VERSION 5.8 ;
BUSBITCHARS "[]" ;
DIVIDERCHAR "/" ;
UNITS
    DATABASE MICRONS 1000 ;
END UNITS

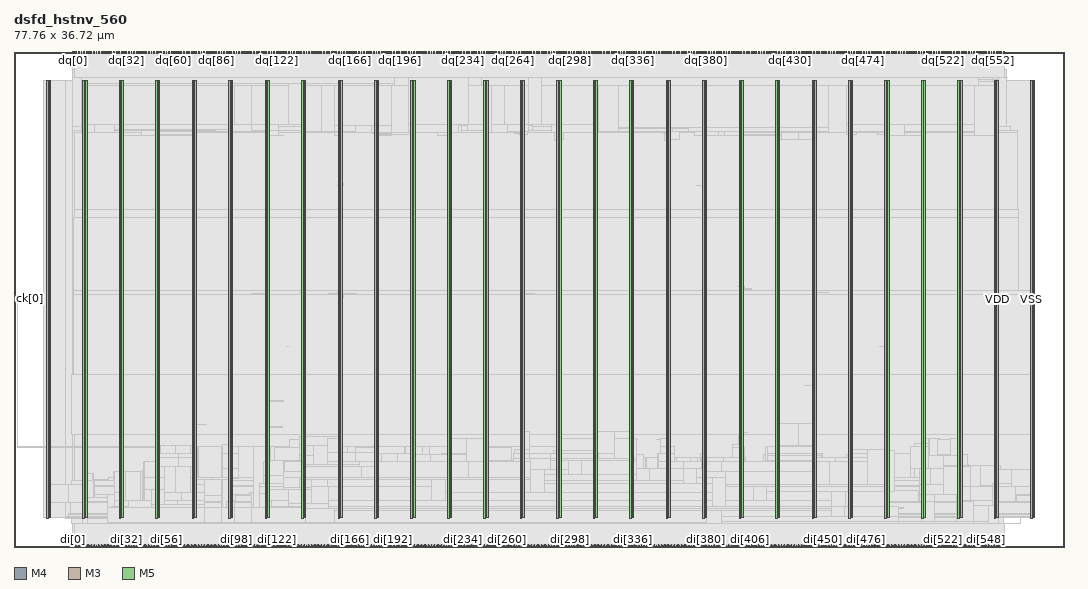
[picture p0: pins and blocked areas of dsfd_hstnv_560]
MACRO dsfd_hstnv_560
  FOREIGN dsfd_hstnv_560 0 0 ;
  CLASS BLOCK ;
  SIZE 77.76 BY 36.72 ;
  PIN ck[0]
    DIRECTION INPUT ;
    USE SIGNAL ;
    PORT
      LAYER M4 ;
        RECT  0 18.384 0.192 18.408 ;
    END
    PORT
      LAYER M4 ;
        RECT  0.156 18.384 0.275 18.408 ;
    END
  END ck[0]
  PIN di[0]
    DIRECTION INPUT ;
    USE SIGNAL ;
    PORT
      LAYER M3 ;
        RECT  4.356 0 4.374 0.144 ;
    END
  END di[0]
  PIN di[100]
    DIRECTION INPUT ;
    USE SIGNAL ;
    PORT
      LAYER M3 ;
        RECT  16.704 0 16.722 0.144 ;
    END
  END di[100]
  PIN di[101]
    DIRECTION INPUT ;
    USE SIGNAL ;
    PORT
      LAYER M5 ;
        RECT  16.848 0 16.872 0.192 ;
    END
  END di[101]
  PIN di[102]
    DIRECTION INPUT ;
    USE SIGNAL ;
    PORT
      LAYER M3 ;
        RECT  16.956 0 16.974 0.144 ;
    END
  END di[102]
  PIN di[103]
    DIRECTION INPUT ;
    USE SIGNAL ;
    PORT
      LAYER M5 ;
        RECT  17.088 0 17.112 0.192 ;
    END
  END di[103]
  PIN di[104]
    DIRECTION INPUT ;
    USE SIGNAL ;
    PORT
      LAYER M3 ;
        RECT  17.208 0 17.226 0.144 ;
    END
  END di[104]
  PIN di[105]
    DIRECTION INPUT ;
    USE SIGNAL ;
    PORT
      LAYER M5 ;
        RECT  17.328 0 17.352 0.192 ;
    END
  END di[105]
  PIN di[106]
    DIRECTION INPUT ;
    USE SIGNAL ;
    PORT
      LAYER M3 ;
        RECT  17.46 0 17.478 0.144 ;
    END
  END di[106]
  PIN di[107]
    DIRECTION INPUT ;
    USE SIGNAL ;
    PORT
      LAYER M5 ;
        RECT  17.568 0 17.592 0.192 ;
    END
  END di[107]
  PIN di[108]
    DIRECTION INPUT ;
    USE SIGNAL ;
    PORT
      LAYER M3 ;
        RECT  17.712 0 17.73 0.144 ;
    END
  END di[108]
  PIN di[109]
    DIRECTION INPUT ;
    USE SIGNAL ;
    PORT
      LAYER M5 ;
        RECT  17.808 0 17.832 0.192 ;
    END
  END di[109]
  PIN di[10]
    DIRECTION INPUT ;
    USE SIGNAL ;
    PORT
      LAYER M3 ;
        RECT  5.616 0 5.634 0.144 ;
    END
  END di[10]
  PIN di[110]
    DIRECTION INPUT ;
    USE SIGNAL ;
    PORT
      LAYER M3 ;
        RECT  17.964 0 17.982 0.144 ;
    END
  END di[110]
  PIN di[111]
    DIRECTION INPUT ;
    USE SIGNAL ;
    PORT
      LAYER M5 ;
        RECT  18.048 0 18.072 0.192 ;
    END
  END di[111]
  PIN di[112]
    DIRECTION INPUT ;
    USE SIGNAL ;
    PORT
      LAYER M3 ;
        RECT  18.18 0 18.198 0.144 ;
    END
  END di[112]
  PIN di[113]
    DIRECTION INPUT ;
    USE SIGNAL ;
    PORT
      LAYER M5 ;
        RECT  18.336 0 18.36 0.192 ;
    END
  END di[113]
  PIN di[114]
    DIRECTION INPUT ;
    USE SIGNAL ;
    PORT
      LAYER M3 ;
        RECT  18.432 0 18.45 0.144 ;
    END
  END di[114]
  PIN di[115]
    DIRECTION INPUT ;
    USE SIGNAL ;
    PORT
      LAYER M5 ;
        RECT  18.576 0 18.6 0.192 ;
    END
  END di[115]
  PIN di[116]
    DIRECTION INPUT ;
    USE SIGNAL ;
    PORT
      LAYER M3 ;
        RECT  18.684 0 18.702 0.144 ;
    END
  END di[116]
  PIN di[117]
    DIRECTION INPUT ;
    USE SIGNAL ;
    PORT
      LAYER M5 ;
        RECT  18.816 0 18.84 0.192 ;
    END
  END di[117]
  PIN di[118]
    DIRECTION INPUT ;
    USE SIGNAL ;
    PORT
      LAYER M3 ;
        RECT  18.936 0 18.954 0.144 ;
    END
  END di[118]
  PIN di[119]
    DIRECTION INPUT ;
    USE SIGNAL ;
    PORT
      LAYER M5 ;
        RECT  19.056 0 19.08 0.192 ;
    END
  END di[119]
  PIN di[11]
    DIRECTION INPUT ;
    USE SIGNAL ;
    PORT
      LAYER M5 ;
        RECT  5.712 0 5.736 0.192 ;
    END
  END di[11]
  PIN di[120]
    DIRECTION INPUT ;
    USE SIGNAL ;
    PORT
      LAYER M3 ;
        RECT  19.188 0 19.206 0.144 ;
    END
  END di[120]
  PIN di[121]
    DIRECTION INPUT ;
    USE SIGNAL ;
    PORT
      LAYER M5 ;
        RECT  19.296 0 19.32 0.192 ;
    END
  END di[121]
  PIN di[122]
    DIRECTION INPUT ;
    USE SIGNAL ;
    PORT
      LAYER M3 ;
        RECT  19.44 0 19.458 0.144 ;
    END
  END di[122]
  PIN di[123]
    DIRECTION INPUT ;
    USE SIGNAL ;
    PORT
      LAYER M5 ;
        RECT  19.536 0 19.56 0.192 ;
    END
  END di[123]
  PIN di[124]
    DIRECTION INPUT ;
    USE SIGNAL ;
    PORT
      LAYER M3 ;
        RECT  19.692 0 19.71 0.144 ;
    END
  END di[124]
  PIN di[125]
    DIRECTION INPUT ;
    USE SIGNAL ;
    PORT
      LAYER M5 ;
        RECT  19.776 0 19.8 0.192 ;
    END
  END di[125]
  PIN di[126]
    DIRECTION INPUT ;
    USE SIGNAL ;
    PORT
      LAYER M3 ;
        RECT  19.908 0 19.926 0.144 ;
    END
  END di[126]
  PIN di[127]
    DIRECTION INPUT ;
    USE SIGNAL ;
    PORT
      LAYER M5 ;
        RECT  20.064 0 20.088 0.192 ;
    END
  END di[127]
  PIN di[128]
    DIRECTION INPUT ;
    USE SIGNAL ;
    PORT
      LAYER M3 ;
        RECT  20.16 0 20.178 0.144 ;
    END
  END di[128]
  PIN di[129]
    DIRECTION INPUT ;
    USE SIGNAL ;
    PORT
      LAYER M5 ;
        RECT  20.304 0 20.328 0.192 ;
    END
  END di[129]
  PIN di[12]
    DIRECTION INPUT ;
    USE SIGNAL ;
    PORT
      LAYER M3 ;
        RECT  5.868 0 5.886 0.144 ;
    END
  END di[12]
  PIN di[130]
    DIRECTION INPUT ;
    USE SIGNAL ;
    PORT
      LAYER M3 ;
        RECT  20.412 0 20.43 0.144 ;
    END
  END di[130]
  PIN di[131]
    DIRECTION INPUT ;
    USE SIGNAL ;
    PORT
      LAYER M5 ;
        RECT  20.544 0 20.568 0.192 ;
    END
  END di[131]
  PIN di[132]
    DIRECTION INPUT ;
    USE SIGNAL ;
    PORT
      LAYER M3 ;
        RECT  20.664 0 20.682 0.144 ;
    END
  END di[132]
  PIN di[133]
    DIRECTION INPUT ;
    USE SIGNAL ;
    PORT
      LAYER M5 ;
        RECT  20.784 0 20.808 0.192 ;
    END
  END di[133]
  PIN di[134]
    DIRECTION INPUT ;
    USE SIGNAL ;
    PORT
      LAYER M3 ;
        RECT  20.916 0 20.934 0.144 ;
    END
  END di[134]
  PIN di[135]
    DIRECTION INPUT ;
    USE SIGNAL ;
    PORT
      LAYER M5 ;
        RECT  21.024 0 21.048 0.192 ;
    END
  END di[135]
  PIN di[136]
    DIRECTION INPUT ;
    USE SIGNAL ;
    PORT
      LAYER M3 ;
        RECT  21.168 0 21.186 0.144 ;
    END
  END di[136]
  PIN di[137]
    DIRECTION INPUT ;
    USE SIGNAL ;
    PORT
      LAYER M5 ;
        RECT  21.264 0 21.288 0.192 ;
    END
  END di[137]
  PIN di[138]
    DIRECTION INPUT ;
    USE SIGNAL ;
    PORT
      LAYER M3 ;
        RECT  21.42 0 21.438 0.144 ;
    END
  END di[138]
  PIN di[139]
    DIRECTION INPUT ;
    USE SIGNAL ;
    PORT
      LAYER M5 ;
        RECT  21.504 0 21.528 0.192 ;
    END
  END di[139]
  PIN di[13]
    DIRECTION INPUT ;
    USE SIGNAL ;
    PORT
      LAYER M5 ;
        RECT  5.952 0 5.976 0.192 ;
    END
  END di[13]
  PIN di[140]
    DIRECTION INPUT ;
    USE SIGNAL ;
    PORT
      LAYER M3 ;
        RECT  21.636 0 21.654 0.144 ;
    END
  END di[140]
  PIN di[141]
    DIRECTION INPUT ;
    USE SIGNAL ;
    PORT
      LAYER M5 ;
        RECT  21.792 0 21.816 0.192 ;
    END
  END di[141]
  PIN di[142]
    DIRECTION INPUT ;
    USE SIGNAL ;
    PORT
      LAYER M3 ;
        RECT  21.888 0 21.906 0.144 ;
    END
  END di[142]
  PIN di[143]
    DIRECTION INPUT ;
    USE SIGNAL ;
    PORT
      LAYER M5 ;
        RECT  22.032 0 22.056 0.192 ;
    END
  END di[143]
  PIN di[144]
    DIRECTION INPUT ;
    USE SIGNAL ;
    PORT
      LAYER M3 ;
        RECT  22.14 0 22.158 0.144 ;
    END
  END di[144]
  PIN di[145]
    DIRECTION INPUT ;
    USE SIGNAL ;
    PORT
      LAYER M5 ;
        RECT  22.272 0 22.296 0.192 ;
    END
  END di[145]
  PIN di[146]
    DIRECTION INPUT ;
    USE SIGNAL ;
    PORT
      LAYER M3 ;
        RECT  22.392 0 22.41 0.144 ;
    END
  END di[146]
  PIN di[147]
    DIRECTION INPUT ;
    USE SIGNAL ;
    PORT
      LAYER M5 ;
        RECT  22.512 0 22.536 0.192 ;
    END
  END di[147]
  PIN di[148]
    DIRECTION INPUT ;
    USE SIGNAL ;
    PORT
      LAYER M3 ;
        RECT  22.644 0 22.662 0.144 ;
    END
  END di[148]
  PIN di[149]
    DIRECTION INPUT ;
    USE SIGNAL ;
    PORT
      LAYER M5 ;
        RECT  22.752 0 22.776 0.192 ;
    END
  END di[149]
  PIN di[14]
    DIRECTION INPUT ;
    USE SIGNAL ;
    PORT
      LAYER M3 ;
        RECT  6.084 0 6.102 0.144 ;
    END
  END di[14]
  PIN di[150]
    DIRECTION INPUT ;
    USE SIGNAL ;
    PORT
      LAYER M3 ;
        RECT  22.896 0 22.914 0.144 ;
    END
  END di[150]
  PIN di[151]
    DIRECTION INPUT ;
    USE SIGNAL ;
    PORT
      LAYER M5 ;
        RECT  22.992 0 23.016 0.192 ;
    END
  END di[151]
  PIN di[152]
    DIRECTION INPUT ;
    USE SIGNAL ;
    PORT
      LAYER M3 ;
        RECT  23.148 0 23.166 0.144 ;
    END
  END di[152]
  PIN di[153]
    DIRECTION INPUT ;
    USE SIGNAL ;
    PORT
      LAYER M5 ;
        RECT  23.232 0 23.256 0.192 ;
    END
  END di[153]
  PIN di[154]
    DIRECTION INPUT ;
    USE SIGNAL ;
    PORT
      LAYER M3 ;
        RECT  23.364 0 23.382 0.144 ;
    END
  END di[154]
  PIN di[155]
    DIRECTION INPUT ;
    USE SIGNAL ;
    PORT
      LAYER M5 ;
        RECT  23.52 0 23.544 0.192 ;
    END
  END di[155]
  PIN di[156]
    DIRECTION INPUT ;
    USE SIGNAL ;
    PORT
      LAYER M3 ;
        RECT  23.616 0 23.634 0.144 ;
    END
  END di[156]
  PIN di[157]
    DIRECTION INPUT ;
    USE SIGNAL ;
    PORT
      LAYER M5 ;
        RECT  23.76 0 23.784 0.192 ;
    END
  END di[157]
  PIN di[158]
    DIRECTION INPUT ;
    USE SIGNAL ;
    PORT
      LAYER M3 ;
        RECT  23.868 0 23.886 0.144 ;
    END
  END di[158]
  PIN di[159]
    DIRECTION INPUT ;
    USE SIGNAL ;
    PORT
      LAYER M5 ;
        RECT  24 0 24.024 0.192 ;
    END
  END di[159]
  PIN di[15]
    DIRECTION INPUT ;
    USE SIGNAL ;
    PORT
      LAYER M5 ;
        RECT  6.24 0 6.264 0.192 ;
    END
  END di[15]
  PIN di[160]
    DIRECTION INPUT ;
    USE SIGNAL ;
    PORT
      LAYER M3 ;
        RECT  24.12 0 24.138 0.144 ;
    END
  END di[160]
  PIN di[161]
    DIRECTION INPUT ;
    USE SIGNAL ;
    PORT
      LAYER M5 ;
        RECT  24.24 0 24.264 0.192 ;
    END
  END di[161]
  PIN di[162]
    DIRECTION INPUT ;
    USE SIGNAL ;
    PORT
      LAYER M3 ;
        RECT  24.372 0 24.39 0.144 ;
    END
  END di[162]
  PIN di[163]
    DIRECTION INPUT ;
    USE SIGNAL ;
    PORT
      LAYER M5 ;
        RECT  24.48 0 24.504 0.192 ;
    END
  END di[163]
  PIN di[164]
    DIRECTION INPUT ;
    USE SIGNAL ;
    PORT
      LAYER M3 ;
        RECT  24.624 0 24.642 0.144 ;
    END
  END di[164]
  PIN di[165]
    DIRECTION INPUT ;
    USE SIGNAL ;
    PORT
      LAYER M5 ;
        RECT  24.72 0 24.744 0.192 ;
    END
  END di[165]
  PIN di[166]
    DIRECTION INPUT ;
    USE SIGNAL ;
    PORT
      LAYER M3 ;
        RECT  24.876 0 24.894 0.144 ;
    END
  END di[166]
  PIN di[167]
    DIRECTION INPUT ;
    USE SIGNAL ;
    PORT
      LAYER M5 ;
        RECT  24.96 0 24.984 0.192 ;
    END
  END di[167]
  PIN di[168]
    DIRECTION INPUT ;
    USE SIGNAL ;
    PORT
      LAYER M3 ;
        RECT  25.092 0 25.11 0.144 ;
    END
  END di[168]
  PIN di[169]
    DIRECTION INPUT ;
    USE SIGNAL ;
    PORT
      LAYER M5 ;
        RECT  25.248 0 25.272 0.192 ;
    END
  END di[169]
  PIN di[16]
    DIRECTION INPUT ;
    USE SIGNAL ;
    PORT
      LAYER M3 ;
        RECT  6.336 0 6.354 0.144 ;
    END
  END di[16]
  PIN di[170]
    DIRECTION INPUT ;
    USE SIGNAL ;
    PORT
      LAYER M3 ;
        RECT  25.344 0 25.362 0.144 ;
    END
  END di[170]
  PIN di[171]
    DIRECTION INPUT ;
    USE SIGNAL ;
    PORT
      LAYER M5 ;
        RECT  25.488 0 25.512 0.192 ;
    END
  END di[171]
  PIN di[172]
    DIRECTION INPUT ;
    USE SIGNAL ;
    PORT
      LAYER M3 ;
        RECT  25.596 0 25.614 0.144 ;
    END
  END di[172]
  PIN di[173]
    DIRECTION INPUT ;
    USE SIGNAL ;
    PORT
      LAYER M5 ;
        RECT  25.728 0 25.752 0.192 ;
    END
  END di[173]
  PIN di[174]
    DIRECTION INPUT ;
    USE SIGNAL ;
    PORT
      LAYER M3 ;
        RECT  25.848 0 25.866 0.144 ;
    END
  END di[174]
  PIN di[175]
    DIRECTION INPUT ;
    USE SIGNAL ;
    PORT
      LAYER M5 ;
        RECT  25.968 0 25.992 0.192 ;
    END
  END di[175]
  PIN di[176]
    DIRECTION INPUT ;
    USE SIGNAL ;
    PORT
      LAYER M3 ;
        RECT  26.1 0 26.118 0.144 ;
    END
  END di[176]
  PIN di[177]
    DIRECTION INPUT ;
    USE SIGNAL ;
    PORT
      LAYER M5 ;
        RECT  26.208 0 26.232 0.192 ;
    END
  END di[177]
  PIN di[178]
    DIRECTION INPUT ;
    USE SIGNAL ;
    PORT
      LAYER M3 ;
        RECT  26.352 0 26.37 0.144 ;
    END
  END di[178]
  PIN di[179]
    DIRECTION INPUT ;
    USE SIGNAL ;
    PORT
      LAYER M5 ;
        RECT  26.448 0 26.472 0.192 ;
    END
  END di[179]
  PIN di[17]
    DIRECTION INPUT ;
    USE SIGNAL ;
    PORT
      LAYER M5 ;
        RECT  6.48 0 6.504 0.192 ;
    END
  END di[17]
  PIN di[180]
    DIRECTION INPUT ;
    USE SIGNAL ;
    PORT
      LAYER M3 ;
        RECT  26.604 0 26.622 0.144 ;
    END
  END di[180]
  PIN di[181]
    DIRECTION INPUT ;
    USE SIGNAL ;
    PORT
      LAYER M5 ;
        RECT  26.688 0 26.712 0.192 ;
    END
  END di[181]
  PIN di[182]
    DIRECTION INPUT ;
    USE SIGNAL ;
    PORT
      LAYER M3 ;
        RECT  26.82 0 26.838 0.144 ;
    END
  END di[182]
  PIN di[183]
    DIRECTION INPUT ;
    USE SIGNAL ;
    PORT
      LAYER M5 ;
        RECT  26.976 0 27 0.192 ;
    END
  END di[183]
  PIN di[184]
    DIRECTION INPUT ;
    USE SIGNAL ;
    PORT
      LAYER M3 ;
        RECT  27.072 0 27.09 0.144 ;
    END
  END di[184]
  PIN di[185]
    DIRECTION INPUT ;
    USE SIGNAL ;
    PORT
      LAYER M5 ;
        RECT  27.216 0 27.24 0.192 ;
    END
  END di[185]
  PIN di[186]
    DIRECTION INPUT ;
    USE SIGNAL ;
    PORT
      LAYER M3 ;
        RECT  27.324 0 27.342 0.144 ;
    END
  END di[186]
  PIN di[187]
    DIRECTION INPUT ;
    USE SIGNAL ;
    PORT
      LAYER M5 ;
        RECT  27.456 0 27.48 0.192 ;
    END
  END di[187]
  PIN di[188]
    DIRECTION INPUT ;
    USE SIGNAL ;
    PORT
      LAYER M3 ;
        RECT  27.576 0 27.594 0.144 ;
    END
  END di[188]
  PIN di[189]
    DIRECTION INPUT ;
    USE SIGNAL ;
    PORT
      LAYER M5 ;
        RECT  27.696 0 27.72 0.192 ;
    END
  END di[189]
  PIN di[18]
    DIRECTION INPUT ;
    USE SIGNAL ;
    PORT
      LAYER M3 ;
        RECT  6.588 0 6.606 0.144 ;
    END
  END di[18]
  PIN di[190]
    DIRECTION INPUT ;
    USE SIGNAL ;
    PORT
      LAYER M3 ;
        RECT  27.828 0 27.846 0.144 ;
    END
  END di[190]
  PIN di[191]
    DIRECTION INPUT ;
    USE SIGNAL ;
    PORT
      LAYER M5 ;
        RECT  27.936 0 27.96 0.192 ;
    END
  END di[191]
  PIN di[192]
    DIRECTION INPUT ;
    USE SIGNAL ;
    PORT
      LAYER M3 ;
        RECT  28.08 0 28.098 0.144 ;
    END
  END di[192]
  PIN di[193]
    DIRECTION INPUT ;
    USE SIGNAL ;
    PORT
      LAYER M5 ;
        RECT  28.176 0 28.2 0.192 ;
    END
  END di[193]
  PIN di[194]
    DIRECTION INPUT ;
    USE SIGNAL ;
    PORT
      LAYER M3 ;
        RECT  28.332 0 28.35 0.144 ;
    END
  END di[194]
  PIN di[195]
    DIRECTION INPUT ;
    USE SIGNAL ;
    PORT
      LAYER M5 ;
        RECT  28.416 0 28.44 0.192 ;
    END
  END di[195]
  PIN di[196]
    DIRECTION INPUT ;
    USE SIGNAL ;
    PORT
      LAYER M3 ;
        RECT  28.548 0 28.566 0.144 ;
    END
  END di[196]
  PIN di[197]
    DIRECTION INPUT ;
    USE SIGNAL ;
    PORT
      LAYER M5 ;
        RECT  28.704 0 28.728 0.192 ;
    END
  END di[197]
  PIN di[198]
    DIRECTION INPUT ;
    USE SIGNAL ;
    PORT
      LAYER M3 ;
        RECT  28.8 0 28.818 0.144 ;
    END
  END di[198]
  PIN di[199]
    DIRECTION INPUT ;
    USE SIGNAL ;
    PORT
      LAYER M5 ;
        RECT  28.944 0 28.968 0.192 ;
    END
  END di[199]
  PIN di[19]
    DIRECTION INPUT ;
    USE SIGNAL ;
    PORT
      LAYER M5 ;
        RECT  6.72 0 6.744 0.192 ;
    END
  END di[19]
  PIN di[1]
    DIRECTION INPUT ;
    USE SIGNAL ;
    PORT
      LAYER M5 ;
        RECT  4.512 0 4.536 0.192 ;
    END
  END di[1]
  PIN di[200]
    DIRECTION INPUT ;
    USE SIGNAL ;
    PORT
      LAYER M3 ;
        RECT  29.052 0 29.07 0.144 ;
    END
  END di[200]
  PIN di[201]
    DIRECTION INPUT ;
    USE SIGNAL ;
    PORT
      LAYER M5 ;
        RECT  29.184 0 29.208 0.192 ;
    END
  END di[201]
  PIN di[202]
    DIRECTION INPUT ;
    USE SIGNAL ;
    PORT
      LAYER M3 ;
        RECT  29.304 0 29.322 0.144 ;
    END
  END di[202]
  PIN di[203]
    DIRECTION INPUT ;
    USE SIGNAL ;
    PORT
      LAYER M5 ;
        RECT  29.424 0 29.448 0.192 ;
    END
  END di[203]
  PIN di[204]
    DIRECTION INPUT ;
    USE SIGNAL ;
    PORT
      LAYER M3 ;
        RECT  29.556 0 29.574 0.144 ;
    END
  END di[204]
  PIN di[205]
    DIRECTION INPUT ;
    USE SIGNAL ;
    PORT
      LAYER M5 ;
        RECT  29.664 0 29.688 0.192 ;
    END
  END di[205]
  PIN di[206]
    DIRECTION INPUT ;
    USE SIGNAL ;
    PORT
      LAYER M3 ;
        RECT  29.808 0 29.826 0.144 ;
    END
  END di[206]
  PIN di[207]
    DIRECTION INPUT ;
    USE SIGNAL ;
    PORT
      LAYER M5 ;
        RECT  29.904 0 29.928 0.192 ;
    END
  END di[207]
  PIN di[208]
    DIRECTION INPUT ;
    USE SIGNAL ;
    PORT
      LAYER M3 ;
        RECT  30.06 0 30.078 0.144 ;
    END
  END di[208]
  PIN di[209]
    DIRECTION INPUT ;
    USE SIGNAL ;
    PORT
      LAYER M5 ;
        RECT  30.144 0 30.168 0.192 ;
    END
  END di[209]
  PIN di[20]
    DIRECTION INPUT ;
    USE SIGNAL ;
    PORT
      LAYER M3 ;
        RECT  6.84 0 6.858 0.144 ;
    END
  END di[20]
  PIN di[210]
    DIRECTION INPUT ;
    USE SIGNAL ;
    PORT
      LAYER M3 ;
        RECT  30.276 0 30.294 0.144 ;
    END
  END di[210]
  PIN di[211]
    DIRECTION INPUT ;
    USE SIGNAL ;
    PORT
      LAYER M5 ;
        RECT  30.432 0 30.456 0.192 ;
    END
  END di[211]
  PIN di[212]
    DIRECTION INPUT ;
    USE SIGNAL ;
    PORT
      LAYER M3 ;
        RECT  30.528 0 30.546 0.144 ;
    END
  END di[212]
  PIN di[213]
    DIRECTION INPUT ;
    USE SIGNAL ;
    PORT
      LAYER M5 ;
        RECT  30.672 0 30.696 0.192 ;
    END
  END di[213]
  PIN di[214]
    DIRECTION INPUT ;
    USE SIGNAL ;
    PORT
      LAYER M3 ;
        RECT  30.78 0 30.798 0.144 ;
    END
  END di[214]
  PIN di[215]
    DIRECTION INPUT ;
    USE SIGNAL ;
    PORT
      LAYER M5 ;
        RECT  30.912 0 30.936 0.192 ;
    END
  END di[215]
  PIN di[216]
    DIRECTION INPUT ;
    USE SIGNAL ;
    PORT
      LAYER M3 ;
        RECT  31.032 0 31.05 0.144 ;
    END
  END di[216]
  PIN di[217]
    DIRECTION INPUT ;
    USE SIGNAL ;
    PORT
      LAYER M5 ;
        RECT  31.152 0 31.176 0.192 ;
    END
  END di[217]
  PIN di[218]
    DIRECTION INPUT ;
    USE SIGNAL ;
    PORT
      LAYER M3 ;
        RECT  31.284 0 31.302 0.144 ;
    END
  END di[218]
  PIN di[219]
    DIRECTION INPUT ;
    USE SIGNAL ;
    PORT
      LAYER M5 ;
        RECT  31.392 0 31.416 0.192 ;
    END
  END di[219]
  PIN di[21]
    DIRECTION INPUT ;
    USE SIGNAL ;
    PORT
      LAYER M5 ;
        RECT  6.96 0 6.984 0.192 ;
    END
  END di[21]
  PIN di[220]
    DIRECTION INPUT ;
    USE SIGNAL ;
    PORT
      LAYER M3 ;
        RECT  31.536 0 31.554 0.144 ;
    END
  END di[220]
  PIN di[221]
    DIRECTION INPUT ;
    USE SIGNAL ;
    PORT
      LAYER M5 ;
        RECT  31.632 0 31.656 0.192 ;
    END
  END di[221]
  PIN di[222]
    DIRECTION INPUT ;
    USE SIGNAL ;
    PORT
      LAYER M3 ;
        RECT  31.788 0 31.806 0.144 ;
    END
  END di[222]
  PIN di[223]
    DIRECTION INPUT ;
    USE SIGNAL ;
    PORT
      LAYER M5 ;
        RECT  31.872 0 31.896 0.192 ;
    END
  END di[223]
  PIN di[224]
    DIRECTION INPUT ;
    USE SIGNAL ;
    PORT
      LAYER M3 ;
        RECT  32.004 0 32.022 0.144 ;
    END
  END di[224]
  PIN di[225]
    DIRECTION INPUT ;
    USE SIGNAL ;
    PORT
      LAYER M5 ;
        RECT  32.16 0 32.184 0.192 ;
    END
  END di[225]
  PIN di[226]
    DIRECTION INPUT ;
    USE SIGNAL ;
    PORT
      LAYER M3 ;
        RECT  32.256 0 32.274 0.144 ;
    END
  END di[226]
  PIN di[227]
    DIRECTION INPUT ;
    USE SIGNAL ;
    PORT
      LAYER M5 ;
        RECT  32.4 0 32.424 0.192 ;
    END
  END di[227]
  PIN di[228]
    DIRECTION INPUT ;
    USE SIGNAL ;
    PORT
      LAYER M3 ;
        RECT  32.508 0 32.526 0.144 ;
    END
  END di[228]
  PIN di[229]
    DIRECTION INPUT ;
    USE SIGNAL ;
    PORT
      LAYER M5 ;
        RECT  32.64 0 32.664 0.192 ;
    END
  END di[229]
  PIN di[22]
    DIRECTION INPUT ;
    USE SIGNAL ;
    PORT
      LAYER M3 ;
        RECT  7.092 0 7.11 0.144 ;
    END
  END di[22]
  PIN di[230]
    DIRECTION INPUT ;
    USE SIGNAL ;
    PORT
      LAYER M3 ;
        RECT  32.76 0 32.778 0.144 ;
    END
  END di[230]
  PIN di[231]
    DIRECTION INPUT ;
    USE SIGNAL ;
    PORT
      LAYER M5 ;
        RECT  32.88 0 32.904 0.192 ;
    END
  END di[231]
  PIN di[232]
    DIRECTION INPUT ;
    USE SIGNAL ;
    PORT
      LAYER M3 ;
        RECT  33.012 0 33.03 0.144 ;
    END
  END di[232]
  PIN di[233]
    DIRECTION INPUT ;
    USE SIGNAL ;
    PORT
      LAYER M5 ;
        RECT  33.12 0 33.144 0.192 ;
    END
  END di[233]
  PIN di[234]
    DIRECTION INPUT ;
    USE SIGNAL ;
    PORT
      LAYER M3 ;
        RECT  33.264 0 33.282 0.144 ;
    END
  END di[234]
  PIN di[235]
    DIRECTION INPUT ;
    USE SIGNAL ;
    PORT
      LAYER M5 ;
        RECT  33.36 0 33.384 0.192 ;
    END
  END di[235]
  PIN di[236]
    DIRECTION INPUT ;
    USE SIGNAL ;
    PORT
      LAYER M3 ;
        RECT  33.516 0 33.534 0.144 ;
    END
  END di[236]
  PIN di[237]
    DIRECTION INPUT ;
    USE SIGNAL ;
    PORT
      LAYER M5 ;
        RECT  33.6 0 33.624 0.192 ;
    END
  END di[237]
  PIN di[238]
    DIRECTION INPUT ;
    USE SIGNAL ;
    PORT
      LAYER M3 ;
        RECT  33.732 0 33.75 0.144 ;
    END
  END di[238]
  PIN di[239]
    DIRECTION INPUT ;
    USE SIGNAL ;
    PORT
      LAYER M5 ;
        RECT  33.888 0 33.912 0.192 ;
    END
    PORT
      LAYER M5 ;
        RECT  33.744 0.133 34.008 0.144 ;
    END
  END di[239]
  PIN di[23]
    DIRECTION INPUT ;
    USE SIGNAL ;
    PORT
      LAYER M5 ;
        RECT  7.2 0 7.224 0.192 ;
    END
  END di[23]
  PIN di[240]
    DIRECTION INPUT ;
    USE SIGNAL ;
    PORT
      LAYER M3 ;
        RECT  33.984 0 34.002 0.144 ;
    END
  END di[240]
  PIN di[241]
    DIRECTION INPUT ;
    USE SIGNAL ;
    PORT
      LAYER M5 ;
        RECT  34.128 0 34.152 0.192 ;
    END
  END di[241]
  PIN di[242]
    DIRECTION INPUT ;
    USE SIGNAL ;
    PORT
      LAYER M3 ;
        RECT  34.236 0 34.254 0.144 ;
    END
  END di[242]
  PIN di[243]
    DIRECTION INPUT ;
    USE SIGNAL ;
    PORT
      LAYER M5 ;
        RECT  34.368 0 34.392 0.192 ;
    END
  END di[243]
  PIN di[244]
    DIRECTION INPUT ;
    USE SIGNAL ;
    PORT
      LAYER M3 ;
        RECT  34.488 0 34.506 0.144 ;
    END
  END di[244]
  PIN di[245]
    DIRECTION INPUT ;
    USE SIGNAL ;
    PORT
      LAYER M5 ;
        RECT  34.608 0 34.632 0.192 ;
    END
  END di[245]
  PIN di[246]
    DIRECTION INPUT ;
    USE SIGNAL ;
    PORT
      LAYER M3 ;
        RECT  34.74 0 34.758 0.144 ;
    END
  END di[246]
  PIN di[247]
    DIRECTION INPUT ;
    USE SIGNAL ;
    PORT
      LAYER M5 ;
        RECT  34.848 0 34.872 0.192 ;
    END
  END di[247]
  PIN di[248]
    DIRECTION INPUT ;
    USE SIGNAL ;
    PORT
      LAYER M3 ;
        RECT  34.992 0 35.01 0.144 ;
    END
  END di[248]
  PIN di[249]
    DIRECTION INPUT ;
    USE SIGNAL ;
    PORT
      LAYER M5 ;
        RECT  35.088 0 35.112 0.192 ;
    END
  END di[249]
  PIN di[24]
    DIRECTION INPUT ;
    USE SIGNAL ;
    PORT
      LAYER M3 ;
        RECT  7.344 0 7.362 0.144 ;
    END
  END di[24]
  PIN di[250]
    DIRECTION INPUT ;
    USE SIGNAL ;
    PORT
      LAYER M3 ;
        RECT  35.244 0 35.262 0.144 ;
    END
  END di[250]
  PIN di[251]
    DIRECTION INPUT ;
    USE SIGNAL ;
    PORT
      LAYER M5 ;
        RECT  35.328 0 35.352 0.192 ;
    END
  END di[251]
  PIN di[252]
    DIRECTION INPUT ;
    USE SIGNAL ;
    PORT
      LAYER M3 ;
        RECT  35.46 0 35.478 0.144 ;
    END
  END di[252]
  PIN di[253]
    DIRECTION INPUT ;
    USE SIGNAL ;
    PORT
      LAYER M5 ;
        RECT  35.616 0 35.64 0.192 ;
    END
  END di[253]
  PIN di[254]
    DIRECTION INPUT ;
    USE SIGNAL ;
    PORT
      LAYER M3 ;
        RECT  35.712 0 35.73 0.144 ;
    END
  END di[254]
  PIN di[255]
    DIRECTION INPUT ;
    USE SIGNAL ;
    PORT
      LAYER M5 ;
        RECT  35.856 0 35.88 0.192 ;
    END
  END di[255]
  PIN di[256]
    DIRECTION INPUT ;
    USE SIGNAL ;
    PORT
      LAYER M3 ;
        RECT  35.964 0 35.982 0.144 ;
    END
  END di[256]
  PIN di[257]
    DIRECTION INPUT ;
    USE SIGNAL ;
    PORT
      LAYER M5 ;
        RECT  36.096 0 36.12 0.192 ;
    END
  END di[257]
  PIN di[258]
    DIRECTION INPUT ;
    USE SIGNAL ;
    PORT
      LAYER M3 ;
        RECT  36.216 0 36.234 0.144 ;
    END
  END di[258]
  PIN di[259]
    DIRECTION INPUT ;
    USE SIGNAL ;
    PORT
      LAYER M5 ;
        RECT  36.336 0 36.36 0.192 ;
    END
  END di[259]
  PIN di[25]
    DIRECTION INPUT ;
    USE SIGNAL ;
    PORT
      LAYER M5 ;
        RECT  7.44 0 7.464 0.192 ;
    END
  END di[25]
  PIN di[260]
    DIRECTION INPUT ;
    USE SIGNAL ;
    PORT
      LAYER M3 ;
        RECT  36.468 0 36.486 0.144 ;
    END
  END di[260]
  PIN di[261]
    DIRECTION INPUT ;
    USE SIGNAL ;
    PORT
      LAYER M5 ;
        RECT  36.576 0 36.6 0.192 ;
    END
  END di[261]
  PIN di[262]
    DIRECTION INPUT ;
    USE SIGNAL ;
    PORT
      LAYER M3 ;
        RECT  36.72 0 36.738 0.144 ;
    END
  END di[262]
  PIN di[263]
    DIRECTION INPUT ;
    USE SIGNAL ;
    PORT
      LAYER M5 ;
        RECT  36.816 0 36.84 0.192 ;
    END
  END di[263]
  PIN di[264]
    DIRECTION INPUT ;
    USE SIGNAL ;
    PORT
      LAYER M3 ;
        RECT  36.972 0 36.99 0.144 ;
    END
  END di[264]
  PIN di[265]
    DIRECTION INPUT ;
    USE SIGNAL ;
    PORT
      LAYER M5 ;
        RECT  37.056 0 37.08 0.192 ;
    END
  END di[265]
  PIN di[266]
    DIRECTION INPUT ;
    USE SIGNAL ;
    PORT
      LAYER M3 ;
        RECT  37.188 0 37.206 0.144 ;
    END
  END di[266]
  PIN di[267]
    DIRECTION INPUT ;
    USE SIGNAL ;
    PORT
      LAYER M5 ;
        RECT  37.344 0 37.368 0.192 ;
    END
  END di[267]
  PIN di[268]
    DIRECTION INPUT ;
    USE SIGNAL ;
    PORT
      LAYER M3 ;
        RECT  37.44 0 37.458 0.144 ;
    END
  END di[268]
  PIN di[269]
    DIRECTION INPUT ;
    USE SIGNAL ;
    PORT
      LAYER M5 ;
        RECT  37.584 0 37.608 0.192 ;
    END
  END di[269]
  PIN di[26]
    DIRECTION INPUT ;
    USE SIGNAL ;
    PORT
      LAYER M3 ;
        RECT  7.596 0 7.614 0.144 ;
    END
  END di[26]
  PIN di[270]
    DIRECTION INPUT ;
    USE SIGNAL ;
    PORT
      LAYER M3 ;
        RECT  37.692 0 37.71 0.144 ;
    END
  END di[270]
  PIN di[271]
    DIRECTION INPUT ;
    USE SIGNAL ;
    PORT
      LAYER M5 ;
        RECT  37.824 0 37.848 0.192 ;
    END
  END di[271]
  PIN di[272]
    DIRECTION INPUT ;
    USE SIGNAL ;
    PORT
      LAYER M3 ;
        RECT  37.944 0 37.962 0.144 ;
    END
  END di[272]
  PIN di[273]
    DIRECTION INPUT ;
    USE SIGNAL ;
    PORT
      LAYER M5 ;
        RECT  38.064 0 38.088 0.192 ;
    END
  END di[273]
  PIN di[274]
    DIRECTION INPUT ;
    USE SIGNAL ;
    PORT
      LAYER M3 ;
        RECT  38.196 0 38.214 0.144 ;
    END
  END di[274]
  PIN di[275]
    DIRECTION INPUT ;
    USE SIGNAL ;
    PORT
      LAYER M5 ;
        RECT  38.304 0 38.328 0.192 ;
    END
  END di[275]
  PIN di[276]
    DIRECTION INPUT ;
    USE SIGNAL ;
    PORT
      LAYER M3 ;
        RECT  38.448 0 38.466 0.144 ;
    END
  END di[276]
  PIN di[277]
    DIRECTION INPUT ;
    USE SIGNAL ;
    PORT
      LAYER M5 ;
        RECT  38.544 0 38.568 0.192 ;
    END
  END di[277]
  PIN di[278]
    DIRECTION INPUT ;
    USE SIGNAL ;
    PORT
      LAYER M3 ;
        RECT  38.7 0 38.718 0.144 ;
    END
  END di[278]
  PIN di[279]
    DIRECTION INPUT ;
    USE SIGNAL ;
    PORT
      LAYER M5 ;
        RECT  38.784 0 38.808 0.192 ;
    END
  END di[279]
  PIN di[27]
    DIRECTION INPUT ;
    USE SIGNAL ;
    PORT
      LAYER M5 ;
        RECT  7.68 0 7.704 0.192 ;
    END
  END di[27]
  PIN di[280]
    DIRECTION INPUT ;
    USE SIGNAL ;
    PORT
      LAYER M3 ;
        RECT  38.916 0 38.934 0.144 ;
    END
  END di[280]
  PIN di[281]
    DIRECTION INPUT ;
    USE SIGNAL ;
    PORT
      LAYER M5 ;
        RECT  39.072 0 39.096 0.192 ;
    END
  END di[281]
  PIN di[282]
    DIRECTION INPUT ;
    USE SIGNAL ;
    PORT
      LAYER M3 ;
        RECT  39.168 0 39.186 0.144 ;
    END
  END di[282]
  PIN di[283]
    DIRECTION INPUT ;
    USE SIGNAL ;
    PORT
      LAYER M5 ;
        RECT  39.312 0 39.336 0.192 ;
    END
  END di[283]
  PIN di[284]
    DIRECTION INPUT ;
    USE SIGNAL ;
    PORT
      LAYER M3 ;
        RECT  39.42 0 39.438 0.144 ;
    END
  END di[284]
  PIN di[285]
    DIRECTION INPUT ;
    USE SIGNAL ;
    PORT
      LAYER M5 ;
        RECT  39.552 0 39.576 0.192 ;
    END
  END di[285]
  PIN di[286]
    DIRECTION INPUT ;
    USE SIGNAL ;
    PORT
      LAYER M3 ;
        RECT  39.672 0 39.69 0.144 ;
    END
  END di[286]
  PIN di[287]
    DIRECTION INPUT ;
    USE SIGNAL ;
    PORT
      LAYER M5 ;
        RECT  39.792 0 39.816 0.192 ;
    END
  END di[287]
  PIN di[288]
    DIRECTION INPUT ;
    USE SIGNAL ;
    PORT
      LAYER M3 ;
        RECT  39.924 0 39.942 0.144 ;
    END
  END di[288]
  PIN di[289]
    DIRECTION INPUT ;
    USE SIGNAL ;
    PORT
      LAYER M5 ;
        RECT  40.032 0 40.056 0.192 ;
    END
  END di[289]
  PIN di[28]
    DIRECTION INPUT ;
    USE SIGNAL ;
    PORT
      LAYER M3 ;
        RECT  7.812 0 7.83 0.144 ;
    END
  END di[28]
  PIN di[290]
    DIRECTION INPUT ;
    USE SIGNAL ;
    PORT
      LAYER M3 ;
        RECT  40.176 0 40.194 0.144 ;
    END
  END di[290]
  PIN di[291]
    DIRECTION INPUT ;
    USE SIGNAL ;
    PORT
      LAYER M5 ;
        RECT  40.272 0 40.296 0.192 ;
    END
  END di[291]
  PIN di[292]
    DIRECTION INPUT ;
    USE SIGNAL ;
    PORT
      LAYER M3 ;
        RECT  40.428 0 40.446 0.144 ;
    END
  END di[292]
  PIN di[293]
    DIRECTION INPUT ;
    USE SIGNAL ;
    PORT
      LAYER M5 ;
        RECT  40.512 0 40.536 0.192 ;
    END
  END di[293]
  PIN di[294]
    DIRECTION INPUT ;
    USE SIGNAL ;
    PORT
      LAYER M3 ;
        RECT  40.644 0 40.662 0.144 ;
    END
  END di[294]
  PIN di[295]
    DIRECTION INPUT ;
    USE SIGNAL ;
    PORT
      LAYER M5 ;
        RECT  40.8 0 40.824 0.192 ;
    END
  END di[295]
  PIN di[296]
    DIRECTION INPUT ;
    USE SIGNAL ;
    PORT
      LAYER M3 ;
        RECT  40.896 0 40.914 0.144 ;
    END
  END di[296]
  PIN di[297]
    DIRECTION INPUT ;
    USE SIGNAL ;
    PORT
      LAYER M5 ;
        RECT  41.04 0 41.064 0.192 ;
    END
  END di[297]
  PIN di[298]
    DIRECTION INPUT ;
    USE SIGNAL ;
    PORT
      LAYER M3 ;
        RECT  41.148 0 41.166 0.144 ;
    END
  END di[298]
  PIN di[299]
    DIRECTION INPUT ;
    USE SIGNAL ;
    PORT
      LAYER M5 ;
        RECT  41.28 0 41.304 0.192 ;
    END
  END di[299]
  PIN di[29]
    DIRECTION INPUT ;
    USE SIGNAL ;
    PORT
      LAYER M5 ;
        RECT  7.968 0 7.992 0.192 ;
    END
  END di[29]
  PIN di[2]
    DIRECTION INPUT ;
    USE SIGNAL ;
    PORT
      LAYER M3 ;
        RECT  4.608 0 4.626 0.144 ;
    END
  END di[2]
  PIN di[300]
    DIRECTION INPUT ;
    USE SIGNAL ;
    PORT
      LAYER M3 ;
        RECT  41.4 0 41.418 0.144 ;
    END
  END di[300]
  PIN di[301]
    DIRECTION INPUT ;
    USE SIGNAL ;
    PORT
      LAYER M5 ;
        RECT  41.52 0 41.544 0.192 ;
    END
  END di[301]
  PIN di[302]
    DIRECTION INPUT ;
    USE SIGNAL ;
    PORT
      LAYER M3 ;
        RECT  41.652 0 41.67 0.144 ;
    END
  END di[302]
  PIN di[303]
    DIRECTION INPUT ;
    USE SIGNAL ;
    PORT
      LAYER M5 ;
        RECT  41.76 0 41.784 0.192 ;
    END
  END di[303]
  PIN di[304]
    DIRECTION INPUT ;
    USE SIGNAL ;
    PORT
      LAYER M3 ;
        RECT  41.904 0 41.922 0.144 ;
    END
  END di[304]
  PIN di[305]
    DIRECTION INPUT ;
    USE SIGNAL ;
    PORT
      LAYER M5 ;
        RECT  42 0 42.024 0.192 ;
    END
  END di[305]
  PIN di[306]
    DIRECTION INPUT ;
    USE SIGNAL ;
    PORT
      LAYER M3 ;
        RECT  42.156 0 42.174 0.144 ;
    END
  END di[306]
  PIN di[307]
    DIRECTION INPUT ;
    USE SIGNAL ;
    PORT
      LAYER M5 ;
        RECT  42.24 0 42.264 0.192 ;
    END
  END di[307]
  PIN di[308]
    DIRECTION INPUT ;
    USE SIGNAL ;
    PORT
      LAYER M3 ;
        RECT  42.372 0 42.39 0.144 ;
    END
  END di[308]
  PIN di[309]
    DIRECTION INPUT ;
    USE SIGNAL ;
    PORT
      LAYER M5 ;
        RECT  42.528 0 42.552 0.192 ;
    END
  END di[309]
  PIN di[30]
    DIRECTION INPUT ;
    USE SIGNAL ;
    PORT
      LAYER M3 ;
        RECT  8.064 0 8.082 0.144 ;
    END
  END di[30]
  PIN di[310]
    DIRECTION INPUT ;
    USE SIGNAL ;
    PORT
      LAYER M3 ;
        RECT  42.624 0 42.642 0.144 ;
    END
  END di[310]
  PIN di[311]
    DIRECTION INPUT ;
    USE SIGNAL ;
    PORT
      LAYER M5 ;
        RECT  42.768 0 42.792 0.192 ;
    END
  END di[311]
  PIN di[312]
    DIRECTION INPUT ;
    USE SIGNAL ;
    PORT
      LAYER M3 ;
        RECT  42.876 0 42.894 0.144 ;
    END
  END di[312]
  PIN di[313]
    DIRECTION INPUT ;
    USE SIGNAL ;
    PORT
      LAYER M5 ;
        RECT  43.008 0 43.032 0.192 ;
    END
  END di[313]
  PIN di[314]
    DIRECTION INPUT ;
    USE SIGNAL ;
    PORT
      LAYER M3 ;
        RECT  43.128 0 43.146 0.144 ;
    END
  END di[314]
  PIN di[315]
    DIRECTION INPUT ;
    USE SIGNAL ;
    PORT
      LAYER M5 ;
        RECT  43.248 0 43.272 0.192 ;
    END
  END di[315]
  PIN di[316]
    DIRECTION INPUT ;
    USE SIGNAL ;
    PORT
      LAYER M3 ;
        RECT  43.38 0 43.398 0.144 ;
    END
  END di[316]
  PIN di[317]
    DIRECTION INPUT ;
    USE SIGNAL ;
    PORT
      LAYER M5 ;
        RECT  43.488 0 43.512 0.192 ;
    END
  END di[317]
  PIN di[318]
    DIRECTION INPUT ;
    USE SIGNAL ;
    PORT
      LAYER M3 ;
        RECT  43.632 0 43.65 0.144 ;
    END
  END di[318]
  PIN di[319]
    DIRECTION INPUT ;
    USE SIGNAL ;
    PORT
      LAYER M5 ;
        RECT  43.728 0 43.752 0.192 ;
    END
  END di[319]
  PIN di[31]
    DIRECTION INPUT ;
    USE SIGNAL ;
    PORT
      LAYER M5 ;
        RECT  8.208 0 8.232 0.192 ;
    END
  END di[31]
  PIN di[320]
    DIRECTION INPUT ;
    USE SIGNAL ;
    PORT
      LAYER M3 ;
        RECT  43.884 0 43.902 0.144 ;
    END
  END di[320]
  PIN di[321]
    DIRECTION INPUT ;
    USE SIGNAL ;
    PORT
      LAYER M5 ;
        RECT  43.968 0 43.992 0.192 ;
    END
  END di[321]
  PIN di[322]
    DIRECTION INPUT ;
    USE SIGNAL ;
    PORT
      LAYER M3 ;
        RECT  44.1 0 44.118 0.144 ;
    END
  END di[322]
  PIN di[323]
    DIRECTION INPUT ;
    USE SIGNAL ;
    PORT
      LAYER M5 ;
        RECT  44.256 0 44.28 0.192 ;
    END
  END di[323]
  PIN di[324]
    DIRECTION INPUT ;
    USE SIGNAL ;
    PORT
      LAYER M3 ;
        RECT  44.352 0 44.37 0.144 ;
    END
  END di[324]
  PIN di[325]
    DIRECTION INPUT ;
    USE SIGNAL ;
    PORT
      LAYER M5 ;
        RECT  44.496 0 44.52 0.192 ;
    END
  END di[325]
  PIN di[326]
    DIRECTION INPUT ;
    USE SIGNAL ;
    PORT
      LAYER M3 ;
        RECT  44.604 0 44.622 0.144 ;
    END
  END di[326]
  PIN di[327]
    DIRECTION INPUT ;
    USE SIGNAL ;
    PORT
      LAYER M5 ;
        RECT  44.736 0 44.76 0.192 ;
    END
  END di[327]
  PIN di[328]
    DIRECTION INPUT ;
    USE SIGNAL ;
    PORT
      LAYER M3 ;
        RECT  44.856 0 44.874 0.144 ;
    END
  END di[328]
  PIN di[329]
    DIRECTION INPUT ;
    USE SIGNAL ;
    PORT
      LAYER M5 ;
        RECT  44.976 0 45 0.192 ;
    END
  END di[329]
  PIN di[32]
    DIRECTION INPUT ;
    USE SIGNAL ;
    PORT
      LAYER M3 ;
        RECT  8.316 0 8.334 0.144 ;
    END
  END di[32]
  PIN di[330]
    DIRECTION INPUT ;
    USE SIGNAL ;
    PORT
      LAYER M3 ;
        RECT  45.108 0 45.126 0.144 ;
    END
  END di[330]
  PIN di[331]
    DIRECTION INPUT ;
    USE SIGNAL ;
    PORT
      LAYER M5 ;
        RECT  45.216 0 45.24 0.192 ;
    END
  END di[331]
  PIN di[332]
    DIRECTION INPUT ;
    USE SIGNAL ;
    PORT
      LAYER M3 ;
        RECT  45.36 0 45.378 0.144 ;
    END
  END di[332]
  PIN di[333]
    DIRECTION INPUT ;
    USE SIGNAL ;
    PORT
      LAYER M5 ;
        RECT  45.456 0 45.48 0.192 ;
    END
  END di[333]
  PIN di[334]
    DIRECTION INPUT ;
    USE SIGNAL ;
    PORT
      LAYER M3 ;
        RECT  45.612 0 45.63 0.144 ;
    END
  END di[334]
  PIN di[335]
    DIRECTION INPUT ;
    USE SIGNAL ;
    PORT
      LAYER M5 ;
        RECT  45.696 0 45.72 0.192 ;
    END
  END di[335]
  PIN di[336]
    DIRECTION INPUT ;
    USE SIGNAL ;
    PORT
      LAYER M3 ;
        RECT  45.828 0 45.846 0.144 ;
    END
  END di[336]
  PIN di[337]
    DIRECTION INPUT ;
    USE SIGNAL ;
    PORT
      LAYER M5 ;
        RECT  45.984 0 46.008 0.192 ;
    END
  END di[337]
  PIN di[338]
    DIRECTION INPUT ;
    USE SIGNAL ;
    PORT
      LAYER M3 ;
        RECT  46.08 0 46.098 0.144 ;
    END
  END di[338]
  PIN di[339]
    DIRECTION INPUT ;
    USE SIGNAL ;
    PORT
      LAYER M5 ;
        RECT  46.224 0 46.248 0.192 ;
    END
  END di[339]
  PIN di[33]
    DIRECTION INPUT ;
    USE SIGNAL ;
    PORT
      LAYER M5 ;
        RECT  8.448 0 8.472 0.192 ;
    END
  END di[33]
  PIN di[340]
    DIRECTION INPUT ;
    USE SIGNAL ;
    PORT
      LAYER M3 ;
        RECT  46.332 0 46.35 0.144 ;
    END
  END di[340]
  PIN di[341]
    DIRECTION INPUT ;
    USE SIGNAL ;
    PORT
      LAYER M5 ;
        RECT  46.464 0 46.488 0.192 ;
    END
  END di[341]
  PIN di[342]
    DIRECTION INPUT ;
    USE SIGNAL ;
    PORT
      LAYER M3 ;
        RECT  46.584 0 46.602 0.144 ;
    END
  END di[342]
  PIN di[343]
    DIRECTION INPUT ;
    USE SIGNAL ;
    PORT
      LAYER M5 ;
        RECT  46.704 0 46.728 0.192 ;
    END
  END di[343]
  PIN di[344]
    DIRECTION INPUT ;
    USE SIGNAL ;
    PORT
      LAYER M3 ;
        RECT  46.836 0 46.854 0.144 ;
    END
  END di[344]
  PIN di[345]
    DIRECTION INPUT ;
    USE SIGNAL ;
    PORT
      LAYER M5 ;
        RECT  46.944 0 46.968 0.192 ;
    END
  END di[345]
  PIN di[346]
    DIRECTION INPUT ;
    USE SIGNAL ;
    PORT
      LAYER M3 ;
        RECT  47.088 0 47.106 0.144 ;
    END
  END di[346]
  PIN di[347]
    DIRECTION INPUT ;
    USE SIGNAL ;
    PORT
      LAYER M5 ;
        RECT  47.184 0 47.208 0.192 ;
    END
  END di[347]
  PIN di[348]
    DIRECTION INPUT ;
    USE SIGNAL ;
    PORT
      LAYER M3 ;
        RECT  47.34 0 47.358 0.144 ;
    END
  END di[348]
  PIN di[349]
    DIRECTION INPUT ;
    USE SIGNAL ;
    PORT
      LAYER M5 ;
        RECT  47.424 0 47.448 0.192 ;
    END
  END di[349]
  PIN di[34]
    DIRECTION INPUT ;
    USE SIGNAL ;
    PORT
      LAYER M3 ;
        RECT  8.568 0 8.586 0.144 ;
    END
  END di[34]
  PIN di[350]
    DIRECTION INPUT ;
    USE SIGNAL ;
    PORT
      LAYER M3 ;
        RECT  47.556 0 47.574 0.144 ;
    END
  END di[350]
  PIN di[351]
    DIRECTION INPUT ;
    USE SIGNAL ;
    PORT
      LAYER M5 ;
        RECT  47.712 0 47.736 0.192 ;
    END
  END di[351]
  PIN di[352]
    DIRECTION INPUT ;
    USE SIGNAL ;
    PORT
      LAYER M3 ;
        RECT  47.808 0 47.826 0.144 ;
    END
  END di[352]
  PIN di[353]
    DIRECTION INPUT ;
    USE SIGNAL ;
    PORT
      LAYER M5 ;
        RECT  47.952 0 47.976 0.192 ;
    END
  END di[353]
  PIN di[354]
    DIRECTION INPUT ;
    USE SIGNAL ;
    PORT
      LAYER M3 ;
        RECT  48.06 0 48.078 0.144 ;
    END
  END di[354]
  PIN di[355]
    DIRECTION INPUT ;
    USE SIGNAL ;
    PORT
      LAYER M5 ;
        RECT  48.192 0 48.216 0.192 ;
    END
  END di[355]
  PIN di[356]
    DIRECTION INPUT ;
    USE SIGNAL ;
    PORT
      LAYER M3 ;
        RECT  48.312 0 48.33 0.144 ;
    END
  END di[356]
  PIN di[357]
    DIRECTION INPUT ;
    USE SIGNAL ;
    PORT
      LAYER M5 ;
        RECT  48.432 0 48.456 0.192 ;
    END
  END di[357]
  PIN di[358]
    DIRECTION INPUT ;
    USE SIGNAL ;
    PORT
      LAYER M3 ;
        RECT  48.564 0 48.582 0.144 ;
    END
  END di[358]
  PIN di[359]
    DIRECTION INPUT ;
    USE SIGNAL ;
    PORT
      LAYER M5 ;
        RECT  48.672 0 48.696 0.192 ;
    END
  END di[359]
  PIN di[35]
    DIRECTION INPUT ;
    USE SIGNAL ;
    PORT
      LAYER M5 ;
        RECT  8.688 0 8.712 0.192 ;
    END
  END di[35]
  PIN di[360]
    DIRECTION INPUT ;
    USE SIGNAL ;
    PORT
      LAYER M3 ;
        RECT  48.816 0 48.834 0.144 ;
    END
  END di[360]
  PIN di[361]
    DIRECTION INPUT ;
    USE SIGNAL ;
    PORT
      LAYER M5 ;
        RECT  48.912 0 48.936 0.192 ;
    END
  END di[361]
  PIN di[362]
    DIRECTION INPUT ;
    USE SIGNAL ;
    PORT
      LAYER M3 ;
        RECT  49.068 0 49.086 0.144 ;
    END
  END di[362]
  PIN di[363]
    DIRECTION INPUT ;
    USE SIGNAL ;
    PORT
      LAYER M5 ;
        RECT  49.152 0 49.176 0.192 ;
    END
  END di[363]
  PIN di[364]
    DIRECTION INPUT ;
    USE SIGNAL ;
    PORT
      LAYER M3 ;
        RECT  49.284 0 49.302 0.144 ;
    END
  END di[364]
  PIN di[365]
    DIRECTION INPUT ;
    USE SIGNAL ;
    PORT
      LAYER M5 ;
        RECT  49.44 0 49.464 0.192 ;
    END
  END di[365]
  PIN di[366]
    DIRECTION INPUT ;
    USE SIGNAL ;
    PORT
      LAYER M3 ;
        RECT  49.536 0 49.554 0.144 ;
    END
  END di[366]
  PIN di[367]
    DIRECTION INPUT ;
    USE SIGNAL ;
    PORT
      LAYER M5 ;
        RECT  49.68 0 49.704 0.192 ;
    END
  END di[367]
  PIN di[368]
    DIRECTION INPUT ;
    USE SIGNAL ;
    PORT
      LAYER M3 ;
        RECT  49.788 0 49.806 0.144 ;
    END
  END di[368]
  PIN di[369]
    DIRECTION INPUT ;
    USE SIGNAL ;
    PORT
      LAYER M5 ;
        RECT  49.92 0 49.944 0.192 ;
    END
  END di[369]
  PIN di[36]
    DIRECTION INPUT ;
    USE SIGNAL ;
    PORT
      LAYER M3 ;
        RECT  8.82 0 8.838 0.144 ;
    END
  END di[36]
  PIN di[370]
    DIRECTION INPUT ;
    USE SIGNAL ;
    PORT
      LAYER M3 ;
        RECT  50.04 0 50.058 0.144 ;
    END
  END di[370]
  PIN di[371]
    DIRECTION INPUT ;
    USE SIGNAL ;
    PORT
      LAYER M5 ;
        RECT  50.16 0 50.184 0.192 ;
    END
  END di[371]
  PIN di[372]
    DIRECTION INPUT ;
    USE SIGNAL ;
    PORT
      LAYER M3 ;
        RECT  50.292 0 50.31 0.144 ;
    END
  END di[372]
  PIN di[373]
    DIRECTION INPUT ;
    USE SIGNAL ;
    PORT
      LAYER M5 ;
        RECT  50.4 0 50.424 0.192 ;
    END
  END di[373]
  PIN di[374]
    DIRECTION INPUT ;
    USE SIGNAL ;
    PORT
      LAYER M3 ;
        RECT  50.544 0 50.562 0.144 ;
    END
  END di[374]
  PIN di[375]
    DIRECTION INPUT ;
    USE SIGNAL ;
    PORT
      LAYER M5 ;
        RECT  50.64 0 50.664 0.192 ;
    END
  END di[375]
  PIN di[376]
    DIRECTION INPUT ;
    USE SIGNAL ;
    PORT
      LAYER M3 ;
        RECT  50.796 0 50.814 0.144 ;
    END
  END di[376]
  PIN di[377]
    DIRECTION INPUT ;
    USE SIGNAL ;
    PORT
      LAYER M5 ;
        RECT  50.88 0 50.904 0.192 ;
    END
  END di[377]
  PIN di[378]
    DIRECTION INPUT ;
    USE SIGNAL ;
    PORT
      LAYER M3 ;
        RECT  51.012 0 51.03 0.144 ;
    END
  END di[378]
  PIN di[379]
    DIRECTION INPUT ;
    USE SIGNAL ;
    PORT
      LAYER M5 ;
        RECT  51.168 0 51.192 0.192 ;
    END
  END di[379]
  PIN di[37]
    DIRECTION INPUT ;
    USE SIGNAL ;
    PORT
      LAYER M5 ;
        RECT  8.928 0 8.952 0.192 ;
    END
  END di[37]
  PIN di[380]
    DIRECTION INPUT ;
    USE SIGNAL ;
    PORT
      LAYER M3 ;
        RECT  51.264 0 51.282 0.144 ;
    END
  END di[380]
  PIN di[381]
    DIRECTION INPUT ;
    USE SIGNAL ;
    PORT
      LAYER M5 ;
        RECT  51.408 0 51.432 0.192 ;
    END
  END di[381]
  PIN di[382]
    DIRECTION INPUT ;
    USE SIGNAL ;
    PORT
      LAYER M3 ;
        RECT  51.516 0 51.534 0.144 ;
    END
  END di[382]
  PIN di[383]
    DIRECTION INPUT ;
    USE SIGNAL ;
    PORT
      LAYER M5 ;
        RECT  51.648 0 51.672 0.192 ;
    END
  END di[383]
  PIN di[384]
    DIRECTION INPUT ;
    USE SIGNAL ;
    PORT
      LAYER M3 ;
        RECT  51.768 0 51.786 0.144 ;
    END
  END di[384]
  PIN di[385]
    DIRECTION INPUT ;
    USE SIGNAL ;
    PORT
      LAYER M5 ;
        RECT  51.888 0 51.912 0.192 ;
    END
  END di[385]
  PIN di[386]
    DIRECTION INPUT ;
    USE SIGNAL ;
    PORT
      LAYER M3 ;
        RECT  52.02 0 52.038 0.144 ;
    END
  END di[386]
  PIN di[387]
    DIRECTION INPUT ;
    USE SIGNAL ;
    PORT
      LAYER M5 ;
        RECT  52.128 0 52.152 0.192 ;
    END
  END di[387]
  PIN di[388]
    DIRECTION INPUT ;
    USE SIGNAL ;
    PORT
      LAYER M3 ;
        RECT  52.272 0 52.29 0.144 ;
    END
  END di[388]
  PIN di[389]
    DIRECTION INPUT ;
    USE SIGNAL ;
    PORT
      LAYER M5 ;
        RECT  52.368 0 52.392 0.192 ;
    END
  END di[389]
  PIN di[38]
    DIRECTION INPUT ;
    USE SIGNAL ;
    PORT
      LAYER M3 ;
        RECT  9.072 0 9.09 0.144 ;
    END
  END di[38]
  PIN di[390]
    DIRECTION INPUT ;
    USE SIGNAL ;
    PORT
      LAYER M3 ;
        RECT  52.524 0 52.542 0.144 ;
    END
  END di[390]
  PIN di[391]
    DIRECTION INPUT ;
    USE SIGNAL ;
    PORT
      LAYER M5 ;
        RECT  52.608 0 52.632 0.192 ;
    END
  END di[391]
  PIN di[392]
    DIRECTION INPUT ;
    USE SIGNAL ;
    PORT
      LAYER M3 ;
        RECT  52.74 0 52.758 0.144 ;
    END
  END di[392]
  PIN di[393]
    DIRECTION INPUT ;
    USE SIGNAL ;
    PORT
      LAYER M5 ;
        RECT  52.896 0 52.92 0.192 ;
    END
  END di[393]
  PIN di[394]
    DIRECTION INPUT ;
    USE SIGNAL ;
    PORT
      LAYER M3 ;
        RECT  52.992 0 53.01 0.144 ;
    END
  END di[394]
  PIN di[395]
    DIRECTION INPUT ;
    USE SIGNAL ;
    PORT
      LAYER M5 ;
        RECT  53.136 0 53.16 0.192 ;
    END
  END di[395]
  PIN di[396]
    DIRECTION INPUT ;
    USE SIGNAL ;
    PORT
      LAYER M3 ;
        RECT  53.244 0 53.262 0.144 ;
    END
  END di[396]
  PIN di[397]
    DIRECTION INPUT ;
    USE SIGNAL ;
    PORT
      LAYER M5 ;
        RECT  53.376 0 53.4 0.192 ;
    END
  END di[397]
  PIN di[398]
    DIRECTION INPUT ;
    USE SIGNAL ;
    PORT
      LAYER M3 ;
        RECT  53.496 0 53.514 0.144 ;
    END
  END di[398]
  PIN di[399]
    DIRECTION INPUT ;
    USE SIGNAL ;
    PORT
      LAYER M5 ;
        RECT  53.616 0 53.64 0.192 ;
    END
  END di[399]
  PIN di[39]
    DIRECTION INPUT ;
    USE SIGNAL ;
    PORT
      LAYER M5 ;
        RECT  9.168 0 9.192 0.192 ;
    END
  END di[39]
  PIN di[3]
    DIRECTION INPUT ;
    USE SIGNAL ;
    PORT
      LAYER M5 ;
        RECT  4.752 0 4.776 0.192 ;
    END
  END di[3]
  PIN di[400]
    DIRECTION INPUT ;
    USE SIGNAL ;
    PORT
      LAYER M3 ;
        RECT  53.748 0 53.766 0.144 ;
    END
  END di[400]
  PIN di[401]
    DIRECTION INPUT ;
    USE SIGNAL ;
    PORT
      LAYER M5 ;
        RECT  53.856 0 53.88 0.192 ;
    END
  END di[401]
  PIN di[402]
    DIRECTION INPUT ;
    USE SIGNAL ;
    PORT
      LAYER M3 ;
        RECT  54 0 54.018 0.144 ;
    END
  END di[402]
  PIN di[403]
    DIRECTION INPUT ;
    USE SIGNAL ;
    PORT
      LAYER M5 ;
        RECT  54.096 0 54.12 0.192 ;
    END
  END di[403]
  PIN di[404]
    DIRECTION INPUT ;
    USE SIGNAL ;
    PORT
      LAYER M3 ;
        RECT  54.252 0 54.27 0.144 ;
    END
  END di[404]
  PIN di[405]
    DIRECTION INPUT ;
    USE SIGNAL ;
    PORT
      LAYER M5 ;
        RECT  54.336 0 54.36 0.192 ;
    END
  END di[405]
  PIN di[406]
    DIRECTION INPUT ;
    USE SIGNAL ;
    PORT
      LAYER M3 ;
        RECT  54.468 0 54.486 0.144 ;
    END
  END di[406]
  PIN di[407]
    DIRECTION INPUT ;
    USE SIGNAL ;
    PORT
      LAYER M5 ;
        RECT  54.624 0 54.648 0.192 ;
    END
  END di[407]
  PIN di[408]
    DIRECTION INPUT ;
    USE SIGNAL ;
    PORT
      LAYER M3 ;
        RECT  54.72 0 54.738 0.144 ;
    END
  END di[408]
  PIN di[409]
    DIRECTION INPUT ;
    USE SIGNAL ;
    PORT
      LAYER M5 ;
        RECT  54.864 0 54.888 0.192 ;
    END
  END di[409]
  PIN di[40]
    DIRECTION INPUT ;
    USE SIGNAL ;
    PORT
      LAYER M3 ;
        RECT  9.324 0 9.342 0.144 ;
    END
  END di[40]
  PIN di[410]
    DIRECTION INPUT ;
    USE SIGNAL ;
    PORT
      LAYER M3 ;
        RECT  54.972 0 54.99 0.144 ;
    END
  END di[410]
  PIN di[411]
    DIRECTION INPUT ;
    USE SIGNAL ;
    PORT
      LAYER M5 ;
        RECT  55.104 0 55.128 0.192 ;
    END
  END di[411]
  PIN di[412]
    DIRECTION INPUT ;
    USE SIGNAL ;
    PORT
      LAYER M3 ;
        RECT  55.224 0 55.242 0.144 ;
    END
  END di[412]
  PIN di[413]
    DIRECTION INPUT ;
    USE SIGNAL ;
    PORT
      LAYER M5 ;
        RECT  55.344 0 55.368 0.192 ;
    END
  END di[413]
  PIN di[414]
    DIRECTION INPUT ;
    USE SIGNAL ;
    PORT
      LAYER M3 ;
        RECT  55.476 0 55.494 0.144 ;
    END
  END di[414]
  PIN di[415]
    DIRECTION INPUT ;
    USE SIGNAL ;
    PORT
      LAYER M5 ;
        RECT  55.584 0 55.608 0.192 ;
    END
  END di[415]
  PIN di[416]
    DIRECTION INPUT ;
    USE SIGNAL ;
    PORT
      LAYER M3 ;
        RECT  55.728 0 55.746 0.144 ;
    END
  END di[416]
  PIN di[417]
    DIRECTION INPUT ;
    USE SIGNAL ;
    PORT
      LAYER M5 ;
        RECT  55.824 0 55.848 0.192 ;
    END
  END di[417]
  PIN di[418]
    DIRECTION INPUT ;
    USE SIGNAL ;
    PORT
      LAYER M3 ;
        RECT  55.98 0 55.998 0.144 ;
    END
  END di[418]
  PIN di[419]
    DIRECTION INPUT ;
    USE SIGNAL ;
    PORT
      LAYER M5 ;
        RECT  56.064 0 56.088 0.192 ;
    END
  END di[419]
  PIN di[41]
    DIRECTION INPUT ;
    USE SIGNAL ;
    PORT
      LAYER M5 ;
        RECT  9.408 0 9.432 0.192 ;
    END
  END di[41]
  PIN di[420]
    DIRECTION INPUT ;
    USE SIGNAL ;
    PORT
      LAYER M3 ;
        RECT  56.196 0 56.214 0.144 ;
    END
  END di[420]
  PIN di[421]
    DIRECTION INPUT ;
    USE SIGNAL ;
    PORT
      LAYER M5 ;
        RECT  56.352 0 56.376 0.192 ;
    END
  END di[421]
  PIN di[422]
    DIRECTION INPUT ;
    USE SIGNAL ;
    PORT
      LAYER M3 ;
        RECT  56.448 0 56.466 0.144 ;
    END
  END di[422]
  PIN di[423]
    DIRECTION INPUT ;
    USE SIGNAL ;
    PORT
      LAYER M5 ;
        RECT  56.592 0 56.616 0.192 ;
    END
  END di[423]
  PIN di[424]
    DIRECTION INPUT ;
    USE SIGNAL ;
    PORT
      LAYER M3 ;
        RECT  56.7 0 56.718 0.144 ;
    END
  END di[424]
  PIN di[425]
    DIRECTION INPUT ;
    USE SIGNAL ;
    PORT
      LAYER M5 ;
        RECT  56.832 0 56.856 0.192 ;
    END
  END di[425]
  PIN di[426]
    DIRECTION INPUT ;
    USE SIGNAL ;
    PORT
      LAYER M3 ;
        RECT  56.952 0 56.97 0.144 ;
    END
  END di[426]
  PIN di[427]
    DIRECTION INPUT ;
    USE SIGNAL ;
    PORT
      LAYER M5 ;
        RECT  57.072 0 57.096 0.192 ;
    END
  END di[427]
  PIN di[428]
    DIRECTION INPUT ;
    USE SIGNAL ;
    PORT
      LAYER M3 ;
        RECT  57.204 0 57.222 0.144 ;
    END
  END di[428]
  PIN di[429]
    DIRECTION INPUT ;
    USE SIGNAL ;
    PORT
      LAYER M5 ;
        RECT  57.312 0 57.336 0.192 ;
    END
  END di[429]
  PIN di[42]
    DIRECTION INPUT ;
    USE SIGNAL ;
    PORT
      LAYER M3 ;
        RECT  9.54 0 9.558 0.144 ;
    END
  END di[42]
  PIN di[430]
    DIRECTION INPUT ;
    USE SIGNAL ;
    PORT
      LAYER M3 ;
        RECT  57.456 0 57.474 0.144 ;
    END
  END di[430]
  PIN di[431]
    DIRECTION INPUT ;
    USE SIGNAL ;
    PORT
      LAYER M5 ;
        RECT  57.552 0 57.576 0.192 ;
    END
  END di[431]
  PIN di[432]
    DIRECTION INPUT ;
    USE SIGNAL ;
    PORT
      LAYER M3 ;
        RECT  57.708 0 57.726 0.144 ;
    END
  END di[432]
  PIN di[433]
    DIRECTION INPUT ;
    USE SIGNAL ;
    PORT
      LAYER M5 ;
        RECT  57.792 0 57.816 0.192 ;
    END
  END di[433]
  PIN di[434]
    DIRECTION INPUT ;
    USE SIGNAL ;
    PORT
      LAYER M3 ;
        RECT  57.924 0 57.942 0.144 ;
    END
  END di[434]
  PIN di[435]
    DIRECTION INPUT ;
    USE SIGNAL ;
    PORT
      LAYER M5 ;
        RECT  58.08 0 58.104 0.192 ;
    END
  END di[435]
  PIN di[436]
    DIRECTION INPUT ;
    USE SIGNAL ;
    PORT
      LAYER M3 ;
        RECT  58.176 0 58.194 0.144 ;
    END
  END di[436]
  PIN di[437]
    DIRECTION INPUT ;
    USE SIGNAL ;
    PORT
      LAYER M5 ;
        RECT  58.32 0 58.344 0.192 ;
    END
  END di[437]
  PIN di[438]
    DIRECTION INPUT ;
    USE SIGNAL ;
    PORT
      LAYER M3 ;
        RECT  58.428 0 58.446 0.144 ;
    END
  END di[438]
  PIN di[439]
    DIRECTION INPUT ;
    USE SIGNAL ;
    PORT
      LAYER M5 ;
        RECT  58.56 0 58.584 0.192 ;
    END
  END di[439]
  PIN di[43]
    DIRECTION INPUT ;
    USE SIGNAL ;
    PORT
      LAYER M5 ;
        RECT  9.696 0 9.72 0.192 ;
    END
  END di[43]
  PIN di[440]
    DIRECTION INPUT ;
    USE SIGNAL ;
    PORT
      LAYER M3 ;
        RECT  58.68 0 58.698 0.144 ;
    END
  END di[440]
  PIN di[441]
    DIRECTION INPUT ;
    USE SIGNAL ;
    PORT
      LAYER M5 ;
        RECT  58.8 0 58.824 0.192 ;
    END
  END di[441]
  PIN di[442]
    DIRECTION INPUT ;
    USE SIGNAL ;
    PORT
      LAYER M3 ;
        RECT  58.932 0 58.95 0.144 ;
    END
  END di[442]
  PIN di[443]
    DIRECTION INPUT ;
    USE SIGNAL ;
    PORT
      LAYER M5 ;
        RECT  59.04 0 59.064 0.192 ;
    END
  END di[443]
  PIN di[444]
    DIRECTION INPUT ;
    USE SIGNAL ;
    PORT
      LAYER M3 ;
        RECT  59.184 0 59.202 0.144 ;
    END
  END di[444]
  PIN di[445]
    DIRECTION INPUT ;
    USE SIGNAL ;
    PORT
      LAYER M5 ;
        RECT  59.28 0 59.304 0.192 ;
    END
  END di[445]
  PIN di[446]
    DIRECTION INPUT ;
    USE SIGNAL ;
    PORT
      LAYER M3 ;
        RECT  59.436 0 59.454 0.144 ;
    END
  END di[446]
  PIN di[447]
    DIRECTION INPUT ;
    USE SIGNAL ;
    PORT
      LAYER M5 ;
        RECT  59.52 0 59.544 0.192 ;
    END
  END di[447]
  PIN di[448]
    DIRECTION INPUT ;
    USE SIGNAL ;
    PORT
      LAYER M3 ;
        RECT  59.652 0 59.67 0.144 ;
    END
  END di[448]
  PIN di[449]
    DIRECTION INPUT ;
    USE SIGNAL ;
    PORT
      LAYER M5 ;
        RECT  59.808 0 59.832 0.192 ;
    END
  END di[449]
  PIN di[44]
    DIRECTION INPUT ;
    USE SIGNAL ;
    PORT
      LAYER M3 ;
        RECT  9.792 0 9.81 0.144 ;
    END
  END di[44]
  PIN di[450]
    DIRECTION INPUT ;
    USE SIGNAL ;
    PORT
      LAYER M3 ;
        RECT  59.904 0 59.922 0.144 ;
    END
  END di[450]
  PIN di[451]
    DIRECTION INPUT ;
    USE SIGNAL ;
    PORT
      LAYER M5 ;
        RECT  60.048 0 60.072 0.192 ;
    END
  END di[451]
  PIN di[452]
    DIRECTION INPUT ;
    USE SIGNAL ;
    PORT
      LAYER M3 ;
        RECT  60.156 0 60.174 0.144 ;
    END
  END di[452]
  PIN di[453]
    DIRECTION INPUT ;
    USE SIGNAL ;
    PORT
      LAYER M5 ;
        RECT  60.288 0 60.312 0.192 ;
    END
  END di[453]
  PIN di[454]
    DIRECTION INPUT ;
    USE SIGNAL ;
    PORT
      LAYER M3 ;
        RECT  60.408 0 60.426 0.144 ;
    END
  END di[454]
  PIN di[455]
    DIRECTION INPUT ;
    USE SIGNAL ;
    PORT
      LAYER M5 ;
        RECT  60.528 0 60.552 0.192 ;
    END
  END di[455]
  PIN di[456]
    DIRECTION INPUT ;
    USE SIGNAL ;
    PORT
      LAYER M3 ;
        RECT  60.66 0 60.678 0.144 ;
    END
  END di[456]
  PIN di[457]
    DIRECTION INPUT ;
    USE SIGNAL ;
    PORT
      LAYER M5 ;
        RECT  60.768 0 60.792 0.192 ;
    END
  END di[457]
  PIN di[458]
    DIRECTION INPUT ;
    USE SIGNAL ;
    PORT
      LAYER M3 ;
        RECT  60.912 0 60.93 0.144 ;
    END
  END di[458]
  PIN di[459]
    DIRECTION INPUT ;
    USE SIGNAL ;
    PORT
      LAYER M5 ;
        RECT  61.008 0 61.032 0.192 ;
    END
  END di[459]
  PIN di[45]
    DIRECTION INPUT ;
    USE SIGNAL ;
    PORT
      LAYER M5 ;
        RECT  9.936 0 9.96 0.192 ;
    END
  END di[45]
  PIN di[460]
    DIRECTION INPUT ;
    USE SIGNAL ;
    PORT
      LAYER M3 ;
        RECT  61.164 0 61.182 0.144 ;
    END
  END di[460]
  PIN di[461]
    DIRECTION INPUT ;
    USE SIGNAL ;
    PORT
      LAYER M5 ;
        RECT  61.248 0 61.272 0.192 ;
    END
  END di[461]
  PIN di[462]
    DIRECTION INPUT ;
    USE SIGNAL ;
    PORT
      LAYER M3 ;
        RECT  61.38 0 61.398 0.144 ;
    END
  END di[462]
  PIN di[463]
    DIRECTION INPUT ;
    USE SIGNAL ;
    PORT
      LAYER M5 ;
        RECT  61.536 0 61.56 0.192 ;
    END
  END di[463]
  PIN di[464]
    DIRECTION INPUT ;
    USE SIGNAL ;
    PORT
      LAYER M3 ;
        RECT  61.632 0 61.65 0.144 ;
    END
  END di[464]
  PIN di[465]
    DIRECTION INPUT ;
    USE SIGNAL ;
    PORT
      LAYER M5 ;
        RECT  61.776 0 61.8 0.192 ;
    END
  END di[465]
  PIN di[466]
    DIRECTION INPUT ;
    USE SIGNAL ;
    PORT
      LAYER M3 ;
        RECT  61.884 0 61.902 0.144 ;
    END
  END di[466]
  PIN di[467]
    DIRECTION INPUT ;
    USE SIGNAL ;
    PORT
      LAYER M5 ;
        RECT  62.016 0 62.04 0.192 ;
    END
  END di[467]
  PIN di[468]
    DIRECTION INPUT ;
    USE SIGNAL ;
    PORT
      LAYER M3 ;
        RECT  62.136 0 62.154 0.144 ;
    END
  END di[468]
  PIN di[469]
    DIRECTION INPUT ;
    USE SIGNAL ;
    PORT
      LAYER M5 ;
        RECT  62.256 0 62.28 0.192 ;
    END
  END di[469]
  PIN di[46]
    DIRECTION INPUT ;
    USE SIGNAL ;
    PORT
      LAYER M3 ;
        RECT  10.044 0 10.062 0.144 ;
    END
  END di[46]
  PIN di[470]
    DIRECTION INPUT ;
    USE SIGNAL ;
    PORT
      LAYER M3 ;
        RECT  62.388 0 62.406 0.144 ;
    END
  END di[470]
  PIN di[471]
    DIRECTION INPUT ;
    USE SIGNAL ;
    PORT
      LAYER M5 ;
        RECT  62.496 0 62.52 0.192 ;
    END
  END di[471]
  PIN di[472]
    DIRECTION INPUT ;
    USE SIGNAL ;
    PORT
      LAYER M3 ;
        RECT  62.64 0 62.658 0.144 ;
    END
  END di[472]
  PIN di[473]
    DIRECTION INPUT ;
    USE SIGNAL ;
    PORT
      LAYER M5 ;
        RECT  62.736 0 62.76 0.192 ;
    END
  END di[473]
  PIN di[474]
    DIRECTION INPUT ;
    USE SIGNAL ;
    PORT
      LAYER M3 ;
        RECT  62.892 0 62.91 0.144 ;
    END
  END di[474]
  PIN di[475]
    DIRECTION INPUT ;
    USE SIGNAL ;
    PORT
      LAYER M5 ;
        RECT  62.976 0 63 0.192 ;
    END
  END di[475]
  PIN di[476]
    DIRECTION INPUT ;
    USE SIGNAL ;
    PORT
      LAYER M3 ;
        RECT  63.108 0 63.126 0.144 ;
    END
  END di[476]
  PIN di[477]
    DIRECTION INPUT ;
    USE SIGNAL ;
    PORT
      LAYER M5 ;
        RECT  63.264 0 63.288 0.192 ;
    END
  END di[477]
  PIN di[478]
    DIRECTION INPUT ;
    USE SIGNAL ;
    PORT
      LAYER M3 ;
        RECT  63.36 0 63.378 0.144 ;
    END
  END di[478]
  PIN di[479]
    DIRECTION INPUT ;
    USE SIGNAL ;
    PORT
      LAYER M5 ;
        RECT  63.504 0 63.528 0.192 ;
    END
  END di[479]
  PIN di[47]
    DIRECTION INPUT ;
    USE SIGNAL ;
    PORT
      LAYER M5 ;
        RECT  10.176 0 10.2 0.192 ;
    END
  END di[47]
  PIN di[480]
    DIRECTION INPUT ;
    USE SIGNAL ;
    PORT
      LAYER M3 ;
        RECT  63.612 0 63.63 0.144 ;
    END
  END di[480]
  PIN di[481]
    DIRECTION INPUT ;
    USE SIGNAL ;
    PORT
      LAYER M5 ;
        RECT  63.744 0 63.768 0.192 ;
    END
  END di[481]
  PIN di[482]
    DIRECTION INPUT ;
    USE SIGNAL ;
    PORT
      LAYER M3 ;
        RECT  63.864 0 63.882 0.144 ;
    END
  END di[482]
  PIN di[483]
    DIRECTION INPUT ;
    USE SIGNAL ;
    PORT
      LAYER M5 ;
        RECT  63.984 0 64.008 0.192 ;
    END
  END di[483]
  PIN di[484]
    DIRECTION INPUT ;
    USE SIGNAL ;
    PORT
      LAYER M3 ;
        RECT  64.116 0 64.134 0.144 ;
    END
  END di[484]
  PIN di[485]
    DIRECTION INPUT ;
    USE SIGNAL ;
    PORT
      LAYER M5 ;
        RECT  64.224 0 64.248 0.192 ;
    END
  END di[485]
  PIN di[486]
    DIRECTION INPUT ;
    USE SIGNAL ;
    PORT
      LAYER M3 ;
        RECT  64.368 0 64.386 0.144 ;
    END
  END di[486]
  PIN di[487]
    DIRECTION INPUT ;
    USE SIGNAL ;
    PORT
      LAYER M5 ;
        RECT  64.464 0 64.488 0.192 ;
    END
  END di[487]
  PIN di[488]
    DIRECTION INPUT ;
    USE SIGNAL ;
    PORT
      LAYER M3 ;
        RECT  64.62 0 64.638 0.144 ;
    END
  END di[488]
  PIN di[489]
    DIRECTION INPUT ;
    USE SIGNAL ;
    PORT
      LAYER M5 ;
        RECT  64.704 0 64.728 0.192 ;
    END
  END di[489]
  PIN di[48]
    DIRECTION INPUT ;
    USE SIGNAL ;
    PORT
      LAYER M3 ;
        RECT  10.296 0 10.314 0.144 ;
    END
  END di[48]
  PIN di[490]
    DIRECTION INPUT ;
    USE SIGNAL ;
    PORT
      LAYER M3 ;
        RECT  64.836 0 64.854 0.144 ;
    END
  END di[490]
  PIN di[491]
    DIRECTION INPUT ;
    USE SIGNAL ;
    PORT
      LAYER M5 ;
        RECT  64.992 0 65.016 0.192 ;
    END
  END di[491]
  PIN di[492]
    DIRECTION INPUT ;
    USE SIGNAL ;
    PORT
      LAYER M3 ;
        RECT  65.088 0 65.106 0.144 ;
    END
  END di[492]
  PIN di[493]
    DIRECTION INPUT ;
    USE SIGNAL ;
    PORT
      LAYER M5 ;
        RECT  65.232 0 65.256 0.192 ;
    END
  END di[493]
  PIN di[494]
    DIRECTION INPUT ;
    USE SIGNAL ;
    PORT
      LAYER M3 ;
        RECT  65.34 0 65.358 0.144 ;
    END
  END di[494]
  PIN di[495]
    DIRECTION INPUT ;
    USE SIGNAL ;
    PORT
      LAYER M5 ;
        RECT  65.472 0 65.496 0.192 ;
    END
  END di[495]
  PIN di[496]
    DIRECTION INPUT ;
    USE SIGNAL ;
    PORT
      LAYER M3 ;
        RECT  65.592 0 65.61 0.144 ;
    END
  END di[496]
  PIN di[497]
    DIRECTION INPUT ;
    USE SIGNAL ;
    PORT
      LAYER M5 ;
        RECT  65.712 0 65.736 0.192 ;
    END
  END di[497]
  PIN di[498]
    DIRECTION INPUT ;
    USE SIGNAL ;
    PORT
      LAYER M3 ;
        RECT  65.844 0 65.862 0.144 ;
    END
  END di[498]
  PIN di[499]
    DIRECTION INPUT ;
    USE SIGNAL ;
    PORT
      LAYER M5 ;
        RECT  65.952 0 65.976 0.192 ;
    END
  END di[499]
  PIN di[49]
    DIRECTION INPUT ;
    USE SIGNAL ;
    PORT
      LAYER M5 ;
        RECT  10.416 0 10.44 0.192 ;
    END
  END di[49]
  PIN di[4]
    DIRECTION INPUT ;
    USE SIGNAL ;
    PORT
      LAYER M3 ;
        RECT  4.86 0 4.878 0.144 ;
    END
  END di[4]
  PIN di[500]
    DIRECTION INPUT ;
    USE SIGNAL ;
    PORT
      LAYER M3 ;
        RECT  66.096 0 66.114 0.144 ;
    END
  END di[500]
  PIN di[501]
    DIRECTION INPUT ;
    USE SIGNAL ;
    PORT
      LAYER M5 ;
        RECT  66.192 0 66.216 0.192 ;
    END
  END di[501]
  PIN di[502]
    DIRECTION INPUT ;
    USE SIGNAL ;
    PORT
      LAYER M3 ;
        RECT  66.348 0 66.366 0.144 ;
    END
  END di[502]
  PIN di[503]
    DIRECTION INPUT ;
    USE SIGNAL ;
    PORT
      LAYER M5 ;
        RECT  66.432 0 66.456 0.192 ;
    END
  END di[503]
  PIN di[504]
    DIRECTION INPUT ;
    USE SIGNAL ;
    PORT
      LAYER M3 ;
        RECT  66.564 0 66.582 0.144 ;
    END
  END di[504]
  PIN di[505]
    DIRECTION INPUT ;
    USE SIGNAL ;
    PORT
      LAYER M5 ;
        RECT  66.72 0 66.744 0.192 ;
    END
  END di[505]
  PIN di[506]
    DIRECTION INPUT ;
    USE SIGNAL ;
    PORT
      LAYER M3 ;
        RECT  66.816 0 66.834 0.144 ;
    END
  END di[506]
  PIN di[507]
    DIRECTION INPUT ;
    USE SIGNAL ;
    PORT
      LAYER M5 ;
        RECT  66.96 0 66.984 0.192 ;
    END
  END di[507]
  PIN di[508]
    DIRECTION INPUT ;
    USE SIGNAL ;
    PORT
      LAYER M3 ;
        RECT  67.068 0 67.086 0.144 ;
    END
  END di[508]
  PIN di[509]
    DIRECTION INPUT ;
    USE SIGNAL ;
    PORT
      LAYER M5 ;
        RECT  67.2 0 67.224 0.192 ;
    END
  END di[509]
  PIN di[50]
    DIRECTION INPUT ;
    USE SIGNAL ;
    PORT
      LAYER M3 ;
        RECT  10.548 0 10.566 0.144 ;
    END
  END di[50]
  PIN di[510]
    DIRECTION INPUT ;
    USE SIGNAL ;
    PORT
      LAYER M3 ;
        RECT  67.32 0 67.338 0.144 ;
    END
  END di[510]
  PIN di[511]
    DIRECTION INPUT ;
    USE SIGNAL ;
    PORT
      LAYER M5 ;
        RECT  67.44 0 67.464 0.192 ;
    END
  END di[511]
  PIN di[512]
    DIRECTION INPUT ;
    USE SIGNAL ;
    PORT
      LAYER M3 ;
        RECT  67.572 0 67.59 0.144 ;
    END
  END di[512]
  PIN di[513]
    DIRECTION INPUT ;
    USE SIGNAL ;
    PORT
      LAYER M5 ;
        RECT  67.68 0 67.704 0.192 ;
    END
  END di[513]
  PIN di[514]
    DIRECTION INPUT ;
    USE SIGNAL ;
    PORT
      LAYER M3 ;
        RECT  67.824 0 67.842 0.144 ;
    END
  END di[514]
  PIN di[515]
    DIRECTION INPUT ;
    USE SIGNAL ;
    PORT
      LAYER M5 ;
        RECT  67.92 0 67.944 0.192 ;
    END
  END di[515]
  PIN di[516]
    DIRECTION INPUT ;
    USE SIGNAL ;
    PORT
      LAYER M3 ;
        RECT  68.076 0 68.094 0.144 ;
    END
  END di[516]
  PIN di[517]
    DIRECTION INPUT ;
    USE SIGNAL ;
    PORT
      LAYER M5 ;
        RECT  68.16 0 68.184 0.192 ;
    END
  END di[517]
  PIN di[518]
    DIRECTION INPUT ;
    USE SIGNAL ;
    PORT
      LAYER M3 ;
        RECT  68.292 0 68.31 0.144 ;
    END
  END di[518]
  PIN di[519]
    DIRECTION INPUT ;
    USE SIGNAL ;
    PORT
      LAYER M5 ;
        RECT  68.448 0 68.472 0.192 ;
    END
  END di[519]
  PIN di[51]
    DIRECTION INPUT ;
    USE SIGNAL ;
    PORT
      LAYER M5 ;
        RECT  10.656 0 10.68 0.192 ;
    END
  END di[51]
  PIN di[520]
    DIRECTION INPUT ;
    USE SIGNAL ;
    PORT
      LAYER M3 ;
        RECT  68.544 0 68.562 0.144 ;
    END
  END di[520]
  PIN di[521]
    DIRECTION INPUT ;
    USE SIGNAL ;
    PORT
      LAYER M5 ;
        RECT  68.688 0 68.712 0.192 ;
    END
  END di[521]
  PIN di[522]
    DIRECTION INPUT ;
    USE SIGNAL ;
    PORT
      LAYER M3 ;
        RECT  68.796 0 68.814 0.144 ;
    END
  END di[522]
  PIN di[523]
    DIRECTION INPUT ;
    USE SIGNAL ;
    PORT
      LAYER M5 ;
        RECT  68.928 0 68.952 0.192 ;
    END
  END di[523]
  PIN di[524]
    DIRECTION INPUT ;
    USE SIGNAL ;
    PORT
      LAYER M3 ;
        RECT  69.048 0 69.066 0.144 ;
    END
  END di[524]
  PIN di[525]
    DIRECTION INPUT ;
    USE SIGNAL ;
    PORT
      LAYER M5 ;
        RECT  69.168 0 69.192 0.192 ;
    END
  END di[525]
  PIN di[526]
    DIRECTION INPUT ;
    USE SIGNAL ;
    PORT
      LAYER M3 ;
        RECT  69.3 0 69.318 0.144 ;
    END
  END di[526]
  PIN di[527]
    DIRECTION INPUT ;
    USE SIGNAL ;
    PORT
      LAYER M5 ;
        RECT  69.408 0 69.432 0.192 ;
    END
  END di[527]
  PIN di[528]
    DIRECTION INPUT ;
    USE SIGNAL ;
    PORT
      LAYER M3 ;
        RECT  69.552 0 69.57 0.144 ;
    END
  END di[528]
  PIN di[529]
    DIRECTION INPUT ;
    USE SIGNAL ;
    PORT
      LAYER M5 ;
        RECT  69.648 0 69.672 0.192 ;
    END
  END di[529]
  PIN di[52]
    DIRECTION INPUT ;
    USE SIGNAL ;
    PORT
      LAYER M3 ;
        RECT  10.8 0 10.818 0.144 ;
    END
  END di[52]
  PIN di[530]
    DIRECTION INPUT ;
    USE SIGNAL ;
    PORT
      LAYER M3 ;
        RECT  69.804 0 69.822 0.144 ;
    END
  END di[530]
  PIN di[531]
    DIRECTION INPUT ;
    USE SIGNAL ;
    PORT
      LAYER M5 ;
        RECT  69.888 0 69.912 0.192 ;
    END
  END di[531]
  PIN di[532]
    DIRECTION INPUT ;
    USE SIGNAL ;
    PORT
      LAYER M3 ;
        RECT  70.02 0 70.038 0.144 ;
    END
  END di[532]
  PIN di[533]
    DIRECTION INPUT ;
    USE SIGNAL ;
    PORT
      LAYER M5 ;
        RECT  70.176 0 70.2 0.192 ;
    END
  END di[533]
  PIN di[534]
    DIRECTION INPUT ;
    USE SIGNAL ;
    PORT
      LAYER M3 ;
        RECT  70.272 0 70.29 0.144 ;
    END
  END di[534]
  PIN di[535]
    DIRECTION INPUT ;
    USE SIGNAL ;
    PORT
      LAYER M5 ;
        RECT  70.416 0 70.44 0.192 ;
    END
  END di[535]
  PIN di[536]
    DIRECTION INPUT ;
    USE SIGNAL ;
    PORT
      LAYER M3 ;
        RECT  70.524 0 70.542 0.144 ;
    END
  END di[536]
  PIN di[537]
    DIRECTION INPUT ;
    USE SIGNAL ;
    PORT
      LAYER M5 ;
        RECT  70.656 0 70.68 0.192 ;
    END
  END di[537]
  PIN di[538]
    DIRECTION INPUT ;
    USE SIGNAL ;
    PORT
      LAYER M3 ;
        RECT  70.776 0 70.794 0.144 ;
    END
  END di[538]
  PIN di[539]
    DIRECTION INPUT ;
    USE SIGNAL ;
    PORT
      LAYER M5 ;
        RECT  70.896 0 70.92 0.192 ;
    END
  END di[539]
  PIN di[53]
    DIRECTION INPUT ;
    USE SIGNAL ;
    PORT
      LAYER M5 ;
        RECT  10.896 0 10.92 0.192 ;
    END
  END di[53]
  PIN di[540]
    DIRECTION INPUT ;
    USE SIGNAL ;
    PORT
      LAYER M3 ;
        RECT  71.028 0 71.046 0.144 ;
    END
  END di[540]
  PIN di[541]
    DIRECTION INPUT ;
    USE SIGNAL ;
    PORT
      LAYER M5 ;
        RECT  71.136 0 71.16 0.192 ;
    END
  END di[541]
  PIN di[542]
    DIRECTION INPUT ;
    USE SIGNAL ;
    PORT
      LAYER M3 ;
        RECT  71.28 0 71.298 0.144 ;
    END
  END di[542]
  PIN di[543]
    DIRECTION INPUT ;
    USE SIGNAL ;
    PORT
      LAYER M5 ;
        RECT  71.376 0 71.4 0.192 ;
    END
  END di[543]
  PIN di[544]
    DIRECTION INPUT ;
    USE SIGNAL ;
    PORT
      LAYER M3 ;
        RECT  71.532 0 71.55 0.144 ;
    END
  END di[544]
  PIN di[545]
    DIRECTION INPUT ;
    USE SIGNAL ;
    PORT
      LAYER M5 ;
        RECT  71.616 0 71.64 0.192 ;
    END
  END di[545]
  PIN di[546]
    DIRECTION INPUT ;
    USE SIGNAL ;
    PORT
      LAYER M3 ;
        RECT  71.748 0 71.766 0.144 ;
    END
  END di[546]
  PIN di[547]
    DIRECTION INPUT ;
    USE SIGNAL ;
    PORT
      LAYER M5 ;
        RECT  71.904 0 71.928 0.192 ;
    END
  END di[547]
  PIN di[548]
    DIRECTION INPUT ;
    USE SIGNAL ;
    PORT
      LAYER M3 ;
        RECT  72 0 72.018 0.144 ;
    END
  END di[548]
  PIN di[549]
    DIRECTION INPUT ;
    USE SIGNAL ;
    PORT
      LAYER M5 ;
        RECT  72.144 0 72.168 0.192 ;
    END
  END di[549]
  PIN di[54]
    DIRECTION INPUT ;
    USE SIGNAL ;
    PORT
      LAYER M3 ;
        RECT  11.052 0 11.07 0.144 ;
    END
  END di[54]
  PIN di[550]
    DIRECTION INPUT ;
    USE SIGNAL ;
    PORT
      LAYER M3 ;
        RECT  72.252 0 72.27 0.144 ;
    END
  END di[550]
  PIN di[551]
    DIRECTION INPUT ;
    USE SIGNAL ;
    PORT
      LAYER M5 ;
        RECT  72.384 0 72.408 0.192 ;
    END
  END di[551]
  PIN di[552]
    DIRECTION INPUT ;
    USE SIGNAL ;
    PORT
      LAYER M3 ;
        RECT  72.504 0 72.522 0.144 ;
    END
  END di[552]
  PIN di[553]
    DIRECTION INPUT ;
    USE SIGNAL ;
    PORT
      LAYER M5 ;
        RECT  72.624 0 72.648 0.192 ;
    END
  END di[553]
  PIN di[554]
    DIRECTION INPUT ;
    USE SIGNAL ;
    PORT
      LAYER M3 ;
        RECT  72.756 0 72.774 0.144 ;
    END
  END di[554]
  PIN di[555]
    DIRECTION INPUT ;
    USE SIGNAL ;
    PORT
      LAYER M5 ;
        RECT  72.864 0 72.888 0.192 ;
    END
  END di[555]
  PIN di[556]
    DIRECTION INPUT ;
    USE SIGNAL ;
    PORT
      LAYER M3 ;
        RECT  73.008 0 73.026 0.144 ;
    END
  END di[556]
  PIN di[557]
    DIRECTION INPUT ;
    USE SIGNAL ;
    PORT
      LAYER M5 ;
        RECT  73.104 0 73.128 0.192 ;
    END
  END di[557]
  PIN di[558]
    DIRECTION INPUT ;
    USE SIGNAL ;
    PORT
      LAYER M3 ;
        RECT  73.26 0 73.278 0.144 ;
    END
  END di[558]
  PIN di[559]
    DIRECTION INPUT ;
    USE SIGNAL ;
    PORT
      LAYER M5 ;
        RECT  73.344 0 73.368 0.192 ;
    END
  END di[559]
  PIN di[55]
    DIRECTION INPUT ;
    USE SIGNAL ;
    PORT
      LAYER M5 ;
        RECT  11.136 0 11.16 0.192 ;
    END
  END di[55]
  PIN di[56]
    DIRECTION INPUT ;
    USE SIGNAL ;
    PORT
      LAYER M3 ;
        RECT  11.268 0 11.286 0.144 ;
    END
  END di[56]
  PIN di[57]
    DIRECTION INPUT ;
    USE SIGNAL ;
    PORT
      LAYER M5 ;
        RECT  11.424 0 11.448 0.192 ;
    END
  END di[57]
  PIN di[58]
    DIRECTION INPUT ;
    USE SIGNAL ;
    PORT
      LAYER M3 ;
        RECT  11.52 0 11.538 0.144 ;
    END
  END di[58]
  PIN di[59]
    DIRECTION INPUT ;
    USE SIGNAL ;
    PORT
      LAYER M5 ;
        RECT  11.664 0 11.688 0.192 ;
    END
  END di[59]
  PIN di[5]
    DIRECTION INPUT ;
    USE SIGNAL ;
    PORT
      LAYER M5 ;
        RECT  4.992 0 5.016 0.192 ;
    END
  END di[5]
  PIN di[60]
    DIRECTION INPUT ;
    USE SIGNAL ;
    PORT
      LAYER M3 ;
        RECT  11.772 0 11.79 0.144 ;
    END
  END di[60]
  PIN di[61]
    DIRECTION INPUT ;
    USE SIGNAL ;
    PORT
      LAYER M5 ;
        RECT  11.904 0 11.928 0.192 ;
    END
  END di[61]
  PIN di[62]
    DIRECTION INPUT ;
    USE SIGNAL ;
    PORT
      LAYER M3 ;
        RECT  12.024 0 12.042 0.144 ;
    END
  END di[62]
  PIN di[63]
    DIRECTION INPUT ;
    USE SIGNAL ;
    PORT
      LAYER M5 ;
        RECT  12.144 0 12.168 0.192 ;
    END
  END di[63]
  PIN di[64]
    DIRECTION INPUT ;
    USE SIGNAL ;
    PORT
      LAYER M3 ;
        RECT  12.276 0 12.294 0.144 ;
    END
  END di[64]
  PIN di[65]
    DIRECTION INPUT ;
    USE SIGNAL ;
    PORT
      LAYER M5 ;
        RECT  12.384 0 12.408 0.192 ;
    END
  END di[65]
  PIN di[66]
    DIRECTION INPUT ;
    USE SIGNAL ;
    PORT
      LAYER M3 ;
        RECT  12.528 0 12.546 0.144 ;
    END
  END di[66]
  PIN di[67]
    DIRECTION INPUT ;
    USE SIGNAL ;
    PORT
      LAYER M5 ;
        RECT  12.624 0 12.648 0.192 ;
    END
  END di[67]
  PIN di[68]
    DIRECTION INPUT ;
    USE SIGNAL ;
    PORT
      LAYER M3 ;
        RECT  12.78 0 12.798 0.144 ;
    END
  END di[68]
  PIN di[69]
    DIRECTION INPUT ;
    USE SIGNAL ;
    PORT
      LAYER M5 ;
        RECT  12.864 0 12.888 0.192 ;
    END
  END di[69]
  PIN di[6]
    DIRECTION INPUT ;
    USE SIGNAL ;
    PORT
      LAYER M3 ;
        RECT  5.112 0 5.13 0.144 ;
    END
  END di[6]
  PIN di[70]
    DIRECTION INPUT ;
    USE SIGNAL ;
    PORT
      LAYER M3 ;
        RECT  12.996 0 13.014 0.144 ;
    END
  END di[70]
  PIN di[71]
    DIRECTION INPUT ;
    USE SIGNAL ;
    PORT
      LAYER M5 ;
        RECT  13.152 0 13.176 0.192 ;
    END
  END di[71]
  PIN di[72]
    DIRECTION INPUT ;
    USE SIGNAL ;
    PORT
      LAYER M3 ;
        RECT  13.248 0 13.266 0.144 ;
    END
  END di[72]
  PIN di[73]
    DIRECTION INPUT ;
    USE SIGNAL ;
    PORT
      LAYER M5 ;
        RECT  13.392 0 13.416 0.192 ;
    END
  END di[73]
  PIN di[74]
    DIRECTION INPUT ;
    USE SIGNAL ;
    PORT
      LAYER M3 ;
        RECT  13.5 0 13.518 0.144 ;
    END
  END di[74]
  PIN di[75]
    DIRECTION INPUT ;
    USE SIGNAL ;
    PORT
      LAYER M5 ;
        RECT  13.632 0 13.656 0.192 ;
    END
  END di[75]
  PIN di[76]
    DIRECTION INPUT ;
    USE SIGNAL ;
    PORT
      LAYER M3 ;
        RECT  13.752 0 13.77 0.144 ;
    END
  END di[76]
  PIN di[77]
    DIRECTION INPUT ;
    USE SIGNAL ;
    PORT
      LAYER M5 ;
        RECT  13.872 0 13.896 0.192 ;
    END
  END di[77]
  PIN di[78]
    DIRECTION INPUT ;
    USE SIGNAL ;
    PORT
      LAYER M3 ;
        RECT  14.004 0 14.022 0.144 ;
    END
  END di[78]
  PIN di[79]
    DIRECTION INPUT ;
    USE SIGNAL ;
    PORT
      LAYER M5 ;
        RECT  14.112 0 14.136 0.192 ;
    END
  END di[79]
  PIN di[7]
    DIRECTION INPUT ;
    USE SIGNAL ;
    PORT
      LAYER M5 ;
        RECT  5.232 0 5.256 0.192 ;
    END
  END di[7]
  PIN di[80]
    DIRECTION INPUT ;
    USE SIGNAL ;
    PORT
      LAYER M3 ;
        RECT  14.256 0 14.274 0.144 ;
    END
  END di[80]
  PIN di[81]
    DIRECTION INPUT ;
    USE SIGNAL ;
    PORT
      LAYER M5 ;
        RECT  14.352 0 14.376 0.192 ;
    END
  END di[81]
  PIN di[82]
    DIRECTION INPUT ;
    USE SIGNAL ;
    PORT
      LAYER M3 ;
        RECT  14.508 0 14.526 0.144 ;
    END
  END di[82]
  PIN di[83]
    DIRECTION INPUT ;
    USE SIGNAL ;
    PORT
      LAYER M5 ;
        RECT  14.592 0 14.616 0.192 ;
    END
  END di[83]
  PIN di[84]
    DIRECTION INPUT ;
    USE SIGNAL ;
    PORT
      LAYER M3 ;
        RECT  14.724 0 14.742 0.144 ;
    END
  END di[84]
  PIN di[85]
    DIRECTION INPUT ;
    USE SIGNAL ;
    PORT
      LAYER M5 ;
        RECT  14.88 0 14.904 0.192 ;
    END
  END di[85]
  PIN di[86]
    DIRECTION INPUT ;
    USE SIGNAL ;
    PORT
      LAYER M3 ;
        RECT  14.976 0 14.994 0.144 ;
    END
  END di[86]
  PIN di[87]
    DIRECTION INPUT ;
    USE SIGNAL ;
    PORT
      LAYER M5 ;
        RECT  15.12 0 15.144 0.192 ;
    END
  END di[87]
  PIN di[88]
    DIRECTION INPUT ;
    USE SIGNAL ;
    PORT
      LAYER M3 ;
        RECT  15.228 0 15.246 0.144 ;
    END
  END di[88]
  PIN di[89]
    DIRECTION INPUT ;
    USE SIGNAL ;
    PORT
      LAYER M5 ;
        RECT  15.36 0 15.384 0.192 ;
    END
  END di[89]
  PIN di[8]
    DIRECTION INPUT ;
    USE SIGNAL ;
    PORT
      LAYER M3 ;
        RECT  5.364 0 5.382 0.144 ;
    END
  END di[8]
  PIN di[90]
    DIRECTION INPUT ;
    USE SIGNAL ;
    PORT
      LAYER M3 ;
        RECT  15.48 0 15.498 0.144 ;
    END
  END di[90]
  PIN di[91]
    DIRECTION INPUT ;
    USE SIGNAL ;
    PORT
      LAYER M5 ;
        RECT  15.6 0 15.624 0.192 ;
    END
  END di[91]
  PIN di[92]
    DIRECTION INPUT ;
    USE SIGNAL ;
    PORT
      LAYER M3 ;
        RECT  15.732 0 15.75 0.144 ;
    END
  END di[92]
  PIN di[93]
    DIRECTION INPUT ;
    USE SIGNAL ;
    PORT
      LAYER M5 ;
        RECT  15.84 0 15.864 0.192 ;
    END
  END di[93]
  PIN di[94]
    DIRECTION INPUT ;
    USE SIGNAL ;
    PORT
      LAYER M3 ;
        RECT  15.984 0 16.002 0.144 ;
    END
  END di[94]
  PIN di[95]
    DIRECTION INPUT ;
    USE SIGNAL ;
    PORT
      LAYER M5 ;
        RECT  16.08 0 16.104 0.192 ;
    END
  END di[95]
  PIN di[96]
    DIRECTION INPUT ;
    USE SIGNAL ;
    PORT
      LAYER M3 ;
        RECT  16.236 0 16.254 0.144 ;
    END
  END di[96]
  PIN di[97]
    DIRECTION INPUT ;
    USE SIGNAL ;
    PORT
      LAYER M5 ;
        RECT  16.32 0 16.344 0.192 ;
    END
  END di[97]
  PIN di[98]
    DIRECTION INPUT ;
    USE SIGNAL ;
    PORT
      LAYER M3 ;
        RECT  16.452 0 16.47 0.144 ;
    END
  END di[98]
  PIN di[99]
    DIRECTION INPUT ;
    USE SIGNAL ;
    PORT
      LAYER M5 ;
        RECT  16.608 0 16.632 0.192 ;
    END
  END di[99]
  PIN di[9]
    DIRECTION INPUT ;
    USE SIGNAL ;
    PORT
      LAYER M5 ;
        RECT  5.472 0 5.496 0.192 ;
    END
  END di[9]
  PIN dq[0]
    DIRECTION OUTPUT ;
    USE SIGNAL ;
    PORT
      LAYER M3 ;
        RECT  4.356 36.576 4.374 36.72 ;
    END
  END dq[0]
  PIN dq[100]
    DIRECTION OUTPUT ;
    USE SIGNAL ;
    PORT
      LAYER M3 ;
        RECT  16.704 36.576 16.722 36.72 ;
    END
  END dq[100]
  PIN dq[101]
    DIRECTION OUTPUT ;
    USE SIGNAL ;
    PORT
      LAYER M5 ;
        RECT  16.848 36.528 16.872 36.72 ;
    END
  END dq[101]
  PIN dq[102]
    DIRECTION OUTPUT ;
    USE SIGNAL ;
    PORT
      LAYER M3 ;
        RECT  16.956 36.576 16.974 36.72 ;
    END
  END dq[102]
  PIN dq[103]
    DIRECTION OUTPUT ;
    USE SIGNAL ;
    PORT
      LAYER M5 ;
        RECT  17.088 36.528 17.112 36.72 ;
    END
  END dq[103]
  PIN dq[104]
    DIRECTION OUTPUT ;
    USE SIGNAL ;
    PORT
      LAYER M3 ;
        RECT  17.208 36.576 17.226 36.72 ;
    END
  END dq[104]
  PIN dq[105]
    DIRECTION OUTPUT ;
    USE SIGNAL ;
    PORT
      LAYER M5 ;
        RECT  17.328 36.528 17.352 36.72 ;
    END
  END dq[105]
  PIN dq[106]
    DIRECTION OUTPUT ;
    USE SIGNAL ;
    PORT
      LAYER M3 ;
        RECT  17.46 36.576 17.478 36.72 ;
    END
  END dq[106]
  PIN dq[107]
    DIRECTION OUTPUT ;
    USE SIGNAL ;
    PORT
      LAYER M5 ;
        RECT  17.568 36.528 17.592 36.72 ;
    END
  END dq[107]
  PIN dq[108]
    DIRECTION OUTPUT ;
    USE SIGNAL ;
    PORT
      LAYER M3 ;
        RECT  17.712 36.576 17.73 36.72 ;
    END
  END dq[108]
  PIN dq[109]
    DIRECTION OUTPUT ;
    USE SIGNAL ;
    PORT
      LAYER M5 ;
        RECT  17.808 36.528 17.832 36.72 ;
    END
  END dq[109]
  PIN dq[10]
    DIRECTION OUTPUT ;
    USE SIGNAL ;
    PORT
      LAYER M3 ;
        RECT  5.616 36.576 5.634 36.72 ;
    END
  END dq[10]
  PIN dq[110]
    DIRECTION OUTPUT ;
    USE SIGNAL ;
    PORT
      LAYER M3 ;
        RECT  17.964 36.576 17.982 36.72 ;
    END
  END dq[110]
  PIN dq[111]
    DIRECTION OUTPUT ;
    USE SIGNAL ;
    PORT
      LAYER M5 ;
        RECT  18.048 36.528 18.072 36.72 ;
    END
  END dq[111]
  PIN dq[112]
    DIRECTION OUTPUT ;
    USE SIGNAL ;
    PORT
      LAYER M3 ;
        RECT  18.18 36.576 18.198 36.72 ;
    END
  END dq[112]
  PIN dq[113]
    DIRECTION OUTPUT ;
    USE SIGNAL ;
    PORT
      LAYER M5 ;
        RECT  18.336 36.528 18.36 36.72 ;
    END
  END dq[113]
  PIN dq[114]
    DIRECTION OUTPUT ;
    USE SIGNAL ;
    PORT
      LAYER M3 ;
        RECT  18.432 36.576 18.45 36.72 ;
    END
  END dq[114]
  PIN dq[115]
    DIRECTION OUTPUT ;
    USE SIGNAL ;
    PORT
      LAYER M5 ;
        RECT  18.576 36.528 18.6 36.72 ;
    END
  END dq[115]
  PIN dq[116]
    DIRECTION OUTPUT ;
    USE SIGNAL ;
    PORT
      LAYER M3 ;
        RECT  18.684 36.576 18.702 36.72 ;
    END
  END dq[116]
  PIN dq[117]
    DIRECTION OUTPUT ;
    USE SIGNAL ;
    PORT
      LAYER M5 ;
        RECT  18.816 36.528 18.84 36.72 ;
    END
  END dq[117]
  PIN dq[118]
    DIRECTION OUTPUT ;
    USE SIGNAL ;
    PORT
      LAYER M3 ;
        RECT  18.936 36.576 18.954 36.72 ;
    END
  END dq[118]
  PIN dq[119]
    DIRECTION OUTPUT ;
    USE SIGNAL ;
    PORT
      LAYER M5 ;
        RECT  19.056 36.528 19.08 36.72 ;
    END
  END dq[119]
  PIN dq[11]
    DIRECTION OUTPUT ;
    USE SIGNAL ;
    PORT
      LAYER M5 ;
        RECT  5.712 36.528 5.736 36.72 ;
    END
  END dq[11]
  PIN dq[120]
    DIRECTION OUTPUT ;
    USE SIGNAL ;
    PORT
      LAYER M3 ;
        RECT  19.188 36.576 19.206 36.72 ;
    END
  END dq[120]
  PIN dq[121]
    DIRECTION OUTPUT ;
    USE SIGNAL ;
    PORT
      LAYER M5 ;
        RECT  19.296 36.528 19.32 36.72 ;
    END
  END dq[121]
  PIN dq[122]
    DIRECTION OUTPUT ;
    USE SIGNAL ;
    PORT
      LAYER M3 ;
        RECT  19.44 36.576 19.458 36.72 ;
    END
  END dq[122]
  PIN dq[123]
    DIRECTION OUTPUT ;
    USE SIGNAL ;
    PORT
      LAYER M5 ;
        RECT  19.536 36.528 19.56 36.72 ;
    END
  END dq[123]
  PIN dq[124]
    DIRECTION OUTPUT ;
    USE SIGNAL ;
    PORT
      LAYER M3 ;
        RECT  19.692 36.576 19.71 36.72 ;
    END
  END dq[124]
  PIN dq[125]
    DIRECTION OUTPUT ;
    USE SIGNAL ;
    PORT
      LAYER M5 ;
        RECT  19.776 36.528 19.8 36.72 ;
    END
  END dq[125]
  PIN dq[126]
    DIRECTION OUTPUT ;
    USE SIGNAL ;
    PORT
      LAYER M3 ;
        RECT  19.908 36.576 19.926 36.72 ;
    END
  END dq[126]
  PIN dq[127]
    DIRECTION OUTPUT ;
    USE SIGNAL ;
    PORT
      LAYER M5 ;
        RECT  20.064 36.528 20.088 36.72 ;
    END
  END dq[127]
  PIN dq[128]
    DIRECTION OUTPUT ;
    USE SIGNAL ;
    PORT
      LAYER M3 ;
        RECT  20.16 36.576 20.178 36.72 ;
    END
  END dq[128]
  PIN dq[129]
    DIRECTION OUTPUT ;
    USE SIGNAL ;
    PORT
      LAYER M5 ;
        RECT  20.304 36.528 20.328 36.72 ;
    END
  END dq[129]
  PIN dq[12]
    DIRECTION OUTPUT ;
    USE SIGNAL ;
    PORT
      LAYER M3 ;
        RECT  5.868 36.576 5.886 36.72 ;
    END
  END dq[12]
  PIN dq[130]
    DIRECTION OUTPUT ;
    USE SIGNAL ;
    PORT
      LAYER M3 ;
        RECT  20.412 36.576 20.43 36.72 ;
    END
  END dq[130]
  PIN dq[131]
    DIRECTION OUTPUT ;
    USE SIGNAL ;
    PORT
      LAYER M5 ;
        RECT  20.544 36.528 20.568 36.72 ;
    END
  END dq[131]
  PIN dq[132]
    DIRECTION OUTPUT ;
    USE SIGNAL ;
    PORT
      LAYER M3 ;
        RECT  20.664 36.576 20.682 36.72 ;
    END
  END dq[132]
  PIN dq[133]
    DIRECTION OUTPUT ;
    USE SIGNAL ;
    PORT
      LAYER M5 ;
        RECT  20.784 36.528 20.808 36.72 ;
    END
  END dq[133]
  PIN dq[134]
    DIRECTION OUTPUT ;
    USE SIGNAL ;
    PORT
      LAYER M3 ;
        RECT  20.916 36.576 20.934 36.72 ;
    END
  END dq[134]
  PIN dq[135]
    DIRECTION OUTPUT ;
    USE SIGNAL ;
    PORT
      LAYER M5 ;
        RECT  21.024 36.528 21.048 36.72 ;
    END
  END dq[135]
  PIN dq[136]
    DIRECTION OUTPUT ;
    USE SIGNAL ;
    PORT
      LAYER M3 ;
        RECT  21.168 36.576 21.186 36.72 ;
    END
  END dq[136]
  PIN dq[137]
    DIRECTION OUTPUT ;
    USE SIGNAL ;
    PORT
      LAYER M5 ;
        RECT  21.264 36.528 21.288 36.72 ;
    END
  END dq[137]
  PIN dq[138]
    DIRECTION OUTPUT ;
    USE SIGNAL ;
    PORT
      LAYER M3 ;
        RECT  21.42 36.576 21.438 36.72 ;
    END
  END dq[138]
  PIN dq[139]
    DIRECTION OUTPUT ;
    USE SIGNAL ;
    PORT
      LAYER M5 ;
        RECT  21.504 36.528 21.528 36.72 ;
    END
  END dq[139]
  PIN dq[13]
    DIRECTION OUTPUT ;
    USE SIGNAL ;
    PORT
      LAYER M5 ;
        RECT  5.952 36.528 5.976 36.72 ;
    END
  END dq[13]
  PIN dq[140]
    DIRECTION OUTPUT ;
    USE SIGNAL ;
    PORT
      LAYER M3 ;
        RECT  21.636 36.576 21.654 36.72 ;
    END
  END dq[140]
  PIN dq[141]
    DIRECTION OUTPUT ;
    USE SIGNAL ;
    PORT
      LAYER M5 ;
        RECT  21.792 36.528 21.816 36.72 ;
    END
  END dq[141]
  PIN dq[142]
    DIRECTION OUTPUT ;
    USE SIGNAL ;
    PORT
      LAYER M3 ;
        RECT  21.888 36.576 21.906 36.72 ;
    END
  END dq[142]
  PIN dq[143]
    DIRECTION OUTPUT ;
    USE SIGNAL ;
    PORT
      LAYER M5 ;
        RECT  22.032 36.528 22.056 36.72 ;
    END
  END dq[143]
  PIN dq[144]
    DIRECTION OUTPUT ;
    USE SIGNAL ;
    PORT
      LAYER M3 ;
        RECT  22.14 36.576 22.158 36.72 ;
    END
  END dq[144]
  PIN dq[145]
    DIRECTION OUTPUT ;
    USE SIGNAL ;
    PORT
      LAYER M5 ;
        RECT  22.272 36.528 22.296 36.72 ;
    END
  END dq[145]
  PIN dq[146]
    DIRECTION OUTPUT ;
    USE SIGNAL ;
    PORT
      LAYER M3 ;
        RECT  22.392 36.576 22.41 36.72 ;
    END
  END dq[146]
  PIN dq[147]
    DIRECTION OUTPUT ;
    USE SIGNAL ;
    PORT
      LAYER M5 ;
        RECT  22.512 36.528 22.536 36.72 ;
    END
  END dq[147]
  PIN dq[148]
    DIRECTION OUTPUT ;
    USE SIGNAL ;
    PORT
      LAYER M3 ;
        RECT  22.644 36.576 22.662 36.72 ;
    END
  END dq[148]
  PIN dq[149]
    DIRECTION OUTPUT ;
    USE SIGNAL ;
    PORT
      LAYER M5 ;
        RECT  22.752 36.528 22.776 36.72 ;
    END
  END dq[149]
  PIN dq[14]
    DIRECTION OUTPUT ;
    USE SIGNAL ;
    PORT
      LAYER M3 ;
        RECT  6.084 36.576 6.102 36.72 ;
    END
  END dq[14]
  PIN dq[150]
    DIRECTION OUTPUT ;
    USE SIGNAL ;
    PORT
      LAYER M3 ;
        RECT  22.896 36.576 22.914 36.72 ;
    END
  END dq[150]
  PIN dq[151]
    DIRECTION OUTPUT ;
    USE SIGNAL ;
    PORT
      LAYER M5 ;
        RECT  22.992 36.528 23.016 36.72 ;
    END
  END dq[151]
  PIN dq[152]
    DIRECTION OUTPUT ;
    USE SIGNAL ;
    PORT
      LAYER M3 ;
        RECT  23.148 36.576 23.166 36.72 ;
    END
  END dq[152]
  PIN dq[153]
    DIRECTION OUTPUT ;
    USE SIGNAL ;
    PORT
      LAYER M5 ;
        RECT  23.232 36.528 23.256 36.72 ;
    END
  END dq[153]
  PIN dq[154]
    DIRECTION OUTPUT ;
    USE SIGNAL ;
    PORT
      LAYER M3 ;
        RECT  23.364 36.576 23.382 36.72 ;
    END
  END dq[154]
  PIN dq[155]
    DIRECTION OUTPUT ;
    USE SIGNAL ;
    PORT
      LAYER M5 ;
        RECT  23.52 36.528 23.544 36.72 ;
    END
  END dq[155]
  PIN dq[156]
    DIRECTION OUTPUT ;
    USE SIGNAL ;
    PORT
      LAYER M3 ;
        RECT  23.616 36.576 23.634 36.72 ;
    END
  END dq[156]
  PIN dq[157]
    DIRECTION OUTPUT ;
    USE SIGNAL ;
    PORT
      LAYER M5 ;
        RECT  23.76 36.528 23.784 36.72 ;
    END
  END dq[157]
  PIN dq[158]
    DIRECTION OUTPUT ;
    USE SIGNAL ;
    PORT
      LAYER M3 ;
        RECT  23.868 36.576 23.886 36.72 ;
    END
  END dq[158]
  PIN dq[159]
    DIRECTION OUTPUT ;
    USE SIGNAL ;
    PORT
      LAYER M5 ;
        RECT  24 36.528 24.024 36.72 ;
    END
  END dq[159]
  PIN dq[15]
    DIRECTION OUTPUT ;
    USE SIGNAL ;
    PORT
      LAYER M5 ;
        RECT  6.24 36.528 6.264 36.72 ;
    END
  END dq[15]
  PIN dq[160]
    DIRECTION OUTPUT ;
    USE SIGNAL ;
    PORT
      LAYER M3 ;
        RECT  24.12 36.576 24.138 36.72 ;
    END
  END dq[160]
  PIN dq[161]
    DIRECTION OUTPUT ;
    USE SIGNAL ;
    PORT
      LAYER M5 ;
        RECT  24.24 36.528 24.264 36.72 ;
    END
  END dq[161]
  PIN dq[162]
    DIRECTION OUTPUT ;
    USE SIGNAL ;
    PORT
      LAYER M3 ;
        RECT  24.372 36.576 24.39 36.72 ;
    END
  END dq[162]
  PIN dq[163]
    DIRECTION OUTPUT ;
    USE SIGNAL ;
    PORT
      LAYER M5 ;
        RECT  24.48 36.528 24.504 36.72 ;
    END
  END dq[163]
  PIN dq[164]
    DIRECTION OUTPUT ;
    USE SIGNAL ;
    PORT
      LAYER M3 ;
        RECT  24.624 36.576 24.642 36.72 ;
    END
  END dq[164]
  PIN dq[165]
    DIRECTION OUTPUT ;
    USE SIGNAL ;
    PORT
      LAYER M5 ;
        RECT  24.72 36.528 24.744 36.72 ;
    END
  END dq[165]
  PIN dq[166]
    DIRECTION OUTPUT ;
    USE SIGNAL ;
    PORT
      LAYER M3 ;
        RECT  24.876 36.576 24.894 36.72 ;
    END
  END dq[166]
  PIN dq[167]
    DIRECTION OUTPUT ;
    USE SIGNAL ;
    PORT
      LAYER M5 ;
        RECT  24.96 36.528 24.984 36.72 ;
    END
  END dq[167]
  PIN dq[168]
    DIRECTION OUTPUT ;
    USE SIGNAL ;
    PORT
      LAYER M3 ;
        RECT  25.092 36.576 25.11 36.72 ;
    END
  END dq[168]
  PIN dq[169]
    DIRECTION OUTPUT ;
    USE SIGNAL ;
    PORT
      LAYER M5 ;
        RECT  25.248 36.528 25.272 36.72 ;
    END
  END dq[169]
  PIN dq[16]
    DIRECTION OUTPUT ;
    USE SIGNAL ;
    PORT
      LAYER M3 ;
        RECT  6.336 36.576 6.354 36.72 ;
    END
  END dq[16]
  PIN dq[170]
    DIRECTION OUTPUT ;
    USE SIGNAL ;
    PORT
      LAYER M3 ;
        RECT  25.344 36.576 25.362 36.72 ;
    END
  END dq[170]
  PIN dq[171]
    DIRECTION OUTPUT ;
    USE SIGNAL ;
    PORT
      LAYER M5 ;
        RECT  25.488 36.528 25.512 36.72 ;
    END
  END dq[171]
  PIN dq[172]
    DIRECTION OUTPUT ;
    USE SIGNAL ;
    PORT
      LAYER M3 ;
        RECT  25.596 36.576 25.614 36.72 ;
    END
  END dq[172]
  PIN dq[173]
    DIRECTION OUTPUT ;
    USE SIGNAL ;
    PORT
      LAYER M5 ;
        RECT  25.728 36.528 25.752 36.72 ;
    END
  END dq[173]
  PIN dq[174]
    DIRECTION OUTPUT ;
    USE SIGNAL ;
    PORT
      LAYER M3 ;
        RECT  25.848 36.576 25.866 36.72 ;
    END
  END dq[174]
  PIN dq[175]
    DIRECTION OUTPUT ;
    USE SIGNAL ;
    PORT
      LAYER M5 ;
        RECT  25.968 36.528 25.992 36.72 ;
    END
  END dq[175]
  PIN dq[176]
    DIRECTION OUTPUT ;
    USE SIGNAL ;
    PORT
      LAYER M3 ;
        RECT  26.1 36.576 26.118 36.72 ;
    END
  END dq[176]
  PIN dq[177]
    DIRECTION OUTPUT ;
    USE SIGNAL ;
    PORT
      LAYER M5 ;
        RECT  26.208 36.528 26.232 36.72 ;
    END
  END dq[177]
  PIN dq[178]
    DIRECTION OUTPUT ;
    USE SIGNAL ;
    PORT
      LAYER M3 ;
        RECT  26.352 36.576 26.37 36.72 ;
    END
  END dq[178]
  PIN dq[179]
    DIRECTION OUTPUT ;
    USE SIGNAL ;
    PORT
      LAYER M5 ;
        RECT  26.448 36.528 26.472 36.72 ;
    END
  END dq[179]
  PIN dq[17]
    DIRECTION OUTPUT ;
    USE SIGNAL ;
    PORT
      LAYER M5 ;
        RECT  6.48 36.528 6.504 36.72 ;
    END
  END dq[17]
  PIN dq[180]
    DIRECTION OUTPUT ;
    USE SIGNAL ;
    PORT
      LAYER M3 ;
        RECT  26.604 36.576 26.622 36.72 ;
    END
  END dq[180]
  PIN dq[181]
    DIRECTION OUTPUT ;
    USE SIGNAL ;
    PORT
      LAYER M5 ;
        RECT  26.688 36.528 26.712 36.72 ;
    END
  END dq[181]
  PIN dq[182]
    DIRECTION OUTPUT ;
    USE SIGNAL ;
    PORT
      LAYER M3 ;
        RECT  26.82 36.576 26.838 36.72 ;
    END
  END dq[182]
  PIN dq[183]
    DIRECTION OUTPUT ;
    USE SIGNAL ;
    PORT
      LAYER M5 ;
        RECT  26.976 36.528 27 36.72 ;
    END
  END dq[183]
  PIN dq[184]
    DIRECTION OUTPUT ;
    USE SIGNAL ;
    PORT
      LAYER M3 ;
        RECT  27.072 36.576 27.09 36.72 ;
    END
  END dq[184]
  PIN dq[185]
    DIRECTION OUTPUT ;
    USE SIGNAL ;
    PORT
      LAYER M5 ;
        RECT  27.216 36.528 27.24 36.72 ;
    END
  END dq[185]
  PIN dq[186]
    DIRECTION OUTPUT ;
    USE SIGNAL ;
    PORT
      LAYER M3 ;
        RECT  27.324 36.576 27.342 36.72 ;
    END
  END dq[186]
  PIN dq[187]
    DIRECTION OUTPUT ;
    USE SIGNAL ;
    PORT
      LAYER M5 ;
        RECT  27.456 36.528 27.48 36.72 ;
    END
  END dq[187]
  PIN dq[188]
    DIRECTION OUTPUT ;
    USE SIGNAL ;
    PORT
      LAYER M3 ;
        RECT  27.576 36.576 27.594 36.72 ;
    END
  END dq[188]
  PIN dq[189]
    DIRECTION OUTPUT ;
    USE SIGNAL ;
    PORT
      LAYER M5 ;
        RECT  27.696 36.528 27.72 36.72 ;
    END
  END dq[189]
  PIN dq[18]
    DIRECTION OUTPUT ;
    USE SIGNAL ;
    PORT
      LAYER M3 ;
        RECT  6.588 36.576 6.606 36.72 ;
    END
  END dq[18]
  PIN dq[190]
    DIRECTION OUTPUT ;
    USE SIGNAL ;
    PORT
      LAYER M3 ;
        RECT  27.828 36.576 27.846 36.72 ;
    END
  END dq[190]
  PIN dq[191]
    DIRECTION OUTPUT ;
    USE SIGNAL ;
    PORT
      LAYER M5 ;
        RECT  27.936 36.528 27.96 36.72 ;
    END
  END dq[191]
  PIN dq[192]
    DIRECTION OUTPUT ;
    USE SIGNAL ;
    PORT
      LAYER M3 ;
        RECT  28.08 36.576 28.098 36.72 ;
    END
  END dq[192]
  PIN dq[193]
    DIRECTION OUTPUT ;
    USE SIGNAL ;
    PORT
      LAYER M5 ;
        RECT  28.176 36.528 28.2 36.72 ;
    END
  END dq[193]
  PIN dq[194]
    DIRECTION OUTPUT ;
    USE SIGNAL ;
    PORT
      LAYER M3 ;
        RECT  28.332 36.576 28.35 36.72 ;
    END
  END dq[194]
  PIN dq[195]
    DIRECTION OUTPUT ;
    USE SIGNAL ;
    PORT
      LAYER M5 ;
        RECT  28.416 36.528 28.44 36.72 ;
    END
  END dq[195]
  PIN dq[196]
    DIRECTION OUTPUT ;
    USE SIGNAL ;
    PORT
      LAYER M3 ;
        RECT  28.548 36.576 28.566 36.72 ;
    END
  END dq[196]
  PIN dq[197]
    DIRECTION OUTPUT ;
    USE SIGNAL ;
    PORT
      LAYER M5 ;
        RECT  28.704 36.528 28.728 36.72 ;
    END
  END dq[197]
  PIN dq[198]
    DIRECTION OUTPUT ;
    USE SIGNAL ;
    PORT
      LAYER M3 ;
        RECT  28.8 36.576 28.818 36.72 ;
    END
  END dq[198]
  PIN dq[199]
    DIRECTION OUTPUT ;
    USE SIGNAL ;
    PORT
      LAYER M5 ;
        RECT  28.944 36.528 28.968 36.72 ;
    END
  END dq[199]
  PIN dq[19]
    DIRECTION OUTPUT ;
    USE SIGNAL ;
    PORT
      LAYER M5 ;
        RECT  6.72 36.528 6.744 36.72 ;
    END
  END dq[19]
  PIN dq[1]
    DIRECTION OUTPUT ;
    USE SIGNAL ;
    PORT
      LAYER M5 ;
        RECT  4.512 36.528 4.536 36.72 ;
    END
  END dq[1]
  PIN dq[200]
    DIRECTION OUTPUT ;
    USE SIGNAL ;
    PORT
      LAYER M3 ;
        RECT  29.052 36.576 29.07 36.72 ;
    END
  END dq[200]
  PIN dq[201]
    DIRECTION OUTPUT ;
    USE SIGNAL ;
    PORT
      LAYER M5 ;
        RECT  29.184 36.528 29.208 36.72 ;
    END
  END dq[201]
  PIN dq[202]
    DIRECTION OUTPUT ;
    USE SIGNAL ;
    PORT
      LAYER M3 ;
        RECT  29.304 36.576 29.322 36.72 ;
    END
  END dq[202]
  PIN dq[203]
    DIRECTION OUTPUT ;
    USE SIGNAL ;
    PORT
      LAYER M5 ;
        RECT  29.424 36.528 29.448 36.72 ;
    END
  END dq[203]
  PIN dq[204]
    DIRECTION OUTPUT ;
    USE SIGNAL ;
    PORT
      LAYER M3 ;
        RECT  29.556 36.576 29.574 36.72 ;
    END
  END dq[204]
  PIN dq[205]
    DIRECTION OUTPUT ;
    USE SIGNAL ;
    PORT
      LAYER M5 ;
        RECT  29.664 36.528 29.688 36.72 ;
    END
  END dq[205]
  PIN dq[206]
    DIRECTION OUTPUT ;
    USE SIGNAL ;
    PORT
      LAYER M3 ;
        RECT  29.808 36.576 29.826 36.72 ;
    END
  END dq[206]
  PIN dq[207]
    DIRECTION OUTPUT ;
    USE SIGNAL ;
    PORT
      LAYER M5 ;
        RECT  29.904 36.528 29.928 36.72 ;
    END
  END dq[207]
  PIN dq[208]
    DIRECTION OUTPUT ;
    USE SIGNAL ;
    PORT
      LAYER M3 ;
        RECT  30.06 36.576 30.078 36.72 ;
    END
  END dq[208]
  PIN dq[209]
    DIRECTION OUTPUT ;
    USE SIGNAL ;
    PORT
      LAYER M5 ;
        RECT  30.144 36.528 30.168 36.72 ;
    END
  END dq[209]
  PIN dq[20]
    DIRECTION OUTPUT ;
    USE SIGNAL ;
    PORT
      LAYER M3 ;
        RECT  6.84 36.576 6.858 36.72 ;
    END
  END dq[20]
  PIN dq[210]
    DIRECTION OUTPUT ;
    USE SIGNAL ;
    PORT
      LAYER M3 ;
        RECT  30.276 36.576 30.294 36.72 ;
    END
  END dq[210]
  PIN dq[211]
    DIRECTION OUTPUT ;
    USE SIGNAL ;
    PORT
      LAYER M5 ;
        RECT  30.432 36.528 30.456 36.72 ;
    END
  END dq[211]
  PIN dq[212]
    DIRECTION OUTPUT ;
    USE SIGNAL ;
    PORT
      LAYER M3 ;
        RECT  30.528 36.576 30.546 36.72 ;
    END
  END dq[212]
  PIN dq[213]
    DIRECTION OUTPUT ;
    USE SIGNAL ;
    PORT
      LAYER M5 ;
        RECT  30.672 36.528 30.696 36.72 ;
    END
  END dq[213]
  PIN dq[214]
    DIRECTION OUTPUT ;
    USE SIGNAL ;
    PORT
      LAYER M3 ;
        RECT  30.78 36.576 30.798 36.72 ;
    END
  END dq[214]
  PIN dq[215]
    DIRECTION OUTPUT ;
    USE SIGNAL ;
    PORT
      LAYER M5 ;
        RECT  30.912 36.528 30.936 36.72 ;
    END
  END dq[215]
  PIN dq[216]
    DIRECTION OUTPUT ;
    USE SIGNAL ;
    PORT
      LAYER M3 ;
        RECT  31.032 36.576 31.05 36.72 ;
    END
  END dq[216]
  PIN dq[217]
    DIRECTION OUTPUT ;
    USE SIGNAL ;
    PORT
      LAYER M5 ;
        RECT  31.152 36.528 31.176 36.72 ;
    END
  END dq[217]
  PIN dq[218]
    DIRECTION OUTPUT ;
    USE SIGNAL ;
    PORT
      LAYER M3 ;
        RECT  31.284 36.576 31.302 36.72 ;
    END
  END dq[218]
  PIN dq[219]
    DIRECTION OUTPUT ;
    USE SIGNAL ;
    PORT
      LAYER M5 ;
        RECT  31.392 36.528 31.416 36.72 ;
    END
  END dq[219]
  PIN dq[21]
    DIRECTION OUTPUT ;
    USE SIGNAL ;
    PORT
      LAYER M5 ;
        RECT  6.96 36.528 6.984 36.72 ;
    END
  END dq[21]
  PIN dq[220]
    DIRECTION OUTPUT ;
    USE SIGNAL ;
    PORT
      LAYER M3 ;
        RECT  31.536 36.576 31.554 36.72 ;
    END
  END dq[220]
  PIN dq[221]
    DIRECTION OUTPUT ;
    USE SIGNAL ;
    PORT
      LAYER M5 ;
        RECT  31.632 36.528 31.656 36.72 ;
    END
  END dq[221]
  PIN dq[222]
    DIRECTION OUTPUT ;
    USE SIGNAL ;
    PORT
      LAYER M3 ;
        RECT  31.788 36.576 31.806 36.72 ;
    END
  END dq[222]
  PIN dq[223]
    DIRECTION OUTPUT ;
    USE SIGNAL ;
    PORT
      LAYER M5 ;
        RECT  31.872 36.528 31.896 36.72 ;
    END
  END dq[223]
  PIN dq[224]
    DIRECTION OUTPUT ;
    USE SIGNAL ;
    PORT
      LAYER M3 ;
        RECT  32.004 36.576 32.022 36.72 ;
    END
  END dq[224]
  PIN dq[225]
    DIRECTION OUTPUT ;
    USE SIGNAL ;
    PORT
      LAYER M5 ;
        RECT  32.16 36.528 32.184 36.72 ;
    END
  END dq[225]
  PIN dq[226]
    DIRECTION OUTPUT ;
    USE SIGNAL ;
    PORT
      LAYER M3 ;
        RECT  32.256 36.576 32.274 36.72 ;
    END
  END dq[226]
  PIN dq[227]
    DIRECTION OUTPUT ;
    USE SIGNAL ;
    PORT
      LAYER M5 ;
        RECT  32.4 36.528 32.424 36.72 ;
    END
  END dq[227]
  PIN dq[228]
    DIRECTION OUTPUT ;
    USE SIGNAL ;
    PORT
      LAYER M3 ;
        RECT  32.508 36.576 32.526 36.72 ;
    END
  END dq[228]
  PIN dq[229]
    DIRECTION OUTPUT ;
    USE SIGNAL ;
    PORT
      LAYER M5 ;
        RECT  32.64 36.528 32.664 36.72 ;
    END
  END dq[229]
  PIN dq[22]
    DIRECTION OUTPUT ;
    USE SIGNAL ;
    PORT
      LAYER M3 ;
        RECT  7.092 36.576 7.11 36.72 ;
    END
  END dq[22]
  PIN dq[230]
    DIRECTION OUTPUT ;
    USE SIGNAL ;
    PORT
      LAYER M3 ;
        RECT  32.76 36.576 32.778 36.72 ;
    END
  END dq[230]
  PIN dq[231]
    DIRECTION OUTPUT ;
    USE SIGNAL ;
    PORT
      LAYER M5 ;
        RECT  32.88 36.528 32.904 36.72 ;
    END
  END dq[231]
  PIN dq[232]
    DIRECTION OUTPUT ;
    USE SIGNAL ;
    PORT
      LAYER M3 ;
        RECT  33.012 36.576 33.03 36.72 ;
    END
  END dq[232]
  PIN dq[233]
    DIRECTION OUTPUT ;
    USE SIGNAL ;
    PORT
      LAYER M5 ;
        RECT  33.12 36.528 33.144 36.72 ;
    END
  END dq[233]
  PIN dq[234]
    DIRECTION OUTPUT ;
    USE SIGNAL ;
    PORT
      LAYER M3 ;
        RECT  33.264 36.576 33.282 36.72 ;
    END
  END dq[234]
  PIN dq[235]
    DIRECTION OUTPUT ;
    USE SIGNAL ;
    PORT
      LAYER M5 ;
        RECT  33.36 36.528 33.384 36.72 ;
    END
  END dq[235]
  PIN dq[236]
    DIRECTION OUTPUT ;
    USE SIGNAL ;
    PORT
      LAYER M3 ;
        RECT  33.516 36.576 33.534 36.72 ;
    END
  END dq[236]
  PIN dq[237]
    DIRECTION OUTPUT ;
    USE SIGNAL ;
    PORT
      LAYER M5 ;
        RECT  33.6 36.528 33.624 36.72 ;
    END
  END dq[237]
  PIN dq[238]
    DIRECTION OUTPUT ;
    USE SIGNAL ;
    PORT
      LAYER M3 ;
        RECT  33.732 36.576 33.75 36.72 ;
    END
  END dq[238]
  PIN dq[239]
    DIRECTION OUTPUT ;
    USE SIGNAL ;
    PORT
      LAYER M5 ;
        RECT  33.888 36.528 33.912 36.72 ;
    END
  END dq[239]
  PIN dq[23]
    DIRECTION OUTPUT ;
    USE SIGNAL ;
    PORT
      LAYER M5 ;
        RECT  7.2 36.528 7.224 36.72 ;
    END
  END dq[23]
  PIN dq[240]
    DIRECTION OUTPUT ;
    USE SIGNAL ;
    PORT
      LAYER M3 ;
        RECT  33.984 36.576 34.002 36.72 ;
    END
  END dq[240]
  PIN dq[241]
    DIRECTION OUTPUT ;
    USE SIGNAL ;
    PORT
      LAYER M5 ;
        RECT  34.128 36.528 34.152 36.72 ;
    END
  END dq[241]
  PIN dq[242]
    DIRECTION OUTPUT ;
    USE SIGNAL ;
    PORT
      LAYER M3 ;
        RECT  34.236 36.576 34.254 36.72 ;
    END
  END dq[242]
  PIN dq[243]
    DIRECTION OUTPUT ;
    USE SIGNAL ;
    PORT
      LAYER M5 ;
        RECT  34.368 36.528 34.392 36.72 ;
    END
  END dq[243]
  PIN dq[244]
    DIRECTION OUTPUT ;
    USE SIGNAL ;
    PORT
      LAYER M3 ;
        RECT  34.488 36.576 34.506 36.72 ;
    END
  END dq[244]
  PIN dq[245]
    DIRECTION OUTPUT ;
    USE SIGNAL ;
    PORT
      LAYER M5 ;
        RECT  34.608 36.528 34.632 36.72 ;
    END
  END dq[245]
  PIN dq[246]
    DIRECTION OUTPUT ;
    USE SIGNAL ;
    PORT
      LAYER M3 ;
        RECT  34.74 36.576 34.758 36.72 ;
    END
  END dq[246]
  PIN dq[247]
    DIRECTION OUTPUT ;
    USE SIGNAL ;
    PORT
      LAYER M5 ;
        RECT  34.848 36.528 34.872 36.72 ;
    END
  END dq[247]
  PIN dq[248]
    DIRECTION OUTPUT ;
    USE SIGNAL ;
    PORT
      LAYER M3 ;
        RECT  34.992 36.576 35.01 36.72 ;
    END
  END dq[248]
  PIN dq[249]
    DIRECTION OUTPUT ;
    USE SIGNAL ;
    PORT
      LAYER M5 ;
        RECT  35.088 36.528 35.112 36.72 ;
    END
  END dq[249]
  PIN dq[24]
    DIRECTION OUTPUT ;
    USE SIGNAL ;
    PORT
      LAYER M3 ;
        RECT  7.344 36.576 7.362 36.72 ;
    END
  END dq[24]
  PIN dq[250]
    DIRECTION OUTPUT ;
    USE SIGNAL ;
    PORT
      LAYER M3 ;
        RECT  35.244 36.576 35.262 36.72 ;
    END
  END dq[250]
  PIN dq[251]
    DIRECTION OUTPUT ;
    USE SIGNAL ;
    PORT
      LAYER M5 ;
        RECT  35.328 36.528 35.352 36.72 ;
    END
  END dq[251]
  PIN dq[252]
    DIRECTION OUTPUT ;
    USE SIGNAL ;
    PORT
      LAYER M3 ;
        RECT  35.46 36.576 35.478 36.72 ;
    END
  END dq[252]
  PIN dq[253]
    DIRECTION OUTPUT ;
    USE SIGNAL ;
    PORT
      LAYER M5 ;
        RECT  35.616 36.528 35.64 36.72 ;
    END
  END dq[253]
  PIN dq[254]
    DIRECTION OUTPUT ;
    USE SIGNAL ;
    PORT
      LAYER M3 ;
        RECT  35.712 36.576 35.73 36.72 ;
    END
  END dq[254]
  PIN dq[255]
    DIRECTION OUTPUT ;
    USE SIGNAL ;
    PORT
      LAYER M5 ;
        RECT  35.856 36.528 35.88 36.72 ;
    END
  END dq[255]
  PIN dq[256]
    DIRECTION OUTPUT ;
    USE SIGNAL ;
    PORT
      LAYER M3 ;
        RECT  35.964 36.576 35.982 36.72 ;
    END
  END dq[256]
  PIN dq[257]
    DIRECTION OUTPUT ;
    USE SIGNAL ;
    PORT
      LAYER M5 ;
        RECT  36.096 36.528 36.12 36.72 ;
    END
  END dq[257]
  PIN dq[258]
    DIRECTION OUTPUT ;
    USE SIGNAL ;
    PORT
      LAYER M3 ;
        RECT  36.216 36.576 36.234 36.72 ;
    END
  END dq[258]
  PIN dq[259]
    DIRECTION OUTPUT ;
    USE SIGNAL ;
    PORT
      LAYER M5 ;
        RECT  36.336 36.528 36.36 36.72 ;
    END
  END dq[259]
  PIN dq[25]
    DIRECTION OUTPUT ;
    USE SIGNAL ;
    PORT
      LAYER M5 ;
        RECT  7.44 36.528 7.464 36.72 ;
    END
  END dq[25]
  PIN dq[260]
    DIRECTION OUTPUT ;
    USE SIGNAL ;
    PORT
      LAYER M3 ;
        RECT  36.468 36.576 36.486 36.72 ;
    END
  END dq[260]
  PIN dq[261]
    DIRECTION OUTPUT ;
    USE SIGNAL ;
    PORT
      LAYER M5 ;
        RECT  36.576 36.528 36.6 36.72 ;
    END
  END dq[261]
  PIN dq[262]
    DIRECTION OUTPUT ;
    USE SIGNAL ;
    PORT
      LAYER M3 ;
        RECT  36.72 36.576 36.738 36.72 ;
    END
  END dq[262]
  PIN dq[263]
    DIRECTION OUTPUT ;
    USE SIGNAL ;
    PORT
      LAYER M5 ;
        RECT  36.816 36.528 36.84 36.72 ;
    END
  END dq[263]
  PIN dq[264]
    DIRECTION OUTPUT ;
    USE SIGNAL ;
    PORT
      LAYER M3 ;
        RECT  36.972 36.576 36.99 36.72 ;
    END
  END dq[264]
  PIN dq[265]
    DIRECTION OUTPUT ;
    USE SIGNAL ;
    PORT
      LAYER M5 ;
        RECT  37.056 36.528 37.08 36.72 ;
    END
  END dq[265]
  PIN dq[266]
    DIRECTION OUTPUT ;
    USE SIGNAL ;
    PORT
      LAYER M3 ;
        RECT  37.188 36.576 37.206 36.72 ;
    END
  END dq[266]
  PIN dq[267]
    DIRECTION OUTPUT ;
    USE SIGNAL ;
    PORT
      LAYER M5 ;
        RECT  37.344 36.528 37.368 36.72 ;
    END
  END dq[267]
  PIN dq[268]
    DIRECTION OUTPUT ;
    USE SIGNAL ;
    PORT
      LAYER M3 ;
        RECT  37.44 36.576 37.458 36.72 ;
    END
  END dq[268]
  PIN dq[269]
    DIRECTION OUTPUT ;
    USE SIGNAL ;
    PORT
      LAYER M5 ;
        RECT  37.584 36.528 37.608 36.72 ;
    END
  END dq[269]
  PIN dq[26]
    DIRECTION OUTPUT ;
    USE SIGNAL ;
    PORT
      LAYER M3 ;
        RECT  7.596 36.576 7.614 36.72 ;
    END
  END dq[26]
  PIN dq[270]
    DIRECTION OUTPUT ;
    USE SIGNAL ;
    PORT
      LAYER M3 ;
        RECT  37.692 36.576 37.71 36.72 ;
    END
  END dq[270]
  PIN dq[271]
    DIRECTION OUTPUT ;
    USE SIGNAL ;
    PORT
      LAYER M5 ;
        RECT  37.824 36.528 37.848 36.72 ;
    END
  END dq[271]
  PIN dq[272]
    DIRECTION OUTPUT ;
    USE SIGNAL ;
    PORT
      LAYER M3 ;
        RECT  37.944 36.576 37.962 36.72 ;
    END
  END dq[272]
  PIN dq[273]
    DIRECTION OUTPUT ;
    USE SIGNAL ;
    PORT
      LAYER M5 ;
        RECT  38.064 36.528 38.088 36.72 ;
    END
  END dq[273]
  PIN dq[274]
    DIRECTION OUTPUT ;
    USE SIGNAL ;
    PORT
      LAYER M3 ;
        RECT  38.196 36.576 38.214 36.72 ;
    END
  END dq[274]
  PIN dq[275]
    DIRECTION OUTPUT ;
    USE SIGNAL ;
    PORT
      LAYER M5 ;
        RECT  38.304 36.528 38.328 36.72 ;
    END
  END dq[275]
  PIN dq[276]
    DIRECTION OUTPUT ;
    USE SIGNAL ;
    PORT
      LAYER M3 ;
        RECT  38.448 36.576 38.466 36.72 ;
    END
  END dq[276]
  PIN dq[277]
    DIRECTION OUTPUT ;
    USE SIGNAL ;
    PORT
      LAYER M5 ;
        RECT  38.544 36.528 38.568 36.72 ;
    END
  END dq[277]
  PIN dq[278]
    DIRECTION OUTPUT ;
    USE SIGNAL ;
    PORT
      LAYER M3 ;
        RECT  38.7 36.576 38.718 36.72 ;
    END
  END dq[278]
  PIN dq[279]
    DIRECTION OUTPUT ;
    USE SIGNAL ;
    PORT
      LAYER M5 ;
        RECT  38.784 36.528 38.808 36.72 ;
    END
  END dq[279]
  PIN dq[27]
    DIRECTION OUTPUT ;
    USE SIGNAL ;
    PORT
      LAYER M5 ;
        RECT  7.68 36.528 7.704 36.72 ;
    END
  END dq[27]
  PIN dq[280]
    DIRECTION OUTPUT ;
    USE SIGNAL ;
    PORT
      LAYER M3 ;
        RECT  38.916 36.576 38.934 36.72 ;
    END
  END dq[280]
  PIN dq[281]
    DIRECTION OUTPUT ;
    USE SIGNAL ;
    PORT
      LAYER M5 ;
        RECT  39.072 36.528 39.096 36.72 ;
    END
  END dq[281]
  PIN dq[282]
    DIRECTION OUTPUT ;
    USE SIGNAL ;
    PORT
      LAYER M3 ;
        RECT  39.168 36.576 39.186 36.72 ;
    END
  END dq[282]
  PIN dq[283]
    DIRECTION OUTPUT ;
    USE SIGNAL ;
    PORT
      LAYER M5 ;
        RECT  39.312 36.528 39.336 36.72 ;
    END
  END dq[283]
  PIN dq[284]
    DIRECTION OUTPUT ;
    USE SIGNAL ;
    PORT
      LAYER M3 ;
        RECT  39.42 36.576 39.438 36.72 ;
    END
  END dq[284]
  PIN dq[285]
    DIRECTION OUTPUT ;
    USE SIGNAL ;
    PORT
      LAYER M5 ;
        RECT  39.552 36.528 39.576 36.72 ;
    END
  END dq[285]
  PIN dq[286]
    DIRECTION OUTPUT ;
    USE SIGNAL ;
    PORT
      LAYER M3 ;
        RECT  39.672 36.576 39.69 36.72 ;
    END
  END dq[286]
  PIN dq[287]
    DIRECTION OUTPUT ;
    USE SIGNAL ;
    PORT
      LAYER M5 ;
        RECT  39.792 36.528 39.816 36.72 ;
    END
  END dq[287]
  PIN dq[288]
    DIRECTION OUTPUT ;
    USE SIGNAL ;
    PORT
      LAYER M3 ;
        RECT  39.924 36.576 39.942 36.72 ;
    END
  END dq[288]
  PIN dq[289]
    DIRECTION OUTPUT ;
    USE SIGNAL ;
    PORT
      LAYER M5 ;
        RECT  40.032 36.528 40.056 36.72 ;
    END
  END dq[289]
  PIN dq[28]
    DIRECTION OUTPUT ;
    USE SIGNAL ;
    PORT
      LAYER M3 ;
        RECT  7.812 36.576 7.83 36.72 ;
    END
  END dq[28]
  PIN dq[290]
    DIRECTION OUTPUT ;
    USE SIGNAL ;
    PORT
      LAYER M3 ;
        RECT  40.176 36.576 40.194 36.72 ;
    END
  END dq[290]
  PIN dq[291]
    DIRECTION OUTPUT ;
    USE SIGNAL ;
    PORT
      LAYER M5 ;
        RECT  40.272 36.528 40.296 36.72 ;
    END
  END dq[291]
  PIN dq[292]
    DIRECTION OUTPUT ;
    USE SIGNAL ;
    PORT
      LAYER M3 ;
        RECT  40.428 36.576 40.446 36.72 ;
    END
  END dq[292]
  PIN dq[293]
    DIRECTION OUTPUT ;
    USE SIGNAL ;
    PORT
      LAYER M5 ;
        RECT  40.512 36.528 40.536 36.72 ;
    END
  END dq[293]
  PIN dq[294]
    DIRECTION OUTPUT ;
    USE SIGNAL ;
    PORT
      LAYER M3 ;
        RECT  40.644 36.576 40.662 36.72 ;
    END
  END dq[294]
  PIN dq[295]
    DIRECTION OUTPUT ;
    USE SIGNAL ;
    PORT
      LAYER M5 ;
        RECT  40.8 36.528 40.824 36.72 ;
    END
  END dq[295]
  PIN dq[296]
    DIRECTION OUTPUT ;
    USE SIGNAL ;
    PORT
      LAYER M3 ;
        RECT  40.896 36.576 40.914 36.72 ;
    END
  END dq[296]
  PIN dq[297]
    DIRECTION OUTPUT ;
    USE SIGNAL ;
    PORT
      LAYER M5 ;
        RECT  41.04 36.528 41.064 36.72 ;
    END
  END dq[297]
  PIN dq[298]
    DIRECTION OUTPUT ;
    USE SIGNAL ;
    PORT
      LAYER M3 ;
        RECT  41.148 36.576 41.166 36.72 ;
    END
  END dq[298]
  PIN dq[299]
    DIRECTION OUTPUT ;
    USE SIGNAL ;
    PORT
      LAYER M5 ;
        RECT  41.28 36.528 41.304 36.72 ;
    END
  END dq[299]
  PIN dq[29]
    DIRECTION OUTPUT ;
    USE SIGNAL ;
    PORT
      LAYER M5 ;
        RECT  7.968 36.528 7.992 36.72 ;
    END
  END dq[29]
  PIN dq[2]
    DIRECTION OUTPUT ;
    USE SIGNAL ;
    PORT
      LAYER M3 ;
        RECT  4.608 36.576 4.626 36.72 ;
    END
  END dq[2]
  PIN dq[300]
    DIRECTION OUTPUT ;
    USE SIGNAL ;
    PORT
      LAYER M3 ;
        RECT  41.4 36.576 41.418 36.72 ;
    END
  END dq[300]
  PIN dq[301]
    DIRECTION OUTPUT ;
    USE SIGNAL ;
    PORT
      LAYER M5 ;
        RECT  41.52 36.528 41.544 36.72 ;
    END
  END dq[301]
  PIN dq[302]
    DIRECTION OUTPUT ;
    USE SIGNAL ;
    PORT
      LAYER M3 ;
        RECT  41.652 36.576 41.67 36.72 ;
    END
  END dq[302]
  PIN dq[303]
    DIRECTION OUTPUT ;
    USE SIGNAL ;
    PORT
      LAYER M5 ;
        RECT  41.76 36.528 41.784 36.72 ;
    END
  END dq[303]
  PIN dq[304]
    DIRECTION OUTPUT ;
    USE SIGNAL ;
    PORT
      LAYER M3 ;
        RECT  41.904 36.576 41.922 36.72 ;
    END
  END dq[304]
  PIN dq[305]
    DIRECTION OUTPUT ;
    USE SIGNAL ;
    PORT
      LAYER M5 ;
        RECT  42 36.528 42.024 36.72 ;
    END
  END dq[305]
  PIN dq[306]
    DIRECTION OUTPUT ;
    USE SIGNAL ;
    PORT
      LAYER M3 ;
        RECT  42.156 36.576 42.174 36.72 ;
    END
  END dq[306]
  PIN dq[307]
    DIRECTION OUTPUT ;
    USE SIGNAL ;
    PORT
      LAYER M5 ;
        RECT  42.24 36.528 42.264 36.72 ;
    END
  END dq[307]
  PIN dq[308]
    DIRECTION OUTPUT ;
    USE SIGNAL ;
    PORT
      LAYER M3 ;
        RECT  42.372 36.576 42.39 36.72 ;
    END
  END dq[308]
  PIN dq[309]
    DIRECTION OUTPUT ;
    USE SIGNAL ;
    PORT
      LAYER M5 ;
        RECT  42.528 36.528 42.552 36.72 ;
    END
  END dq[309]
  PIN dq[30]
    DIRECTION OUTPUT ;
    USE SIGNAL ;
    PORT
      LAYER M3 ;
        RECT  8.064 36.576 8.082 36.72 ;
    END
  END dq[30]
  PIN dq[310]
    DIRECTION OUTPUT ;
    USE SIGNAL ;
    PORT
      LAYER M3 ;
        RECT  42.624 36.576 42.642 36.72 ;
    END
  END dq[310]
  PIN dq[311]
    DIRECTION OUTPUT ;
    USE SIGNAL ;
    PORT
      LAYER M5 ;
        RECT  42.768 36.528 42.792 36.72 ;
    END
  END dq[311]
  PIN dq[312]
    DIRECTION OUTPUT ;
    USE SIGNAL ;
    PORT
      LAYER M3 ;
        RECT  42.876 36.576 42.894 36.72 ;
    END
  END dq[312]
  PIN dq[313]
    DIRECTION OUTPUT ;
    USE SIGNAL ;
    PORT
      LAYER M5 ;
        RECT  43.008 36.528 43.032 36.72 ;
    END
  END dq[313]
  PIN dq[314]
    DIRECTION OUTPUT ;
    USE SIGNAL ;
    PORT
      LAYER M3 ;
        RECT  43.128 36.576 43.146 36.72 ;
    END
  END dq[314]
  PIN dq[315]
    DIRECTION OUTPUT ;
    USE SIGNAL ;
    PORT
      LAYER M5 ;
        RECT  43.248 36.528 43.272 36.72 ;
    END
  END dq[315]
  PIN dq[316]
    DIRECTION OUTPUT ;
    USE SIGNAL ;
    PORT
      LAYER M3 ;
        RECT  43.38 36.576 43.398 36.72 ;
    END
  END dq[316]
  PIN dq[317]
    DIRECTION OUTPUT ;
    USE SIGNAL ;
    PORT
      LAYER M5 ;
        RECT  43.488 36.528 43.512 36.72 ;
    END
  END dq[317]
  PIN dq[318]
    DIRECTION OUTPUT ;
    USE SIGNAL ;
    PORT
      LAYER M3 ;
        RECT  43.632 36.576 43.65 36.72 ;
    END
  END dq[318]
  PIN dq[319]
    DIRECTION OUTPUT ;
    USE SIGNAL ;
    PORT
      LAYER M5 ;
        RECT  43.728 36.528 43.752 36.72 ;
    END
  END dq[319]
  PIN dq[31]
    DIRECTION OUTPUT ;
    USE SIGNAL ;
    PORT
      LAYER M5 ;
        RECT  8.208 36.528 8.232 36.72 ;
    END
  END dq[31]
  PIN dq[320]
    DIRECTION OUTPUT ;
    USE SIGNAL ;
    PORT
      LAYER M3 ;
        RECT  43.884 36.576 43.902 36.72 ;
    END
  END dq[320]
  PIN dq[321]
    DIRECTION OUTPUT ;
    USE SIGNAL ;
    PORT
      LAYER M5 ;
        RECT  43.968 36.528 43.992 36.72 ;
    END
  END dq[321]
  PIN dq[322]
    DIRECTION OUTPUT ;
    USE SIGNAL ;
    PORT
      LAYER M3 ;
        RECT  44.1 36.576 44.118 36.72 ;
    END
  END dq[322]
  PIN dq[323]
    DIRECTION OUTPUT ;
    USE SIGNAL ;
    PORT
      LAYER M5 ;
        RECT  44.256 36.528 44.28 36.72 ;
    END
  END dq[323]
  PIN dq[324]
    DIRECTION OUTPUT ;
    USE SIGNAL ;
    PORT
      LAYER M3 ;
        RECT  44.352 36.576 44.37 36.72 ;
    END
  END dq[324]
  PIN dq[325]
    DIRECTION OUTPUT ;
    USE SIGNAL ;
    PORT
      LAYER M5 ;
        RECT  44.496 36.528 44.52 36.72 ;
    END
  END dq[325]
  PIN dq[326]
    DIRECTION OUTPUT ;
    USE SIGNAL ;
    PORT
      LAYER M3 ;
        RECT  44.604 36.576 44.622 36.72 ;
    END
  END dq[326]
  PIN dq[327]
    DIRECTION OUTPUT ;
    USE SIGNAL ;
    PORT
      LAYER M5 ;
        RECT  44.736 36.528 44.76 36.72 ;
    END
  END dq[327]
  PIN dq[328]
    DIRECTION OUTPUT ;
    USE SIGNAL ;
    PORT
      LAYER M3 ;
        RECT  44.856 36.576 44.874 36.72 ;
    END
  END dq[328]
  PIN dq[329]
    DIRECTION OUTPUT ;
    USE SIGNAL ;
    PORT
      LAYER M5 ;
        RECT  44.976 36.528 45 36.72 ;
    END
  END dq[329]
  PIN dq[32]
    DIRECTION OUTPUT ;
    USE SIGNAL ;
    PORT
      LAYER M3 ;
        RECT  8.316 36.576 8.334 36.72 ;
    END
  END dq[32]
  PIN dq[330]
    DIRECTION OUTPUT ;
    USE SIGNAL ;
    PORT
      LAYER M3 ;
        RECT  45.108 36.576 45.126 36.72 ;
    END
  END dq[330]
  PIN dq[331]
    DIRECTION OUTPUT ;
    USE SIGNAL ;
    PORT
      LAYER M5 ;
        RECT  45.216 36.528 45.24 36.72 ;
    END
  END dq[331]
  PIN dq[332]
    DIRECTION OUTPUT ;
    USE SIGNAL ;
    PORT
      LAYER M3 ;
        RECT  45.36 36.576 45.378 36.72 ;
    END
  END dq[332]
  PIN dq[333]
    DIRECTION OUTPUT ;
    USE SIGNAL ;
    PORT
      LAYER M5 ;
        RECT  45.456 36.528 45.48 36.72 ;
    END
  END dq[333]
  PIN dq[334]
    DIRECTION OUTPUT ;
    USE SIGNAL ;
    PORT
      LAYER M3 ;
        RECT  45.612 36.576 45.63 36.72 ;
    END
  END dq[334]
  PIN dq[335]
    DIRECTION OUTPUT ;
    USE SIGNAL ;
    PORT
      LAYER M5 ;
        RECT  45.696 36.528 45.72 36.72 ;
    END
  END dq[335]
  PIN dq[336]
    DIRECTION OUTPUT ;
    USE SIGNAL ;
    PORT
      LAYER M3 ;
        RECT  45.828 36.576 45.846 36.72 ;
    END
  END dq[336]
  PIN dq[337]
    DIRECTION OUTPUT ;
    USE SIGNAL ;
    PORT
      LAYER M5 ;
        RECT  45.984 36.528 46.008 36.72 ;
    END
  END dq[337]
  PIN dq[338]
    DIRECTION OUTPUT ;
    USE SIGNAL ;
    PORT
      LAYER M3 ;
        RECT  46.08 36.576 46.098 36.72 ;
    END
  END dq[338]
  PIN dq[339]
    DIRECTION OUTPUT ;
    USE SIGNAL ;
    PORT
      LAYER M5 ;
        RECT  46.224 36.528 46.248 36.72 ;
    END
  END dq[339]
  PIN dq[33]
    DIRECTION OUTPUT ;
    USE SIGNAL ;
    PORT
      LAYER M5 ;
        RECT  8.448 36.528 8.472 36.72 ;
    END
  END dq[33]
  PIN dq[340]
    DIRECTION OUTPUT ;
    USE SIGNAL ;
    PORT
      LAYER M3 ;
        RECT  46.332 36.576 46.35 36.72 ;
    END
  END dq[340]
  PIN dq[341]
    DIRECTION OUTPUT ;
    USE SIGNAL ;
    PORT
      LAYER M5 ;
        RECT  46.464 36.528 46.488 36.72 ;
    END
  END dq[341]
  PIN dq[342]
    DIRECTION OUTPUT ;
    USE SIGNAL ;
    PORT
      LAYER M3 ;
        RECT  46.584 36.576 46.602 36.72 ;
    END
  END dq[342]
  PIN dq[343]
    DIRECTION OUTPUT ;
    USE SIGNAL ;
    PORT
      LAYER M5 ;
        RECT  46.704 36.528 46.728 36.72 ;
    END
  END dq[343]
  PIN dq[344]
    DIRECTION OUTPUT ;
    USE SIGNAL ;
    PORT
      LAYER M3 ;
        RECT  46.836 36.576 46.854 36.72 ;
    END
  END dq[344]
  PIN dq[345]
    DIRECTION OUTPUT ;
    USE SIGNAL ;
    PORT
      LAYER M5 ;
        RECT  46.944 36.528 46.968 36.72 ;
    END
  END dq[345]
  PIN dq[346]
    DIRECTION OUTPUT ;
    USE SIGNAL ;
    PORT
      LAYER M3 ;
        RECT  47.088 36.576 47.106 36.72 ;
    END
  END dq[346]
  PIN dq[347]
    DIRECTION OUTPUT ;
    USE SIGNAL ;
    PORT
      LAYER M5 ;
        RECT  47.184 36.528 47.208 36.72 ;
    END
  END dq[347]
  PIN dq[348]
    DIRECTION OUTPUT ;
    USE SIGNAL ;
    PORT
      LAYER M3 ;
        RECT  47.34 36.576 47.358 36.72 ;
    END
  END dq[348]
  PIN dq[349]
    DIRECTION OUTPUT ;
    USE SIGNAL ;
    PORT
      LAYER M5 ;
        RECT  47.424 36.528 47.448 36.72 ;
    END
  END dq[349]
  PIN dq[34]
    DIRECTION OUTPUT ;
    USE SIGNAL ;
    PORT
      LAYER M3 ;
        RECT  8.568 36.576 8.586 36.72 ;
    END
  END dq[34]
  PIN dq[350]
    DIRECTION OUTPUT ;
    USE SIGNAL ;
    PORT
      LAYER M3 ;
        RECT  47.556 36.576 47.574 36.72 ;
    END
  END dq[350]
  PIN dq[351]
    DIRECTION OUTPUT ;
    USE SIGNAL ;
    PORT
      LAYER M5 ;
        RECT  47.712 36.528 47.736 36.72 ;
    END
  END dq[351]
  PIN dq[352]
    DIRECTION OUTPUT ;
    USE SIGNAL ;
    PORT
      LAYER M3 ;
        RECT  47.808 36.576 47.826 36.72 ;
    END
  END dq[352]
  PIN dq[353]
    DIRECTION OUTPUT ;
    USE SIGNAL ;
    PORT
      LAYER M5 ;
        RECT  47.952 36.528 47.976 36.72 ;
    END
  END dq[353]
  PIN dq[354]
    DIRECTION OUTPUT ;
    USE SIGNAL ;
    PORT
      LAYER M3 ;
        RECT  48.06 36.576 48.078 36.72 ;
    END
  END dq[354]
  PIN dq[355]
    DIRECTION OUTPUT ;
    USE SIGNAL ;
    PORT
      LAYER M5 ;
        RECT  48.192 36.528 48.216 36.72 ;
    END
  END dq[355]
  PIN dq[356]
    DIRECTION OUTPUT ;
    USE SIGNAL ;
    PORT
      LAYER M3 ;
        RECT  48.312 36.576 48.33 36.72 ;
    END
  END dq[356]
  PIN dq[357]
    DIRECTION OUTPUT ;
    USE SIGNAL ;
    PORT
      LAYER M5 ;
        RECT  48.432 36.528 48.456 36.72 ;
    END
  END dq[357]
  PIN dq[358]
    DIRECTION OUTPUT ;
    USE SIGNAL ;
    PORT
      LAYER M3 ;
        RECT  48.564 36.576 48.582 36.72 ;
    END
  END dq[358]
  PIN dq[359]
    DIRECTION OUTPUT ;
    USE SIGNAL ;
    PORT
      LAYER M5 ;
        RECT  48.672 36.528 48.696 36.72 ;
    END
  END dq[359]
  PIN dq[35]
    DIRECTION OUTPUT ;
    USE SIGNAL ;
    PORT
      LAYER M5 ;
        RECT  8.688 36.528 8.712 36.72 ;
    END
  END dq[35]
  PIN dq[360]
    DIRECTION OUTPUT ;
    USE SIGNAL ;
    PORT
      LAYER M3 ;
        RECT  48.816 36.576 48.834 36.72 ;
    END
  END dq[360]
  PIN dq[361]
    DIRECTION OUTPUT ;
    USE SIGNAL ;
    PORT
      LAYER M5 ;
        RECT  48.912 36.528 48.936 36.72 ;
    END
  END dq[361]
  PIN dq[362]
    DIRECTION OUTPUT ;
    USE SIGNAL ;
    PORT
      LAYER M3 ;
        RECT  49.068 36.576 49.086 36.72 ;
    END
  END dq[362]
  PIN dq[363]
    DIRECTION OUTPUT ;
    USE SIGNAL ;
    PORT
      LAYER M5 ;
        RECT  49.152 36.528 49.176 36.72 ;
    END
  END dq[363]
  PIN dq[364]
    DIRECTION OUTPUT ;
    USE SIGNAL ;
    PORT
      LAYER M3 ;
        RECT  49.284 36.576 49.302 36.72 ;
    END
  END dq[364]
  PIN dq[365]
    DIRECTION OUTPUT ;
    USE SIGNAL ;
    PORT
      LAYER M5 ;
        RECT  49.44 36.528 49.464 36.72 ;
    END
  END dq[365]
  PIN dq[366]
    DIRECTION OUTPUT ;
    USE SIGNAL ;
    PORT
      LAYER M3 ;
        RECT  49.536 36.576 49.554 36.72 ;
    END
  END dq[366]
  PIN dq[367]
    DIRECTION OUTPUT ;
    USE SIGNAL ;
    PORT
      LAYER M5 ;
        RECT  49.68 36.528 49.704 36.72 ;
    END
  END dq[367]
  PIN dq[368]
    DIRECTION OUTPUT ;
    USE SIGNAL ;
    PORT
      LAYER M3 ;
        RECT  49.788 36.576 49.806 36.72 ;
    END
  END dq[368]
  PIN dq[369]
    DIRECTION OUTPUT ;
    USE SIGNAL ;
    PORT
      LAYER M5 ;
        RECT  49.92 36.528 49.944 36.72 ;
    END
  END dq[369]
  PIN dq[36]
    DIRECTION OUTPUT ;
    USE SIGNAL ;
    PORT
      LAYER M3 ;
        RECT  8.82 36.576 8.838 36.72 ;
    END
  END dq[36]
  PIN dq[370]
    DIRECTION OUTPUT ;
    USE SIGNAL ;
    PORT
      LAYER M3 ;
        RECT  50.04 36.576 50.058 36.72 ;
    END
  END dq[370]
  PIN dq[371]
    DIRECTION OUTPUT ;
    USE SIGNAL ;
    PORT
      LAYER M5 ;
        RECT  50.16 36.528 50.184 36.72 ;
    END
  END dq[371]
  PIN dq[372]
    DIRECTION OUTPUT ;
    USE SIGNAL ;
    PORT
      LAYER M3 ;
        RECT  50.292 36.576 50.31 36.72 ;
    END
  END dq[372]
  PIN dq[373]
    DIRECTION OUTPUT ;
    USE SIGNAL ;
    PORT
      LAYER M5 ;
        RECT  50.4 36.528 50.424 36.72 ;
    END
  END dq[373]
  PIN dq[374]
    DIRECTION OUTPUT ;
    USE SIGNAL ;
    PORT
      LAYER M3 ;
        RECT  50.544 36.576 50.562 36.72 ;
    END
  END dq[374]
  PIN dq[375]
    DIRECTION OUTPUT ;
    USE SIGNAL ;
    PORT
      LAYER M5 ;
        RECT  50.64 36.528 50.664 36.72 ;
    END
  END dq[375]
  PIN dq[376]
    DIRECTION OUTPUT ;
    USE SIGNAL ;
    PORT
      LAYER M3 ;
        RECT  50.796 36.576 50.814 36.72 ;
    END
  END dq[376]
  PIN dq[377]
    DIRECTION OUTPUT ;
    USE SIGNAL ;
    PORT
      LAYER M5 ;
        RECT  50.88 36.528 50.904 36.72 ;
    END
  END dq[377]
  PIN dq[378]
    DIRECTION OUTPUT ;
    USE SIGNAL ;
    PORT
      LAYER M3 ;
        RECT  51.012 36.576 51.03 36.72 ;
    END
  END dq[378]
  PIN dq[379]
    DIRECTION OUTPUT ;
    USE SIGNAL ;
    PORT
      LAYER M5 ;
        RECT  51.168 36.528 51.192 36.72 ;
    END
  END dq[379]
  PIN dq[37]
    DIRECTION OUTPUT ;
    USE SIGNAL ;
    PORT
      LAYER M5 ;
        RECT  8.928 36.528 8.952 36.72 ;
    END
  END dq[37]
  PIN dq[380]
    DIRECTION OUTPUT ;
    USE SIGNAL ;
    PORT
      LAYER M3 ;
        RECT  51.264 36.576 51.282 36.72 ;
    END
  END dq[380]
  PIN dq[381]
    DIRECTION OUTPUT ;
    USE SIGNAL ;
    PORT
      LAYER M5 ;
        RECT  51.408 36.528 51.432 36.72 ;
    END
  END dq[381]
  PIN dq[382]
    DIRECTION OUTPUT ;
    USE SIGNAL ;
    PORT
      LAYER M3 ;
        RECT  51.516 36.576 51.534 36.72 ;
    END
  END dq[382]
  PIN dq[383]
    DIRECTION OUTPUT ;
    USE SIGNAL ;
    PORT
      LAYER M5 ;
        RECT  51.648 36.528 51.672 36.72 ;
    END
  END dq[383]
  PIN dq[384]
    DIRECTION OUTPUT ;
    USE SIGNAL ;
    PORT
      LAYER M3 ;
        RECT  51.768 36.576 51.786 36.72 ;
    END
  END dq[384]
  PIN dq[385]
    DIRECTION OUTPUT ;
    USE SIGNAL ;
    PORT
      LAYER M5 ;
        RECT  51.888 36.528 51.912 36.72 ;
    END
  END dq[385]
  PIN dq[386]
    DIRECTION OUTPUT ;
    USE SIGNAL ;
    PORT
      LAYER M3 ;
        RECT  52.02 36.576 52.038 36.72 ;
    END
  END dq[386]
  PIN dq[387]
    DIRECTION OUTPUT ;
    USE SIGNAL ;
    PORT
      LAYER M5 ;
        RECT  52.128 36.528 52.152 36.72 ;
    END
  END dq[387]
  PIN dq[388]
    DIRECTION OUTPUT ;
    USE SIGNAL ;
    PORT
      LAYER M3 ;
        RECT  52.272 36.576 52.29 36.72 ;
    END
  END dq[388]
  PIN dq[389]
    DIRECTION OUTPUT ;
    USE SIGNAL ;
    PORT
      LAYER M5 ;
        RECT  52.368 36.528 52.392 36.72 ;
    END
  END dq[389]
  PIN dq[38]
    DIRECTION OUTPUT ;
    USE SIGNAL ;
    PORT
      LAYER M3 ;
        RECT  9.072 36.576 9.09 36.72 ;
    END
  END dq[38]
  PIN dq[390]
    DIRECTION OUTPUT ;
    USE SIGNAL ;
    PORT
      LAYER M3 ;
        RECT  52.524 36.576 52.542 36.72 ;
    END
  END dq[390]
  PIN dq[391]
    DIRECTION OUTPUT ;
    USE SIGNAL ;
    PORT
      LAYER M5 ;
        RECT  52.608 36.528 52.632 36.72 ;
    END
  END dq[391]
  PIN dq[392]
    DIRECTION OUTPUT ;
    USE SIGNAL ;
    PORT
      LAYER M3 ;
        RECT  52.74 36.576 52.758 36.72 ;
    END
  END dq[392]
  PIN dq[393]
    DIRECTION OUTPUT ;
    USE SIGNAL ;
    PORT
      LAYER M5 ;
        RECT  52.896 36.528 52.92 36.72 ;
    END
  END dq[393]
  PIN dq[394]
    DIRECTION OUTPUT ;
    USE SIGNAL ;
    PORT
      LAYER M3 ;
        RECT  52.992 36.576 53.01 36.72 ;
    END
  END dq[394]
  PIN dq[395]
    DIRECTION OUTPUT ;
    USE SIGNAL ;
    PORT
      LAYER M5 ;
        RECT  53.136 36.528 53.16 36.72 ;
    END
  END dq[395]
  PIN dq[396]
    DIRECTION OUTPUT ;
    USE SIGNAL ;
    PORT
      LAYER M3 ;
        RECT  53.244 36.576 53.262 36.72 ;
    END
  END dq[396]
  PIN dq[397]
    DIRECTION OUTPUT ;
    USE SIGNAL ;
    PORT
      LAYER M5 ;
        RECT  53.376 36.528 53.4 36.72 ;
    END
  END dq[397]
  PIN dq[398]
    DIRECTION OUTPUT ;
    USE SIGNAL ;
    PORT
      LAYER M3 ;
        RECT  53.496 36.576 53.514 36.72 ;
    END
  END dq[398]
  PIN dq[399]
    DIRECTION OUTPUT ;
    USE SIGNAL ;
    PORT
      LAYER M5 ;
        RECT  53.616 36.528 53.64 36.72 ;
    END
  END dq[399]
  PIN dq[39]
    DIRECTION OUTPUT ;
    USE SIGNAL ;
    PORT
      LAYER M5 ;
        RECT  9.168 36.528 9.192 36.72 ;
    END
  END dq[39]
  PIN dq[3]
    DIRECTION OUTPUT ;
    USE SIGNAL ;
    PORT
      LAYER M5 ;
        RECT  4.752 36.528 4.776 36.72 ;
    END
  END dq[3]
  PIN dq[400]
    DIRECTION OUTPUT ;
    USE SIGNAL ;
    PORT
      LAYER M3 ;
        RECT  53.748 36.576 53.766 36.72 ;
    END
  END dq[400]
  PIN dq[401]
    DIRECTION OUTPUT ;
    USE SIGNAL ;
    PORT
      LAYER M5 ;
        RECT  53.856 36.528 53.88 36.72 ;
    END
  END dq[401]
  PIN dq[402]
    DIRECTION OUTPUT ;
    USE SIGNAL ;
    PORT
      LAYER M3 ;
        RECT  54 36.576 54.018 36.72 ;
    END
  END dq[402]
  PIN dq[403]
    DIRECTION OUTPUT ;
    USE SIGNAL ;
    PORT
      LAYER M5 ;
        RECT  54.096 36.528 54.12 36.72 ;
    END
  END dq[403]
  PIN dq[404]
    DIRECTION OUTPUT ;
    USE SIGNAL ;
    PORT
      LAYER M3 ;
        RECT  54.252 36.576 54.27 36.72 ;
    END
  END dq[404]
  PIN dq[405]
    DIRECTION OUTPUT ;
    USE SIGNAL ;
    PORT
      LAYER M5 ;
        RECT  54.336 36.528 54.36 36.72 ;
    END
  END dq[405]
  PIN dq[406]
    DIRECTION OUTPUT ;
    USE SIGNAL ;
    PORT
      LAYER M3 ;
        RECT  54.468 36.576 54.486 36.72 ;
    END
  END dq[406]
  PIN dq[407]
    DIRECTION OUTPUT ;
    USE SIGNAL ;
    PORT
      LAYER M5 ;
        RECT  54.624 36.528 54.648 36.72 ;
    END
  END dq[407]
  PIN dq[408]
    DIRECTION OUTPUT ;
    USE SIGNAL ;
    PORT
      LAYER M3 ;
        RECT  54.72 36.576 54.738 36.72 ;
    END
  END dq[408]
  PIN dq[409]
    DIRECTION OUTPUT ;
    USE SIGNAL ;
    PORT
      LAYER M5 ;
        RECT  54.864 36.528 54.888 36.72 ;
    END
  END dq[409]
  PIN dq[40]
    DIRECTION OUTPUT ;
    USE SIGNAL ;
    PORT
      LAYER M3 ;
        RECT  9.324 36.576 9.342 36.72 ;
    END
  END dq[40]
  PIN dq[410]
    DIRECTION OUTPUT ;
    USE SIGNAL ;
    PORT
      LAYER M3 ;
        RECT  54.972 36.576 54.99 36.72 ;
    END
  END dq[410]
  PIN dq[411]
    DIRECTION OUTPUT ;
    USE SIGNAL ;
    PORT
      LAYER M5 ;
        RECT  55.104 36.528 55.128 36.72 ;
    END
  END dq[411]
  PIN dq[412]
    DIRECTION OUTPUT ;
    USE SIGNAL ;
    PORT
      LAYER M3 ;
        RECT  55.224 36.576 55.242 36.72 ;
    END
  END dq[412]
  PIN dq[413]
    DIRECTION OUTPUT ;
    USE SIGNAL ;
    PORT
      LAYER M5 ;
        RECT  55.344 36.528 55.368 36.72 ;
    END
  END dq[413]
  PIN dq[414]
    DIRECTION OUTPUT ;
    USE SIGNAL ;
    PORT
      LAYER M3 ;
        RECT  55.476 36.576 55.494 36.72 ;
    END
  END dq[414]
  PIN dq[415]
    DIRECTION OUTPUT ;
    USE SIGNAL ;
    PORT
      LAYER M5 ;
        RECT  55.584 36.528 55.608 36.72 ;
    END
  END dq[415]
  PIN dq[416]
    DIRECTION OUTPUT ;
    USE SIGNAL ;
    PORT
      LAYER M3 ;
        RECT  55.728 36.576 55.746 36.72 ;
    END
  END dq[416]
  PIN dq[417]
    DIRECTION OUTPUT ;
    USE SIGNAL ;
    PORT
      LAYER M5 ;
        RECT  55.824 36.528 55.848 36.72 ;
    END
  END dq[417]
  PIN dq[418]
    DIRECTION OUTPUT ;
    USE SIGNAL ;
    PORT
      LAYER M3 ;
        RECT  55.98 36.576 55.998 36.72 ;
    END
  END dq[418]
  PIN dq[419]
    DIRECTION OUTPUT ;
    USE SIGNAL ;
    PORT
      LAYER M5 ;
        RECT  56.064 36.528 56.088 36.72 ;
    END
  END dq[419]
  PIN dq[41]
    DIRECTION OUTPUT ;
    USE SIGNAL ;
    PORT
      LAYER M5 ;
        RECT  9.408 36.528 9.432 36.72 ;
    END
  END dq[41]
  PIN dq[420]
    DIRECTION OUTPUT ;
    USE SIGNAL ;
    PORT
      LAYER M3 ;
        RECT  56.196 36.576 56.214 36.72 ;
    END
  END dq[420]
  PIN dq[421]
    DIRECTION OUTPUT ;
    USE SIGNAL ;
    PORT
      LAYER M5 ;
        RECT  56.352 36.528 56.376 36.72 ;
    END
  END dq[421]
  PIN dq[422]
    DIRECTION OUTPUT ;
    USE SIGNAL ;
    PORT
      LAYER M3 ;
        RECT  56.448 36.576 56.466 36.72 ;
    END
  END dq[422]
  PIN dq[423]
    DIRECTION OUTPUT ;
    USE SIGNAL ;
    PORT
      LAYER M5 ;
        RECT  56.592 36.528 56.616 36.72 ;
    END
  END dq[423]
  PIN dq[424]
    DIRECTION OUTPUT ;
    USE SIGNAL ;
    PORT
      LAYER M3 ;
        RECT  56.7 36.576 56.718 36.72 ;
    END
  END dq[424]
  PIN dq[425]
    DIRECTION OUTPUT ;
    USE SIGNAL ;
    PORT
      LAYER M5 ;
        RECT  56.832 36.528 56.856 36.72 ;
    END
  END dq[425]
  PIN dq[426]
    DIRECTION OUTPUT ;
    USE SIGNAL ;
    PORT
      LAYER M3 ;
        RECT  56.952 36.576 56.97 36.72 ;
    END
  END dq[426]
  PIN dq[427]
    DIRECTION OUTPUT ;
    USE SIGNAL ;
    PORT
      LAYER M5 ;
        RECT  57.072 36.528 57.096 36.72 ;
    END
  END dq[427]
  PIN dq[428]
    DIRECTION OUTPUT ;
    USE SIGNAL ;
    PORT
      LAYER M3 ;
        RECT  57.204 36.576 57.222 36.72 ;
    END
  END dq[428]
  PIN dq[429]
    DIRECTION OUTPUT ;
    USE SIGNAL ;
    PORT
      LAYER M5 ;
        RECT  57.312 36.528 57.336 36.72 ;
    END
  END dq[429]
  PIN dq[42]
    DIRECTION OUTPUT ;
    USE SIGNAL ;
    PORT
      LAYER M3 ;
        RECT  9.54 36.576 9.558 36.72 ;
    END
  END dq[42]
  PIN dq[430]
    DIRECTION OUTPUT ;
    USE SIGNAL ;
    PORT
      LAYER M3 ;
        RECT  57.456 36.576 57.474 36.72 ;
    END
  END dq[430]
  PIN dq[431]
    DIRECTION OUTPUT ;
    USE SIGNAL ;
    PORT
      LAYER M5 ;
        RECT  57.552 36.528 57.576 36.72 ;
    END
  END dq[431]
  PIN dq[432]
    DIRECTION OUTPUT ;
    USE SIGNAL ;
    PORT
      LAYER M3 ;
        RECT  57.708 36.576 57.726 36.72 ;
    END
  END dq[432]
  PIN dq[433]
    DIRECTION OUTPUT ;
    USE SIGNAL ;
    PORT
      LAYER M5 ;
        RECT  57.792 36.528 57.816 36.72 ;
    END
  END dq[433]
  PIN dq[434]
    DIRECTION OUTPUT ;
    USE SIGNAL ;
    PORT
      LAYER M3 ;
        RECT  57.924 36.576 57.942 36.72 ;
    END
  END dq[434]
  PIN dq[435]
    DIRECTION OUTPUT ;
    USE SIGNAL ;
    PORT
      LAYER M5 ;
        RECT  58.08 36.528 58.104 36.72 ;
    END
  END dq[435]
  PIN dq[436]
    DIRECTION OUTPUT ;
    USE SIGNAL ;
    PORT
      LAYER M3 ;
        RECT  58.176 36.576 58.194 36.72 ;
    END
  END dq[436]
  PIN dq[437]
    DIRECTION OUTPUT ;
    USE SIGNAL ;
    PORT
      LAYER M5 ;
        RECT  58.32 36.528 58.344 36.72 ;
    END
  END dq[437]
  PIN dq[438]
    DIRECTION OUTPUT ;
    USE SIGNAL ;
    PORT
      LAYER M3 ;
        RECT  58.428 36.576 58.446 36.72 ;
    END
  END dq[438]
  PIN dq[439]
    DIRECTION OUTPUT ;
    USE SIGNAL ;
    PORT
      LAYER M5 ;
        RECT  58.56 36.528 58.584 36.72 ;
    END
  END dq[439]
  PIN dq[43]
    DIRECTION OUTPUT ;
    USE SIGNAL ;
    PORT
      LAYER M5 ;
        RECT  9.696 36.528 9.72 36.72 ;
    END
  END dq[43]
  PIN dq[440]
    DIRECTION OUTPUT ;
    USE SIGNAL ;
    PORT
      LAYER M3 ;
        RECT  58.68 36.576 58.698 36.72 ;
    END
  END dq[440]
  PIN dq[441]
    DIRECTION OUTPUT ;
    USE SIGNAL ;
    PORT
      LAYER M5 ;
        RECT  58.8 36.528 58.824 36.72 ;
    END
  END dq[441]
  PIN dq[442]
    DIRECTION OUTPUT ;
    USE SIGNAL ;
    PORT
      LAYER M3 ;
        RECT  58.932 36.576 58.95 36.72 ;
    END
  END dq[442]
  PIN dq[443]
    DIRECTION OUTPUT ;
    USE SIGNAL ;
    PORT
      LAYER M5 ;
        RECT  59.04 36.528 59.064 36.72 ;
    END
  END dq[443]
  PIN dq[444]
    DIRECTION OUTPUT ;
    USE SIGNAL ;
    PORT
      LAYER M3 ;
        RECT  59.184 36.576 59.202 36.72 ;
    END
  END dq[444]
  PIN dq[445]
    DIRECTION OUTPUT ;
    USE SIGNAL ;
    PORT
      LAYER M5 ;
        RECT  59.28 36.528 59.304 36.72 ;
    END
  END dq[445]
  PIN dq[446]
    DIRECTION OUTPUT ;
    USE SIGNAL ;
    PORT
      LAYER M3 ;
        RECT  59.436 36.576 59.454 36.72 ;
    END
  END dq[446]
  PIN dq[447]
    DIRECTION OUTPUT ;
    USE SIGNAL ;
    PORT
      LAYER M5 ;
        RECT  59.52 36.528 59.544 36.72 ;
    END
  END dq[447]
  PIN dq[448]
    DIRECTION OUTPUT ;
    USE SIGNAL ;
    PORT
      LAYER M3 ;
        RECT  59.652 36.576 59.67 36.72 ;
    END
  END dq[448]
  PIN dq[449]
    DIRECTION OUTPUT ;
    USE SIGNAL ;
    PORT
      LAYER M5 ;
        RECT  59.808 36.528 59.832 36.72 ;
    END
  END dq[449]
  PIN dq[44]
    DIRECTION OUTPUT ;
    USE SIGNAL ;
    PORT
      LAYER M3 ;
        RECT  9.792 36.576 9.81 36.72 ;
    END
  END dq[44]
  PIN dq[450]
    DIRECTION OUTPUT ;
    USE SIGNAL ;
    PORT
      LAYER M3 ;
        RECT  59.904 36.576 59.922 36.72 ;
    END
  END dq[450]
  PIN dq[451]
    DIRECTION OUTPUT ;
    USE SIGNAL ;
    PORT
      LAYER M5 ;
        RECT  60.048 36.528 60.072 36.72 ;
    END
  END dq[451]
  PIN dq[452]
    DIRECTION OUTPUT ;
    USE SIGNAL ;
    PORT
      LAYER M3 ;
        RECT  60.156 36.576 60.174 36.72 ;
    END
  END dq[452]
  PIN dq[453]
    DIRECTION OUTPUT ;
    USE SIGNAL ;
    PORT
      LAYER M5 ;
        RECT  60.288 36.528 60.312 36.72 ;
    END
  END dq[453]
  PIN dq[454]
    DIRECTION OUTPUT ;
    USE SIGNAL ;
    PORT
      LAYER M3 ;
        RECT  60.408 36.576 60.426 36.72 ;
    END
  END dq[454]
  PIN dq[455]
    DIRECTION OUTPUT ;
    USE SIGNAL ;
    PORT
      LAYER M5 ;
        RECT  60.528 36.528 60.552 36.72 ;
    END
  END dq[455]
  PIN dq[456]
    DIRECTION OUTPUT ;
    USE SIGNAL ;
    PORT
      LAYER M3 ;
        RECT  60.66 36.576 60.678 36.72 ;
    END
  END dq[456]
  PIN dq[457]
    DIRECTION OUTPUT ;
    USE SIGNAL ;
    PORT
      LAYER M5 ;
        RECT  60.768 36.528 60.792 36.72 ;
    END
  END dq[457]
  PIN dq[458]
    DIRECTION OUTPUT ;
    USE SIGNAL ;
    PORT
      LAYER M3 ;
        RECT  60.912 36.576 60.93 36.72 ;
    END
  END dq[458]
  PIN dq[459]
    DIRECTION OUTPUT ;
    USE SIGNAL ;
    PORT
      LAYER M5 ;
        RECT  61.008 36.528 61.032 36.72 ;
    END
  END dq[459]
  PIN dq[45]
    DIRECTION OUTPUT ;
    USE SIGNAL ;
    PORT
      LAYER M5 ;
        RECT  9.936 36.528 9.96 36.72 ;
    END
  END dq[45]
  PIN dq[460]
    DIRECTION OUTPUT ;
    USE SIGNAL ;
    PORT
      LAYER M3 ;
        RECT  61.164 36.576 61.182 36.72 ;
    END
  END dq[460]
  PIN dq[461]
    DIRECTION OUTPUT ;
    USE SIGNAL ;
    PORT
      LAYER M5 ;
        RECT  61.248 36.528 61.272 36.72 ;
    END
  END dq[461]
  PIN dq[462]
    DIRECTION OUTPUT ;
    USE SIGNAL ;
    PORT
      LAYER M3 ;
        RECT  61.38 36.576 61.398 36.72 ;
    END
  END dq[462]
  PIN dq[463]
    DIRECTION OUTPUT ;
    USE SIGNAL ;
    PORT
      LAYER M5 ;
        RECT  61.536 36.528 61.56 36.72 ;
    END
  END dq[463]
  PIN dq[464]
    DIRECTION OUTPUT ;
    USE SIGNAL ;
    PORT
      LAYER M3 ;
        RECT  61.632 36.576 61.65 36.72 ;
    END
  END dq[464]
  PIN dq[465]
    DIRECTION OUTPUT ;
    USE SIGNAL ;
    PORT
      LAYER M5 ;
        RECT  61.776 36.528 61.8 36.72 ;
    END
  END dq[465]
  PIN dq[466]
    DIRECTION OUTPUT ;
    USE SIGNAL ;
    PORT
      LAYER M3 ;
        RECT  61.884 36.576 61.902 36.72 ;
    END
  END dq[466]
  PIN dq[467]
    DIRECTION OUTPUT ;
    USE SIGNAL ;
    PORT
      LAYER M5 ;
        RECT  62.016 36.528 62.04 36.72 ;
    END
  END dq[467]
  PIN dq[468]
    DIRECTION OUTPUT ;
    USE SIGNAL ;
    PORT
      LAYER M3 ;
        RECT  62.136 36.576 62.154 36.72 ;
    END
  END dq[468]
  PIN dq[469]
    DIRECTION OUTPUT ;
    USE SIGNAL ;
    PORT
      LAYER M5 ;
        RECT  62.256 36.528 62.28 36.72 ;
    END
  END dq[469]
  PIN dq[46]
    DIRECTION OUTPUT ;
    USE SIGNAL ;
    PORT
      LAYER M3 ;
        RECT  10.044 36.576 10.062 36.72 ;
    END
  END dq[46]
  PIN dq[470]
    DIRECTION OUTPUT ;
    USE SIGNAL ;
    PORT
      LAYER M3 ;
        RECT  62.388 36.576 62.406 36.72 ;
    END
  END dq[470]
  PIN dq[471]
    DIRECTION OUTPUT ;
    USE SIGNAL ;
    PORT
      LAYER M5 ;
        RECT  62.496 36.528 62.52 36.72 ;
    END
  END dq[471]
  PIN dq[472]
    DIRECTION OUTPUT ;
    USE SIGNAL ;
    PORT
      LAYER M3 ;
        RECT  62.64 36.576 62.658 36.72 ;
    END
  END dq[472]
  PIN dq[473]
    DIRECTION OUTPUT ;
    USE SIGNAL ;
    PORT
      LAYER M5 ;
        RECT  62.736 36.528 62.76 36.72 ;
    END
  END dq[473]
  PIN dq[474]
    DIRECTION OUTPUT ;
    USE SIGNAL ;
    PORT
      LAYER M3 ;
        RECT  62.892 36.576 62.91 36.72 ;
    END
  END dq[474]
  PIN dq[475]
    DIRECTION OUTPUT ;
    USE SIGNAL ;
    PORT
      LAYER M5 ;
        RECT  62.976 36.528 63 36.72 ;
    END
  END dq[475]
  PIN dq[476]
    DIRECTION OUTPUT ;
    USE SIGNAL ;
    PORT
      LAYER M3 ;
        RECT  63.108 36.576 63.126 36.72 ;
    END
  END dq[476]
  PIN dq[477]
    DIRECTION OUTPUT ;
    USE SIGNAL ;
    PORT
      LAYER M5 ;
        RECT  63.264 36.528 63.288 36.72 ;
    END
  END dq[477]
  PIN dq[478]
    DIRECTION OUTPUT ;
    USE SIGNAL ;
    PORT
      LAYER M3 ;
        RECT  63.36 36.576 63.378 36.72 ;
    END
  END dq[478]
  PIN dq[479]
    DIRECTION OUTPUT ;
    USE SIGNAL ;
    PORT
      LAYER M5 ;
        RECT  63.504 36.528 63.528 36.72 ;
    END
  END dq[479]
  PIN dq[47]
    DIRECTION OUTPUT ;
    USE SIGNAL ;
    PORT
      LAYER M5 ;
        RECT  10.176 36.528 10.2 36.72 ;
    END
  END dq[47]
  PIN dq[480]
    DIRECTION OUTPUT ;
    USE SIGNAL ;
    PORT
      LAYER M3 ;
        RECT  63.612 36.576 63.63 36.72 ;
    END
  END dq[480]
  PIN dq[481]
    DIRECTION OUTPUT ;
    USE SIGNAL ;
    PORT
      LAYER M5 ;
        RECT  63.744 36.528 63.768 36.72 ;
    END
  END dq[481]
  PIN dq[482]
    DIRECTION OUTPUT ;
    USE SIGNAL ;
    PORT
      LAYER M3 ;
        RECT  63.864 36.576 63.882 36.72 ;
    END
  END dq[482]
  PIN dq[483]
    DIRECTION OUTPUT ;
    USE SIGNAL ;
    PORT
      LAYER M5 ;
        RECT  63.984 36.528 64.008 36.72 ;
    END
  END dq[483]
  PIN dq[484]
    DIRECTION OUTPUT ;
    USE SIGNAL ;
    PORT
      LAYER M3 ;
        RECT  64.116 36.576 64.134 36.72 ;
    END
  END dq[484]
  PIN dq[485]
    DIRECTION OUTPUT ;
    USE SIGNAL ;
    PORT
      LAYER M5 ;
        RECT  64.224 36.528 64.248 36.72 ;
    END
  END dq[485]
  PIN dq[486]
    DIRECTION OUTPUT ;
    USE SIGNAL ;
    PORT
      LAYER M3 ;
        RECT  64.368 36.576 64.386 36.72 ;
    END
  END dq[486]
  PIN dq[487]
    DIRECTION OUTPUT ;
    USE SIGNAL ;
    PORT
      LAYER M5 ;
        RECT  64.464 36.528 64.488 36.72 ;
    END
  END dq[487]
  PIN dq[488]
    DIRECTION OUTPUT ;
    USE SIGNAL ;
    PORT
      LAYER M3 ;
        RECT  64.62 36.576 64.638 36.72 ;
    END
  END dq[488]
  PIN dq[489]
    DIRECTION OUTPUT ;
    USE SIGNAL ;
    PORT
      LAYER M5 ;
        RECT  64.704 36.528 64.728 36.72 ;
    END
  END dq[489]
  PIN dq[48]
    DIRECTION OUTPUT ;
    USE SIGNAL ;
    PORT
      LAYER M3 ;
        RECT  10.296 36.576 10.314 36.72 ;
    END
  END dq[48]
  PIN dq[490]
    DIRECTION OUTPUT ;
    USE SIGNAL ;
    PORT
      LAYER M3 ;
        RECT  64.836 36.576 64.854 36.72 ;
    END
  END dq[490]
  PIN dq[491]
    DIRECTION OUTPUT ;
    USE SIGNAL ;
    PORT
      LAYER M5 ;
        RECT  64.992 36.528 65.016 36.72 ;
    END
  END dq[491]
  PIN dq[492]
    DIRECTION OUTPUT ;
    USE SIGNAL ;
    PORT
      LAYER M3 ;
        RECT  65.088 36.576 65.106 36.72 ;
    END
  END dq[492]
  PIN dq[493]
    DIRECTION OUTPUT ;
    USE SIGNAL ;
    PORT
      LAYER M5 ;
        RECT  65.232 36.528 65.256 36.72 ;
    END
  END dq[493]
  PIN dq[494]
    DIRECTION OUTPUT ;
    USE SIGNAL ;
    PORT
      LAYER M3 ;
        RECT  65.34 36.576 65.358 36.72 ;
    END
  END dq[494]
  PIN dq[495]
    DIRECTION OUTPUT ;
    USE SIGNAL ;
    PORT
      LAYER M5 ;
        RECT  65.472 36.528 65.496 36.72 ;
    END
  END dq[495]
  PIN dq[496]
    DIRECTION OUTPUT ;
    USE SIGNAL ;
    PORT
      LAYER M3 ;
        RECT  65.592 36.576 65.61 36.72 ;
    END
  END dq[496]
  PIN dq[497]
    DIRECTION OUTPUT ;
    USE SIGNAL ;
    PORT
      LAYER M5 ;
        RECT  65.712 36.528 65.736 36.72 ;
    END
  END dq[497]
  PIN dq[498]
    DIRECTION OUTPUT ;
    USE SIGNAL ;
    PORT
      LAYER M3 ;
        RECT  65.844 36.576 65.862 36.72 ;
    END
  END dq[498]
  PIN dq[499]
    DIRECTION OUTPUT ;
    USE SIGNAL ;
    PORT
      LAYER M5 ;
        RECT  65.952 36.528 65.976 36.72 ;
    END
  END dq[499]
  PIN dq[49]
    DIRECTION OUTPUT ;
    USE SIGNAL ;
    PORT
      LAYER M5 ;
        RECT  10.416 36.528 10.44 36.72 ;
    END
  END dq[49]
  PIN dq[4]
    DIRECTION OUTPUT ;
    USE SIGNAL ;
    PORT
      LAYER M3 ;
        RECT  4.86 36.576 4.878 36.72 ;
    END
  END dq[4]
  PIN dq[500]
    DIRECTION OUTPUT ;
    USE SIGNAL ;
    PORT
      LAYER M3 ;
        RECT  66.096 36.576 66.114 36.72 ;
    END
  END dq[500]
  PIN dq[501]
    DIRECTION OUTPUT ;
    USE SIGNAL ;
    PORT
      LAYER M5 ;
        RECT  66.192 36.528 66.216 36.72 ;
    END
  END dq[501]
  PIN dq[502]
    DIRECTION OUTPUT ;
    USE SIGNAL ;
    PORT
      LAYER M3 ;
        RECT  66.348 36.576 66.366 36.72 ;
    END
  END dq[502]
  PIN dq[503]
    DIRECTION OUTPUT ;
    USE SIGNAL ;
    PORT
      LAYER M5 ;
        RECT  66.432 36.528 66.456 36.72 ;
    END
  END dq[503]
  PIN dq[504]
    DIRECTION OUTPUT ;
    USE SIGNAL ;
    PORT
      LAYER M3 ;
        RECT  66.564 36.576 66.582 36.72 ;
    END
  END dq[504]
  PIN dq[505]
    DIRECTION OUTPUT ;
    USE SIGNAL ;
    PORT
      LAYER M5 ;
        RECT  66.72 36.528 66.744 36.72 ;
    END
  END dq[505]
  PIN dq[506]
    DIRECTION OUTPUT ;
    USE SIGNAL ;
    PORT
      LAYER M3 ;
        RECT  66.816 36.576 66.834 36.72 ;
    END
  END dq[506]
  PIN dq[507]
    DIRECTION OUTPUT ;
    USE SIGNAL ;
    PORT
      LAYER M5 ;
        RECT  66.96 36.528 66.984 36.72 ;
    END
  END dq[507]
  PIN dq[508]
    DIRECTION OUTPUT ;
    USE SIGNAL ;
    PORT
      LAYER M3 ;
        RECT  67.068 36.576 67.086 36.72 ;
    END
  END dq[508]
  PIN dq[509]
    DIRECTION OUTPUT ;
    USE SIGNAL ;
    PORT
      LAYER M5 ;
        RECT  67.2 36.528 67.224 36.72 ;
    END
  END dq[509]
  PIN dq[50]
    DIRECTION OUTPUT ;
    USE SIGNAL ;
    PORT
      LAYER M3 ;
        RECT  10.548 36.576 10.566 36.72 ;
    END
  END dq[50]
  PIN dq[510]
    DIRECTION OUTPUT ;
    USE SIGNAL ;
    PORT
      LAYER M3 ;
        RECT  67.32 36.576 67.338 36.72 ;
    END
  END dq[510]
  PIN dq[511]
    DIRECTION OUTPUT ;
    USE SIGNAL ;
    PORT
      LAYER M5 ;
        RECT  67.44 36.528 67.464 36.72 ;
    END
  END dq[511]
  PIN dq[512]
    DIRECTION OUTPUT ;
    USE SIGNAL ;
    PORT
      LAYER M3 ;
        RECT  67.572 36.576 67.59 36.72 ;
    END
  END dq[512]
  PIN dq[513]
    DIRECTION OUTPUT ;
    USE SIGNAL ;
    PORT
      LAYER M5 ;
        RECT  67.68 36.528 67.704 36.72 ;
    END
  END dq[513]
  PIN dq[514]
    DIRECTION OUTPUT ;
    USE SIGNAL ;
    PORT
      LAYER M3 ;
        RECT  67.824 36.576 67.842 36.72 ;
    END
  END dq[514]
  PIN dq[515]
    DIRECTION OUTPUT ;
    USE SIGNAL ;
    PORT
      LAYER M5 ;
        RECT  67.92 36.528 67.944 36.72 ;
    END
  END dq[515]
  PIN dq[516]
    DIRECTION OUTPUT ;
    USE SIGNAL ;
    PORT
      LAYER M3 ;
        RECT  68.076 36.576 68.094 36.72 ;
    END
  END dq[516]
  PIN dq[517]
    DIRECTION OUTPUT ;
    USE SIGNAL ;
    PORT
      LAYER M5 ;
        RECT  68.16 36.528 68.184 36.72 ;
    END
  END dq[517]
  PIN dq[518]
    DIRECTION OUTPUT ;
    USE SIGNAL ;
    PORT
      LAYER M3 ;
        RECT  68.292 36.576 68.31 36.72 ;
    END
  END dq[518]
  PIN dq[519]
    DIRECTION OUTPUT ;
    USE SIGNAL ;
    PORT
      LAYER M5 ;
        RECT  68.448 36.528 68.472 36.72 ;
    END
  END dq[519]
  PIN dq[51]
    DIRECTION OUTPUT ;
    USE SIGNAL ;
    PORT
      LAYER M5 ;
        RECT  10.656 36.528 10.68 36.72 ;
    END
  END dq[51]
  PIN dq[520]
    DIRECTION OUTPUT ;
    USE SIGNAL ;
    PORT
      LAYER M3 ;
        RECT  68.544 36.576 68.562 36.72 ;
    END
  END dq[520]
  PIN dq[521]
    DIRECTION OUTPUT ;
    USE SIGNAL ;
    PORT
      LAYER M5 ;
        RECT  68.688 36.528 68.712 36.72 ;
    END
  END dq[521]
  PIN dq[522]
    DIRECTION OUTPUT ;
    USE SIGNAL ;
    PORT
      LAYER M3 ;
        RECT  68.796 36.576 68.814 36.72 ;
    END
  END dq[522]
  PIN dq[523]
    DIRECTION OUTPUT ;
    USE SIGNAL ;
    PORT
      LAYER M5 ;
        RECT  68.928 36.528 68.952 36.72 ;
    END
  END dq[523]
  PIN dq[524]
    DIRECTION OUTPUT ;
    USE SIGNAL ;
    PORT
      LAYER M3 ;
        RECT  69.048 36.576 69.066 36.72 ;
    END
  END dq[524]
  PIN dq[525]
    DIRECTION OUTPUT ;
    USE SIGNAL ;
    PORT
      LAYER M5 ;
        RECT  69.168 36.528 69.192 36.72 ;
    END
  END dq[525]
  PIN dq[526]
    DIRECTION OUTPUT ;
    USE SIGNAL ;
    PORT
      LAYER M3 ;
        RECT  69.3 36.576 69.318 36.72 ;
    END
  END dq[526]
  PIN dq[527]
    DIRECTION OUTPUT ;
    USE SIGNAL ;
    PORT
      LAYER M5 ;
        RECT  69.408 36.528 69.432 36.72 ;
    END
  END dq[527]
  PIN dq[528]
    DIRECTION OUTPUT ;
    USE SIGNAL ;
    PORT
      LAYER M3 ;
        RECT  69.552 36.576 69.57 36.72 ;
    END
  END dq[528]
  PIN dq[529]
    DIRECTION OUTPUT ;
    USE SIGNAL ;
    PORT
      LAYER M5 ;
        RECT  69.648 36.528 69.672 36.72 ;
    END
  END dq[529]
  PIN dq[52]
    DIRECTION OUTPUT ;
    USE SIGNAL ;
    PORT
      LAYER M3 ;
        RECT  10.8 36.576 10.818 36.72 ;
    END
  END dq[52]
  PIN dq[530]
    DIRECTION OUTPUT ;
    USE SIGNAL ;
    PORT
      LAYER M3 ;
        RECT  69.804 36.576 69.822 36.72 ;
    END
  END dq[530]
  PIN dq[531]
    DIRECTION OUTPUT ;
    USE SIGNAL ;
    PORT
      LAYER M5 ;
        RECT  69.888 36.528 69.912 36.72 ;
    END
  END dq[531]
  PIN dq[532]
    DIRECTION OUTPUT ;
    USE SIGNAL ;
    PORT
      LAYER M3 ;
        RECT  70.02 36.576 70.038 36.72 ;
    END
  END dq[532]
  PIN dq[533]
    DIRECTION OUTPUT ;
    USE SIGNAL ;
    PORT
      LAYER M5 ;
        RECT  70.176 36.528 70.2 36.72 ;
    END
  END dq[533]
  PIN dq[534]
    DIRECTION OUTPUT ;
    USE SIGNAL ;
    PORT
      LAYER M3 ;
        RECT  70.272 36.576 70.29 36.72 ;
    END
  END dq[534]
  PIN dq[535]
    DIRECTION OUTPUT ;
    USE SIGNAL ;
    PORT
      LAYER M5 ;
        RECT  70.416 36.528 70.44 36.72 ;
    END
  END dq[535]
  PIN dq[536]
    DIRECTION OUTPUT ;
    USE SIGNAL ;
    PORT
      LAYER M3 ;
        RECT  70.524 36.576 70.542 36.72 ;
    END
  END dq[536]
  PIN dq[537]
    DIRECTION OUTPUT ;
    USE SIGNAL ;
    PORT
      LAYER M5 ;
        RECT  70.656 36.528 70.68 36.72 ;
    END
  END dq[537]
  PIN dq[538]
    DIRECTION OUTPUT ;
    USE SIGNAL ;
    PORT
      LAYER M3 ;
        RECT  70.776 36.576 70.794 36.72 ;
    END
  END dq[538]
  PIN dq[539]
    DIRECTION OUTPUT ;
    USE SIGNAL ;
    PORT
      LAYER M5 ;
        RECT  70.896 36.528 70.92 36.72 ;
    END
  END dq[539]
  PIN dq[53]
    DIRECTION OUTPUT ;
    USE SIGNAL ;
    PORT
      LAYER M5 ;
        RECT  10.896 36.528 10.92 36.72 ;
    END
  END dq[53]
  PIN dq[540]
    DIRECTION OUTPUT ;
    USE SIGNAL ;
    PORT
      LAYER M3 ;
        RECT  71.028 36.576 71.046 36.72 ;
    END
  END dq[540]
  PIN dq[541]
    DIRECTION OUTPUT ;
    USE SIGNAL ;
    PORT
      LAYER M5 ;
        RECT  71.136 36.528 71.16 36.72 ;
    END
  END dq[541]
  PIN dq[542]
    DIRECTION OUTPUT ;
    USE SIGNAL ;
    PORT
      LAYER M3 ;
        RECT  71.28 36.576 71.298 36.72 ;
    END
  END dq[542]
  PIN dq[543]
    DIRECTION OUTPUT ;
    USE SIGNAL ;
    PORT
      LAYER M5 ;
        RECT  71.376 36.528 71.4 36.72 ;
    END
  END dq[543]
  PIN dq[544]
    DIRECTION OUTPUT ;
    USE SIGNAL ;
    PORT
      LAYER M3 ;
        RECT  71.532 36.576 71.55 36.72 ;
    END
  END dq[544]
  PIN dq[545]
    DIRECTION OUTPUT ;
    USE SIGNAL ;
    PORT
      LAYER M5 ;
        RECT  71.616 36.528 71.64 36.72 ;
    END
  END dq[545]
  PIN dq[546]
    DIRECTION OUTPUT ;
    USE SIGNAL ;
    PORT
      LAYER M3 ;
        RECT  71.748 36.576 71.766 36.72 ;
    END
  END dq[546]
  PIN dq[547]
    DIRECTION OUTPUT ;
    USE SIGNAL ;
    PORT
      LAYER M5 ;
        RECT  71.904 36.528 71.928 36.72 ;
    END
  END dq[547]
  PIN dq[548]
    DIRECTION OUTPUT ;
    USE SIGNAL ;
    PORT
      LAYER M3 ;
        RECT  72 36.576 72.018 36.72 ;
    END
  END dq[548]
  PIN dq[549]
    DIRECTION OUTPUT ;
    USE SIGNAL ;
    PORT
      LAYER M5 ;
        RECT  72.144 36.528 72.168 36.72 ;
    END
  END dq[549]
  PIN dq[54]
    DIRECTION OUTPUT ;
    USE SIGNAL ;
    PORT
      LAYER M3 ;
        RECT  11.052 36.576 11.07 36.72 ;
    END
  END dq[54]
  PIN dq[550]
    DIRECTION OUTPUT ;
    USE SIGNAL ;
    PORT
      LAYER M3 ;
        RECT  72.252 36.576 72.27 36.72 ;
    END
  END dq[550]
  PIN dq[551]
    DIRECTION OUTPUT ;
    USE SIGNAL ;
    PORT
      LAYER M5 ;
        RECT  72.384 36.528 72.408 36.72 ;
    END
  END dq[551]
  PIN dq[552]
    DIRECTION OUTPUT ;
    USE SIGNAL ;
    PORT
      LAYER M3 ;
        RECT  72.504 36.576 72.522 36.72 ;
    END
  END dq[552]
  PIN dq[553]
    DIRECTION OUTPUT ;
    USE SIGNAL ;
    PORT
      LAYER M5 ;
        RECT  72.624 36.528 72.648 36.72 ;
    END
  END dq[553]
  PIN dq[554]
    DIRECTION OUTPUT ;
    USE SIGNAL ;
    PORT
      LAYER M3 ;
        RECT  72.756 36.576 72.774 36.72 ;
    END
  END dq[554]
  PIN dq[555]
    DIRECTION OUTPUT ;
    USE SIGNAL ;
    PORT
      LAYER M5 ;
        RECT  72.864 36.528 72.888 36.72 ;
    END
  END dq[555]
  PIN dq[556]
    DIRECTION OUTPUT ;
    USE SIGNAL ;
    PORT
      LAYER M3 ;
        RECT  73.008 36.576 73.026 36.72 ;
    END
  END dq[556]
  PIN dq[557]
    DIRECTION OUTPUT ;
    USE SIGNAL ;
    PORT
      LAYER M5 ;
        RECT  73.104 36.528 73.128 36.72 ;
    END
  END dq[557]
  PIN dq[558]
    DIRECTION OUTPUT ;
    USE SIGNAL ;
    PORT
      LAYER M3 ;
        RECT  73.26 36.576 73.278 36.72 ;
    END
  END dq[558]
  PIN dq[559]
    DIRECTION OUTPUT ;
    USE SIGNAL ;
    PORT
      LAYER M5 ;
        RECT  73.344 36.528 73.368 36.72 ;
    END
  END dq[559]
  PIN dq[55]
    DIRECTION OUTPUT ;
    USE SIGNAL ;
    PORT
      LAYER M5 ;
        RECT  11.136 36.528 11.16 36.72 ;
    END
  END dq[55]
  PIN dq[56]
    DIRECTION OUTPUT ;
    USE SIGNAL ;
    PORT
      LAYER M3 ;
        RECT  11.268 36.576 11.286 36.72 ;
    END
  END dq[56]
  PIN dq[57]
    DIRECTION OUTPUT ;
    USE SIGNAL ;
    PORT
      LAYER M5 ;
        RECT  11.424 36.528 11.448 36.72 ;
    END
  END dq[57]
  PIN dq[58]
    DIRECTION OUTPUT ;
    USE SIGNAL ;
    PORT
      LAYER M3 ;
        RECT  11.52 36.576 11.538 36.72 ;
    END
  END dq[58]
  PIN dq[59]
    DIRECTION OUTPUT ;
    USE SIGNAL ;
    PORT
      LAYER M5 ;
        RECT  11.664 36.528 11.688 36.72 ;
    END
  END dq[59]
  PIN dq[5]
    DIRECTION OUTPUT ;
    USE SIGNAL ;
    PORT
      LAYER M5 ;
        RECT  4.992 36.528 5.016 36.72 ;
    END
  END dq[5]
  PIN dq[60]
    DIRECTION OUTPUT ;
    USE SIGNAL ;
    PORT
      LAYER M3 ;
        RECT  11.772 36.576 11.79 36.72 ;
    END
  END dq[60]
  PIN dq[61]
    DIRECTION OUTPUT ;
    USE SIGNAL ;
    PORT
      LAYER M5 ;
        RECT  11.904 36.528 11.928 36.72 ;
    END
  END dq[61]
  PIN dq[62]
    DIRECTION OUTPUT ;
    USE SIGNAL ;
    PORT
      LAYER M3 ;
        RECT  12.024 36.576 12.042 36.72 ;
    END
  END dq[62]
  PIN dq[63]
    DIRECTION OUTPUT ;
    USE SIGNAL ;
    PORT
      LAYER M5 ;
        RECT  12.144 36.528 12.168 36.72 ;
    END
  END dq[63]
  PIN dq[64]
    DIRECTION OUTPUT ;
    USE SIGNAL ;
    PORT
      LAYER M3 ;
        RECT  12.276 36.576 12.294 36.72 ;
    END
  END dq[64]
  PIN dq[65]
    DIRECTION OUTPUT ;
    USE SIGNAL ;
    PORT
      LAYER M5 ;
        RECT  12.384 36.528 12.408 36.72 ;
    END
  END dq[65]
  PIN dq[66]
    DIRECTION OUTPUT ;
    USE SIGNAL ;
    PORT
      LAYER M3 ;
        RECT  12.528 36.576 12.546 36.72 ;
    END
  END dq[66]
  PIN dq[67]
    DIRECTION OUTPUT ;
    USE SIGNAL ;
    PORT
      LAYER M5 ;
        RECT  12.624 36.528 12.648 36.72 ;
    END
  END dq[67]
  PIN dq[68]
    DIRECTION OUTPUT ;
    USE SIGNAL ;
    PORT
      LAYER M3 ;
        RECT  12.78 36.576 12.798 36.72 ;
    END
  END dq[68]
  PIN dq[69]
    DIRECTION OUTPUT ;
    USE SIGNAL ;
    PORT
      LAYER M5 ;
        RECT  12.864 36.528 12.888 36.72 ;
    END
  END dq[69]
  PIN dq[6]
    DIRECTION OUTPUT ;
    USE SIGNAL ;
    PORT
      LAYER M3 ;
        RECT  5.112 36.576 5.13 36.72 ;
    END
  END dq[6]
  PIN dq[70]
    DIRECTION OUTPUT ;
    USE SIGNAL ;
    PORT
      LAYER M3 ;
        RECT  12.996 36.576 13.014 36.72 ;
    END
  END dq[70]
  PIN dq[71]
    DIRECTION OUTPUT ;
    USE SIGNAL ;
    PORT
      LAYER M5 ;
        RECT  13.152 36.528 13.176 36.72 ;
    END
  END dq[71]
  PIN dq[72]
    DIRECTION OUTPUT ;
    USE SIGNAL ;
    PORT
      LAYER M3 ;
        RECT  13.248 36.576 13.266 36.72 ;
    END
  END dq[72]
  PIN dq[73]
    DIRECTION OUTPUT ;
    USE SIGNAL ;
    PORT
      LAYER M5 ;
        RECT  13.392 36.528 13.416 36.72 ;
    END
  END dq[73]
  PIN dq[74]
    DIRECTION OUTPUT ;
    USE SIGNAL ;
    PORT
      LAYER M3 ;
        RECT  13.5 36.576 13.518 36.72 ;
    END
  END dq[74]
  PIN dq[75]
    DIRECTION OUTPUT ;
    USE SIGNAL ;
    PORT
      LAYER M5 ;
        RECT  13.632 36.528 13.656 36.72 ;
    END
  END dq[75]
  PIN dq[76]
    DIRECTION OUTPUT ;
    USE SIGNAL ;
    PORT
      LAYER M3 ;
        RECT  13.752 36.576 13.77 36.72 ;
    END
  END dq[76]
  PIN dq[77]
    DIRECTION OUTPUT ;
    USE SIGNAL ;
    PORT
      LAYER M5 ;
        RECT  13.872 36.528 13.896 36.72 ;
    END
  END dq[77]
  PIN dq[78]
    DIRECTION OUTPUT ;
    USE SIGNAL ;
    PORT
      LAYER M3 ;
        RECT  14.004 36.576 14.022 36.72 ;
    END
  END dq[78]
  PIN dq[79]
    DIRECTION OUTPUT ;
    USE SIGNAL ;
    PORT
      LAYER M5 ;
        RECT  14.112 36.528 14.136 36.72 ;
    END
  END dq[79]
  PIN dq[7]
    DIRECTION OUTPUT ;
    USE SIGNAL ;
    PORT
      LAYER M5 ;
        RECT  5.232 36.528 5.256 36.72 ;
    END
  END dq[7]
  PIN dq[80]
    DIRECTION OUTPUT ;
    USE SIGNAL ;
    PORT
      LAYER M3 ;
        RECT  14.256 36.576 14.274 36.72 ;
    END
  END dq[80]
  PIN dq[81]
    DIRECTION OUTPUT ;
    USE SIGNAL ;
    PORT
      LAYER M5 ;
        RECT  14.352 36.528 14.376 36.72 ;
    END
  END dq[81]
  PIN dq[82]
    DIRECTION OUTPUT ;
    USE SIGNAL ;
    PORT
      LAYER M3 ;
        RECT  14.508 36.576 14.526 36.72 ;
    END
  END dq[82]
  PIN dq[83]
    DIRECTION OUTPUT ;
    USE SIGNAL ;
    PORT
      LAYER M5 ;
        RECT  14.592 36.528 14.616 36.72 ;
    END
  END dq[83]
  PIN dq[84]
    DIRECTION OUTPUT ;
    USE SIGNAL ;
    PORT
      LAYER M3 ;
        RECT  14.724 36.576 14.742 36.72 ;
    END
  END dq[84]
  PIN dq[85]
    DIRECTION OUTPUT ;
    USE SIGNAL ;
    PORT
      LAYER M5 ;
        RECT  14.88 36.528 14.904 36.72 ;
    END
  END dq[85]
  PIN dq[86]
    DIRECTION OUTPUT ;
    USE SIGNAL ;
    PORT
      LAYER M3 ;
        RECT  14.976 36.576 14.994 36.72 ;
    END
  END dq[86]
  PIN dq[87]
    DIRECTION OUTPUT ;
    USE SIGNAL ;
    PORT
      LAYER M5 ;
        RECT  15.12 36.528 15.144 36.72 ;
    END
  END dq[87]
  PIN dq[88]
    DIRECTION OUTPUT ;
    USE SIGNAL ;
    PORT
      LAYER M3 ;
        RECT  15.228 36.576 15.246 36.72 ;
    END
  END dq[88]
  PIN dq[89]
    DIRECTION OUTPUT ;
    USE SIGNAL ;
    PORT
      LAYER M5 ;
        RECT  15.36 36.528 15.384 36.72 ;
    END
  END dq[89]
  PIN dq[8]
    DIRECTION OUTPUT ;
    USE SIGNAL ;
    PORT
      LAYER M3 ;
        RECT  5.364 36.576 5.382 36.72 ;
    END
  END dq[8]
  PIN dq[90]
    DIRECTION OUTPUT ;
    USE SIGNAL ;
    PORT
      LAYER M3 ;
        RECT  15.48 36.576 15.498 36.72 ;
    END
  END dq[90]
  PIN dq[91]
    DIRECTION OUTPUT ;
    USE SIGNAL ;
    PORT
      LAYER M5 ;
        RECT  15.6 36.528 15.624 36.72 ;
    END
  END dq[91]
  PIN dq[92]
    DIRECTION OUTPUT ;
    USE SIGNAL ;
    PORT
      LAYER M3 ;
        RECT  15.732 36.576 15.75 36.72 ;
    END
  END dq[92]
  PIN dq[93]
    DIRECTION OUTPUT ;
    USE SIGNAL ;
    PORT
      LAYER M5 ;
        RECT  15.84 36.528 15.864 36.72 ;
    END
  END dq[93]
  PIN dq[94]
    DIRECTION OUTPUT ;
    USE SIGNAL ;
    PORT
      LAYER M3 ;
        RECT  15.984 36.576 16.002 36.72 ;
    END
  END dq[94]
  PIN dq[95]
    DIRECTION OUTPUT ;
    USE SIGNAL ;
    PORT
      LAYER M5 ;
        RECT  16.08 36.528 16.104 36.72 ;
    END
  END dq[95]
  PIN dq[96]
    DIRECTION OUTPUT ;
    USE SIGNAL ;
    PORT
      LAYER M3 ;
        RECT  16.236 36.576 16.254 36.72 ;
    END
  END dq[96]
  PIN dq[97]
    DIRECTION OUTPUT ;
    USE SIGNAL ;
    PORT
      LAYER M5 ;
        RECT  16.32 36.528 16.344 36.72 ;
    END
  END dq[97]
  PIN dq[98]
    DIRECTION OUTPUT ;
    USE SIGNAL ;
    PORT
      LAYER M3 ;
        RECT  16.452 36.576 16.47 36.72 ;
    END
  END dq[98]
  PIN dq[99]
    DIRECTION OUTPUT ;
    USE SIGNAL ;
    PORT
      LAYER M5 ;
        RECT  16.608 36.528 16.632 36.72 ;
    END
  END dq[99]
  PIN dq[9]
    DIRECTION OUTPUT ;
    USE SIGNAL ;
    PORT
      LAYER M5 ;
        RECT  5.472 36.528 5.496 36.72 ;
    END
  END dq[9]
  PIN VDD
    DIRECTION INOUT ;
    USE POWER ;
    PORT
      LAYER M5 ;
        RECT  75.492 2.151 75.612 34.569 ;
        RECT  72.792 2.151 72.912 34.569 ;
        RECT  70.092 2.151 70.212 34.569 ;
        RECT  67.392 2.151 67.512 34.569 ;
        RECT  64.692 2.151 64.812 34.569 ;
        RECT  61.992 2.151 62.112 34.569 ;
        RECT  59.292 2.151 59.412 34.569 ;
        RECT  56.592 2.151 56.712 34.569 ;
        RECT  53.892 2.151 54.012 34.569 ;
        RECT  51.192 2.151 51.312 34.569 ;
        RECT  48.492 2.151 48.612 34.569 ;
        RECT  45.792 2.151 45.912 34.569 ;
        RECT  43.092 2.151 43.212 34.569 ;
        RECT  40.392 2.151 40.512 34.569 ;
        RECT  37.692 2.151 37.812 34.569 ;
        RECT  34.992 2.151 35.112 34.569 ;
        RECT  32.292 2.151 32.412 34.569 ;
        RECT  29.592 2.151 29.712 34.569 ;
        RECT  26.892 2.151 27.012 34.569 ;
        RECT  24.192 2.151 24.312 34.569 ;
        RECT  21.492 2.151 21.612 34.569 ;
        RECT  18.792 2.151 18.912 34.569 ;
        RECT  16.092 2.151 16.212 34.569 ;
        RECT  13.392 2.151 13.512 34.569 ;
        RECT  10.692 2.151 10.812 34.569 ;
        RECT  7.992 2.151 8.112 34.569 ;
        RECT  5.292 2.151 5.412 34.569 ;
        RECT  2.592 2.151 2.712 34.569 ;
    END
  END VDD
  PIN VSS
    DIRECTION INOUT ;
    USE GROUND ;
    PORT
      LAYER M5 ;
        RECT  75.3 2.137 75.42 34.583 ;
        RECT  72.6 2.137 72.72 34.583 ;
        RECT  69.9 2.137 70.02 34.583 ;
        RECT  67.2 2.137 67.32 34.583 ;
        RECT  64.5 2.137 64.62 34.583 ;
        RECT  61.8 2.137 61.92 34.583 ;
        RECT  59.1 2.137 59.22 34.583 ;
        RECT  56.4 2.137 56.52 34.583 ;
        RECT  53.7 2.137 53.82 34.583 ;
        RECT  51 2.137 51.12 34.583 ;
        RECT  48.3 2.137 48.42 34.583 ;
        RECT  45.6 2.137 45.72 34.583 ;
        RECT  42.9 2.137 43.02 34.583 ;
        RECT  40.2 2.137 40.32 34.583 ;
        RECT  37.5 2.137 37.62 34.583 ;
        RECT  34.8 2.137 34.92 34.583 ;
        RECT  32.1 2.137 32.22 34.583 ;
        RECT  29.4 2.137 29.52 34.583 ;
        RECT  26.7 2.137 26.82 34.583 ;
        RECT  24 2.137 24.12 34.583 ;
        RECT  21.3 2.137 21.42 34.583 ;
        RECT  18.6 2.137 18.72 34.583 ;
        RECT  15.9 2.137 16.02 34.583 ;
        RECT  13.2 2.137 13.32 34.583 ;
        RECT  10.5 2.137 10.62 34.583 ;
        RECT  7.8 2.137 7.92 34.583 ;
        RECT  5.1 2.137 5.22 34.583 ;
        RECT  2.4 2.137 2.52 34.583 ;
    END
  END VSS
  # OT_OBS_CLOSED layer=M5 d_um=1.536 added=117
  OBS
    LAYER RVTN ;
     RECT  2.16 2.16 75.6 2.295 ;
     RECT  2.16 2.565 75.6 2.835 ;
     RECT  2.16 3.105 75.6 3.375 ;
     RECT  2.16 3.645 75.6 3.915 ;
     RECT  2.16 4.185 75.6 4.455 ;
     RECT  2.16 4.725 75.6 4.995 ;
     RECT  2.16 5.265 75.6 5.535 ;
     RECT  2.16 5.805 75.6 6.075 ;
     RECT  2.16 6.345 75.6 6.615 ;
     RECT  2.16 6.885 75.6 7.155 ;
     RECT  2.16 7.425 75.6 7.695 ;
     RECT  2.16 7.965 75.6 8.235 ;
     RECT  2.16 8.505 75.6 8.775 ;
     RECT  2.16 9.045 75.6 9.315 ;
     RECT  2.16 9.585 75.6 9.855 ;
     RECT  2.16 10.125 75.6 10.395 ;
     RECT  2.16 10.665 75.6 10.935 ;
     RECT  2.16 11.205 75.6 11.475 ;
     RECT  2.16 11.745 75.6 12.015 ;
     RECT  2.16 12.285 75.6 12.555 ;
     RECT  2.16 12.825 75.6 13.095 ;
     RECT  2.16 13.365 75.6 13.635 ;
     RECT  2.16 13.905 75.6 14.175 ;
     RECT  2.16 14.445 75.6 14.715 ;
     RECT  2.16 14.985 75.6 15.255 ;
     RECT  2.16 15.525 75.6 15.795 ;
     RECT  2.16 16.065 75.6 16.335 ;
     RECT  2.16 16.605 75.6 16.875 ;
     RECT  2.16 17.145 75.6 17.415 ;
     RECT  2.16 17.685 75.6 17.955 ;
     RECT  2.16 18.225 75.6 18.495 ;
     RECT  2.16 18.765 75.6 19.035 ;
     RECT  2.16 19.305 75.6 19.575 ;
     RECT  2.16 19.845 75.6 20.115 ;
     RECT  2.16 20.385 75.6 20.655 ;
     RECT  2.16 20.925 75.6 21.195 ;
     RECT  2.16 21.465 75.6 21.735 ;
     RECT  2.16 22.005 75.6 22.275 ;
     RECT  2.16 22.545 75.6 22.815 ;
     RECT  2.16 23.085 75.6 23.355 ;
     RECT  2.16 23.625 75.6 23.895 ;
     RECT  2.16 24.165 75.6 24.435 ;
     RECT  2.16 24.705 75.6 24.975 ;
     RECT  2.16 25.245 75.6 25.515 ;
     RECT  2.16 25.785 75.6 26.055 ;
     RECT  2.16 26.325 75.6 26.595 ;
     RECT  2.16 26.865 75.6 27.135 ;
     RECT  2.16 27.405 75.6 27.675 ;
     RECT  2.16 27.945 75.6 28.215 ;
     RECT  2.16 28.485 75.6 28.755 ;
     RECT  2.16 29.025 75.6 29.295 ;
     RECT  2.16 29.565 75.6 29.835 ;
     RECT  2.16 30.105 75.6 30.375 ;
     RECT  2.16 30.645 75.6 30.915 ;
     RECT  2.16 31.185 75.6 31.455 ;
     RECT  2.16 31.725 75.6 31.995 ;
     RECT  2.16 32.265 75.6 32.535 ;
     RECT  2.16 32.805 75.6 33.075 ;
     RECT  2.16 33.345 75.6 33.615 ;
     RECT  2.16 33.885 75.6 34.155 ;
     RECT  2.16 34.425 75.6 34.56 ;
    LAYER RVTP ;
     RECT  2.16 2.295 75.6 2.565 ;
     RECT  2.16 2.835 75.6 3.105 ;
     RECT  2.16 3.375 75.6 3.645 ;
     RECT  2.16 3.915 75.6 4.185 ;
     RECT  2.16 4.455 75.6 4.725 ;
     RECT  2.16 4.995 75.6 5.265 ;
     RECT  2.16 5.535 75.6 5.805 ;
     RECT  2.16 6.075 75.6 6.345 ;
     RECT  2.16 6.615 75.6 6.885 ;
     RECT  2.16 7.155 75.6 7.425 ;
     RECT  2.16 7.695 75.6 7.965 ;
     RECT  2.16 8.235 75.6 8.505 ;
     RECT  2.16 8.775 75.6 9.045 ;
     RECT  2.16 9.315 75.6 9.585 ;
     RECT  2.16 9.855 75.6 10.125 ;
     RECT  2.16 10.395 75.6 10.665 ;
     RECT  2.16 10.935 75.6 11.205 ;
     RECT  2.16 11.475 75.6 11.745 ;
     RECT  2.16 12.015 75.6 12.285 ;
     RECT  2.16 12.555 75.6 12.825 ;
     RECT  2.16 13.095 75.6 13.365 ;
     RECT  2.16 13.635 75.6 13.905 ;
     RECT  2.16 14.175 75.6 14.445 ;
     RECT  2.16 14.715 75.6 14.985 ;
     RECT  2.16 15.255 75.6 15.525 ;
     RECT  2.16 15.795 75.6 16.065 ;
     RECT  2.16 16.335 75.6 16.605 ;
     RECT  2.16 16.875 75.6 17.145 ;
     RECT  2.16 17.415 75.6 17.685 ;
     RECT  2.16 17.955 75.6 18.225 ;
     RECT  2.16 18.495 75.6 18.765 ;
     RECT  2.16 19.035 75.6 19.305 ;
     RECT  2.16 19.575 75.6 19.845 ;
     RECT  2.16 20.115 75.6 20.385 ;
     RECT  2.16 20.655 75.6 20.925 ;
     RECT  2.16 21.195 75.6 21.465 ;
     RECT  2.16 21.735 75.6 22.005 ;
     RECT  2.16 22.275 75.6 22.545 ;
     RECT  2.16 22.815 75.6 23.085 ;
     RECT  2.16 23.355 75.6 23.625 ;
     RECT  2.16 23.895 75.6 24.165 ;
     RECT  2.16 24.435 75.6 24.705 ;
     RECT  2.16 24.975 75.6 25.245 ;
     RECT  2.16 25.515 75.6 25.785 ;
     RECT  2.16 26.055 75.6 26.325 ;
     RECT  2.16 26.595 75.6 26.865 ;
     RECT  2.16 27.135 75.6 27.405 ;
     RECT  2.16 27.675 75.6 27.945 ;
     RECT  2.16 28.215 75.6 28.485 ;
     RECT  2.16 28.755 75.6 29.025 ;
     RECT  2.16 29.295 75.6 29.565 ;
     RECT  2.16 29.835 75.6 30.105 ;
     RECT  2.16 30.375 75.6 30.645 ;
     RECT  2.16 30.915 75.6 31.185 ;
     RECT  2.16 31.455 75.6 31.725 ;
     RECT  2.16 31.995 75.6 32.265 ;
     RECT  2.16 32.535 75.6 32.805 ;
     RECT  2.16 33.075 75.6 33.345 ;
     RECT  2.16 33.615 75.6 33.885 ;
     RECT  2.16 34.155 75.6 34.425 ;
    LAYER M1 ;
     RECT  2.16 2.151 75.6 34.569 ;
    LAYER M2 ;
     RECT  2.16 2.151 3.847 34.569 ;
     RECT  3.847 2.106 4.351 34.569 ;
     RECT  4.351 1.728 4.523 34.569 ;
     RECT  4.523 2.106 4.603 34.569 ;
     RECT  4.603 2.106 4.883 34.794 ;
     RECT  5.035 0.144 5.459 0.162 ;
     RECT  4.883 2.151 5.603 34.794 ;
     RECT  5.603 2.151 6.331 34.569 ;
     RECT  6.331 2.151 7.699 34.794 ;
     RECT  7.699 2.151 7.807 34.839 ;
     RECT  7.807 1.728 7.835 34.839 ;
     RECT  7.835 1.728 8.303 34.794 ;
     RECT  8.303 1.728 9.239 34.569 ;
     RECT  9.239 2.151 9.319 34.569 ;
     RECT  9.319 2.151 9.419 34.758 ;
     RECT  9.419 2.151 10.039 34.569 ;
     RECT  10.039 1.728 10.399 34.569 ;
     RECT  10.399 1.728 10.427 34.839 ;
     RECT  10.471 1.152 10.679 1.17 ;
     RECT  10.651 0.144 10.823 0.162 ;
     RECT  10.427 2.151 10.823 34.839 ;
     RECT  10.823 2.151 12.271 34.794 ;
     RECT  12.271 1.728 12.515 34.794 ;
     RECT  12.515 1.728 12.731 34.569 ;
     RECT  12.775 0.576 13.243 0.594 ;
     RECT  12.731 2.151 13.243 34.569 ;
     RECT  13.243 0.144 13.379 0.594 ;
     RECT  13.243 2.151 13.379 34.65 ;
     RECT  13.379 0.576 13.703 0.594 ;
     RECT  13.379 2.151 15.979 34.569 ;
     RECT  15.979 0.144 16.079 0.162 ;
     RECT  15.979 2.151 16.079 34.65 ;
     RECT  16.079 2.151 16.447 34.569 ;
     RECT  16.447 1.728 16.691 34.569 ;
     RECT  16.951 1.152 17.051 1.17 ;
     RECT  16.691 2.151 17.203 34.569 ;
     RECT  17.203 2.151 17.707 34.794 ;
     RECT  17.707 2.151 18.427 34.839 ;
     RECT  18.427 2.151 18.779 34.884 ;
     RECT  17.959 0.144 19.067 0.162 ;
     RECT  18.779 2.151 19.823 34.839 ;
     RECT  19.823 2.151 19.931 34.758 ;
     RECT  19.931 2.151 21.163 34.569 ;
     RECT  21.163 2.151 21.235 34.794 ;
     RECT  19.795 0.144 21.443 0.162 ;
     RECT  21.235 2.151 21.443 34.839 ;
     RECT  21.443 2.151 21.479 34.794 ;
     RECT  21.631 0.576 22.307 0.594 ;
     RECT  21.479 2.151 22.639 34.569 ;
     RECT  22.639 1.656 22.847 34.569 ;
     RECT  22.847 2.151 22.891 34.569 ;
     RECT  23.071 0.144 23.935 0.162 ;
     RECT  23.935 0.144 24.143 0.234 ;
     RECT  24.143 0.144 24.467 0.162 ;
     RECT  22.891 2.151 24.619 34.794 ;
     RECT  24.619 2.151 24.863 34.839 ;
     RECT  24.863 2.151 25.295 34.794 ;
     RECT  25.519 0.144 25.619 0.162 ;
     RECT  25.295 2.151 26.815 34.569 ;
     RECT  26.599 0.144 27.059 0.162 ;
     RECT  26.815 2.151 27.059 34.794 ;
     RECT  27.059 2.151 27.347 34.758 ;
     RECT  27.347 2.151 28.795 34.569 ;
     RECT  28.795 1.728 29.147 34.569 ;
     RECT  29.147 2.106 29.795 34.569 ;
     RECT  29.795 2.151 29.983 34.569 ;
     RECT  29.983 2.151 30.515 34.794 ;
     RECT  31.207 0.144 31.307 0.162 ;
     RECT  30.515 2.151 31.495 34.569 ;
     RECT  31.495 2.106 32.251 34.569 ;
     RECT  32.251 1.728 32.675 34.569 ;
     RECT  32.899 36.558 32.999 36.648 ;
     RECT  32.999 36.558 33.035 36.576 ;
     RECT  32.675 2.151 33.727 34.569 ;
     RECT  33.727 2.151 33.979 34.794 ;
     RECT  33.979 2.151 34.187 34.884 ;
     RECT  34.187 2.151 34.987 34.758 ;
     RECT  34.987 2.151 35.239 34.794 ;
     RECT  35.239 1.728 35.303 34.794 ;
     RECT  35.303 1.728 35.483 34.569 ;
     RECT  34.987 0.144 35.555 0.162 ;
     RECT  35.483 2.151 37.147 34.569 ;
     RECT  37.147 2.106 37.435 34.569 ;
     RECT  37.435 1.728 37.679 34.569 ;
     RECT  37.679 2.106 37.687 34.569 ;
     RECT  36.895 0.144 38.075 0.162 ;
     RECT  37.687 2.106 38.435 34.794 ;
     RECT  38.435 2.151 39.415 34.794 ;
     RECT  39.415 2.151 39.911 34.839 ;
     RECT  40.351 0.144 40.451 0.162 ;
     RECT  39.911 2.151 40.639 34.794 ;
     RECT  40.639 2.151 41.027 34.839 ;
     RECT  41.027 2.151 43.123 34.569 ;
     RECT  43.123 0.144 43.259 0.162 ;
     RECT  43.123 2.151 43.259 34.794 ;
     RECT  43.879 35.982 44.159 36 ;
     RECT  43.259 2.151 44.347 34.569 ;
     RECT  44.347 1.728 44.599 34.569 ;
     RECT  44.599 1.728 45.023 34.794 ;
     RECT  45.023 1.728 45.095 34.65 ;
     RECT  45.095 2.151 45.779 34.65 ;
     RECT  45.823 0.144 45.959 0.162 ;
     RECT  45.779 2.151 48.811 34.569 ;
     RECT  48.811 1.728 49.063 34.569 ;
     RECT  49.063 1.728 49.279 34.794 ;
     RECT  48.559 0.144 49.307 0.162 ;
     RECT  49.279 1.728 49.415 34.839 ;
     RECT  49.415 1.728 49.451 34.794 ;
     RECT  48.307 35.901 49.883 35.919 ;
     RECT  49.451 1.728 50.035 34.569 ;
     RECT  50.035 1.656 50.207 34.569 ;
     RECT  50.207 1.728 50.315 34.569 ;
     RECT  50.315 2.151 50.791 34.569 ;
     RECT  50.791 2.151 50.827 34.794 ;
     RECT  50.287 0.144 51.179 0.162 ;
     RECT  50.827 2.151 51.259 34.884 ;
     RECT  51.259 1.728 51.287 34.884 ;
     RECT  51.287 1.728 51.575 34.569 ;
     RECT  51.763 1.152 51.863 1.17 ;
     RECT  51.575 2.151 52.519 34.569 ;
     RECT  52.519 2.151 52.663 34.794 ;
     RECT  52.663 2.151 52.763 34.884 ;
     RECT  52.763 2.151 53.491 34.839 ;
     RECT  53.491 1.728 53.591 34.884 ;
     RECT  53.591 1.728 53.771 34.65 ;
     RECT  53.771 1.728 53.879 34.569 ;
     RECT  53.879 1.8 54.527 34.569 ;
     RECT  54.527 2.151 56.443 34.569 ;
     RECT  56.443 2.151 56.579 34.65 ;
     RECT  56.695 0.144 56.795 0.162 ;
     RECT  56.579 2.151 56.947 34.569 ;
     RECT  56.947 1.728 57.227 34.569 ;
     RECT  57.919 0.144 58.019 0.162 ;
     RECT  57.227 2.151 58.675 34.569 ;
     RECT  59.575 0.144 59.675 0.162 ;
     RECT  58.675 1.728 59.675 34.569 ;
     RECT  59.179 35.901 60.143 35.919 ;
     RECT  59.675 2.151 61.159 34.569 ;
     RECT  61.159 2.151 61.267 34.794 ;
     RECT  61.267 2.151 61.403 34.839 ;
     RECT  61.735 0.144 62.383 0.162 ;
     RECT  62.383 0.144 62.483 0.234 ;
     RECT  61.403 2.151 62.635 34.794 ;
     RECT  62.483 0.144 63.023 0.162 ;
     RECT  62.635 1.728 63.167 34.794 ;
     RECT  63.167 1.728 63.995 34.569 ;
     RECT  64.615 36.558 64.651 36.576 ;
     RECT  64.651 36.558 64.751 36.648 ;
     RECT  63.995 1.8 64.831 34.569 ;
     RECT  64.831 1.728 65.075 34.569 ;
     RECT  65.075 2.151 65.587 34.569 ;
     RECT  65.587 2.151 65.831 34.794 ;
     RECT  65.831 2.151 65.911 34.758 ;
     RECT  64.399 0.144 66.443 0.162 ;
     RECT  65.911 2.106 66.811 34.758 ;
     RECT  66.811 2.106 67.055 34.794 ;
     RECT  67.055 2.151 67.063 34.794 ;
     RECT  67.315 0.144 67.559 0.162 ;
     RECT  67.063 2.151 68.135 34.839 ;
     RECT  68.135 2.151 68.171 34.758 ;
     RECT  68.171 2.151 69.043 34.569 ;
     RECT  69.043 2.151 69.727 34.794 ;
     RECT  69.727 2.151 70.043 34.839 ;
     RECT  69.835 0.144 70.619 0.162 ;
     RECT  70.043 2.151 70.771 34.569 ;
     RECT  70.771 2.151 71.023 34.794 ;
     RECT  71.023 2.151 71.159 34.839 ;
     RECT  71.159 2.151 71.231 34.794 ;
     RECT  71.671 0.144 71.771 0.162 ;
     RECT  71.231 2.151 71.995 34.569 ;
     RECT  71.995 2.151 72.347 34.794 ;
     RECT  72.347 2.151 75.6 34.569 ;
     RECT  75.6 2.421 75.612 34.299 ;
    LAYER M3 ;
     RECT  4.374 0.108 4.608 0.144 ;
     RECT  4.626 0.108 4.86 0.144 ;
     RECT  4.878 0.108 5.112 0.144 ;
     RECT  5.13 0.108 5.364 0.144 ;
     RECT  5.382 0.108 5.616 0.144 ;
     RECT  5.634 0.108 5.868 0.144 ;
     RECT  5.886 0.108 6.084 0.144 ;
     RECT  6.102 0.108 6.336 0.144 ;
     RECT  6.354 0.108 6.588 0.144 ;
     RECT  6.606 0.108 6.84 0.144 ;
     RECT  6.858 0.108 7.092 0.144 ;
     RECT  7.11 0.108 7.344 0.144 ;
     RECT  7.362 0.108 7.596 0.144 ;
     RECT  7.614 0.108 7.812 0.144 ;
     RECT  7.83 0.108 8.064 0.144 ;
     RECT  8.082 0.108 8.316 0.144 ;
     RECT  8.334 0.108 8.568 0.144 ;
     RECT  8.586 0.108 8.82 0.144 ;
     RECT  8.838 0.108 9.072 0.144 ;
     RECT  9.09 0.108 9.324 0.144 ;
     RECT  9.342 0.108 9.54 0.144 ;
     RECT  9.558 0.108 9.792 0.144 ;
     RECT  9.81 0.108 10.044 0.144 ;
     RECT  10.062 0.108 10.296 0.144 ;
     RECT  10.314 0.108 10.548 0.144 ;
     RECT  10.566 0.108 10.8 0.144 ;
     RECT  10.818 0.108 11.052 0.144 ;
     RECT  11.07 0.108 11.268 0.144 ;
     RECT  11.286 0.108 11.52 0.144 ;
     RECT  11.538 0.108 11.772 0.144 ;
     RECT  11.79 0.108 12.024 0.144 ;
     RECT  12.042 0.108 12.276 0.144 ;
     RECT  12.294 0.108 12.528 0.144 ;
     RECT  12.546 0.108 12.78 0.144 ;
     RECT  12.798 0.108 12.996 0.144 ;
     RECT  13.014 0.108 13.248 0.144 ;
     RECT  13.266 0.108 13.5 0.144 ;
     RECT  13.518 0.108 13.752 0.144 ;
     RECT  13.77 0.108 14.004 0.144 ;
     RECT  14.022 0.108 14.256 0.144 ;
     RECT  14.274 0.108 14.508 0.144 ;
     RECT  14.526 0.108 14.724 0.144 ;
     RECT  14.742 0.108 14.976 0.144 ;
     RECT  14.994 0.108 15.228 0.144 ;
     RECT  15.246 0.108 15.48 0.144 ;
     RECT  15.498 0.108 15.732 0.144 ;
     RECT  15.75 0.108 15.984 0.144 ;
     RECT  16.002 0.108 16.236 0.144 ;
     RECT  16.254 0.108 16.452 0.144 ;
     RECT  16.47 0.108 16.704 0.144 ;
     RECT  16.722 0.108 16.956 0.144 ;
     RECT  16.974 0.108 17.208 0.144 ;
     RECT  17.226 0.108 17.46 0.144 ;
     RECT  17.478 0.108 17.712 0.144 ;
     RECT  17.73 0.108 17.964 0.144 ;
     RECT  17.982 0.108 18.18 0.144 ;
     RECT  18.198 0.108 18.432 0.144 ;
     RECT  18.45 0.108 18.684 0.144 ;
     RECT  18.702 0.108 18.936 0.144 ;
     RECT  18.954 0.108 19.188 0.144 ;
     RECT  19.206 0.108 19.44 0.144 ;
     RECT  19.458 0.108 19.692 0.144 ;
     RECT  19.71 0.108 19.908 0.144 ;
     RECT  19.926 0.108 20.16 0.144 ;
     RECT  20.178 0.108 20.412 0.144 ;
     RECT  20.43 0.108 20.664 0.144 ;
     RECT  20.682 0.108 20.916 0.144 ;
     RECT  20.934 0.108 21.168 0.144 ;
     RECT  21.186 0.108 21.42 0.144 ;
     RECT  21.438 0.108 21.636 0.144 ;
     RECT  21.654 0.108 21.888 0.144 ;
     RECT  21.906 0.108 22.14 0.144 ;
     RECT  22.158 0.108 22.392 0.144 ;
     RECT  22.41 0.108 22.644 0.144 ;
     RECT  22.662 0.108 22.896 0.144 ;
     RECT  22.914 0.108 23.148 0.144 ;
     RECT  23.166 0.108 23.364 0.144 ;
     RECT  23.382 0.108 23.616 0.144 ;
     RECT  23.634 0.108 23.868 0.144 ;
     RECT  23.886 0.108 24.12 0.144 ;
     RECT  24.138 0.108 24.372 0.144 ;
     RECT  24.39 0.108 24.624 0.144 ;
     RECT  24.642 0.108 24.876 0.144 ;
     RECT  24.894 0.108 25.092 0.144 ;
     RECT  25.11 0.108 25.344 0.144 ;
     RECT  25.362 0.108 25.596 0.144 ;
     RECT  25.614 0.108 25.848 0.144 ;
     RECT  25.866 0.108 26.1 0.144 ;
     RECT  26.118 0.108 26.352 0.144 ;
     RECT  26.37 0.108 26.604 0.144 ;
     RECT  26.622 0.108 26.82 0.144 ;
     RECT  26.838 0.108 27.072 0.144 ;
     RECT  27.09 0.108 27.324 0.144 ;
     RECT  27.342 0.108 27.576 0.144 ;
     RECT  27.594 0.108 27.828 0.144 ;
     RECT  27.846 0.108 28.08 0.144 ;
     RECT  28.098 0.108 28.332 0.144 ;
     RECT  28.35 0.108 28.548 0.144 ;
     RECT  28.566 0.108 28.8 0.144 ;
     RECT  28.818 0.108 29.052 0.144 ;
     RECT  29.07 0.108 29.304 0.144 ;
     RECT  29.322 0.108 29.556 0.144 ;
     RECT  29.574 0.108 29.808 0.144 ;
     RECT  29.826 0.108 30.06 0.144 ;
     RECT  30.078 0.108 30.276 0.144 ;
     RECT  30.294 0.108 30.528 0.144 ;
     RECT  30.546 0.108 30.78 0.144 ;
     RECT  30.798 0.108 31.032 0.144 ;
     RECT  31.05 0.108 31.284 0.144 ;
     RECT  31.302 0.108 31.536 0.144 ;
     RECT  31.554 0.108 31.788 0.144 ;
     RECT  31.806 0.108 32.004 0.144 ;
     RECT  32.022 0.108 32.256 0.144 ;
     RECT  32.274 0.108 32.508 0.144 ;
     RECT  32.526 0.108 32.76 0.144 ;
     RECT  32.778 0.108 33.012 0.144 ;
     RECT  33.03 0.108 33.264 0.144 ;
     RECT  33.282 0.108 33.516 0.144 ;
     RECT  33.534 0.108 33.732 0.144 ;
     RECT  33.75 0.108 33.984 0.144 ;
     RECT  34.002 0.108 34.236 0.144 ;
     RECT  34.254 0.108 34.488 0.144 ;
     RECT  34.506 0.108 34.74 0.144 ;
     RECT  34.758 0.108 34.992 0.144 ;
     RECT  35.01 0.108 35.244 0.144 ;
     RECT  35.262 0.108 35.46 0.144 ;
     RECT  35.478 0.108 35.712 0.144 ;
     RECT  35.73 0.108 35.964 0.144 ;
     RECT  35.982 0.108 36.216 0.144 ;
     RECT  36.234 0.108 36.468 0.144 ;
     RECT  36.486 0.108 36.72 0.144 ;
     RECT  36.738 0.108 36.972 0.144 ;
     RECT  36.99 0.108 37.188 0.144 ;
     RECT  37.206 0.108 37.44 0.144 ;
     RECT  37.458 0.108 37.692 0.144 ;
     RECT  37.71 0.108 37.944 0.144 ;
     RECT  37.962 0.108 38.196 0.144 ;
     RECT  38.214 0.108 38.448 0.144 ;
     RECT  38.466 0.108 38.7 0.144 ;
     RECT  38.718 0.108 38.916 0.144 ;
     RECT  38.934 0.108 39.168 0.144 ;
     RECT  39.186 0.108 39.42 0.144 ;
     RECT  39.438 0.108 39.672 0.144 ;
     RECT  39.69 0.108 39.924 0.144 ;
     RECT  39.942 0.108 40.176 0.144 ;
     RECT  40.194 0.108 40.428 0.144 ;
     RECT  40.446 0.108 40.644 0.144 ;
     RECT  40.662 0.108 40.896 0.144 ;
     RECT  40.914 0.108 41.148 0.144 ;
     RECT  41.166 0.108 41.4 0.144 ;
     RECT  41.418 0.108 41.652 0.144 ;
     RECT  41.67 0.108 41.904 0.144 ;
     RECT  41.922 0.108 42.156 0.144 ;
     RECT  42.174 0.108 42.372 0.144 ;
     RECT  42.39 0.108 42.624 0.144 ;
     RECT  42.642 0.108 42.876 0.144 ;
     RECT  42.894 0.108 43.128 0.144 ;
     RECT  43.146 0.108 43.38 0.144 ;
     RECT  43.398 0.108 43.632 0.144 ;
     RECT  43.65 0.108 43.884 0.144 ;
     RECT  43.902 0.108 44.1 0.144 ;
     RECT  44.118 0.108 44.352 0.144 ;
     RECT  44.37 0.108 44.604 0.144 ;
     RECT  44.622 0.108 44.856 0.144 ;
     RECT  44.874 0.108 45.108 0.144 ;
     RECT  45.126 0.108 45.36 0.144 ;
     RECT  45.378 0.108 45.612 0.144 ;
     RECT  45.63 0.108 45.828 0.144 ;
     RECT  45.846 0.108 46.08 0.144 ;
     RECT  46.098 0.108 46.332 0.144 ;
     RECT  46.35 0.108 46.584 0.144 ;
     RECT  46.602 0.108 46.836 0.144 ;
     RECT  46.854 0.108 47.088 0.144 ;
     RECT  47.106 0.108 47.34 0.144 ;
     RECT  47.358 0.108 47.556 0.144 ;
     RECT  47.574 0.108 47.808 0.144 ;
     RECT  47.826 0.108 48.06 0.144 ;
     RECT  48.078 0.108 48.312 0.144 ;
     RECT  48.33 0.108 48.564 0.144 ;
     RECT  48.582 0.108 48.816 0.144 ;
     RECT  48.834 0.108 49.068 0.144 ;
     RECT  49.086 0.108 49.284 0.144 ;
     RECT  49.302 0.108 49.536 0.144 ;
     RECT  49.554 0.108 49.788 0.144 ;
     RECT  49.806 0.108 50.04 0.144 ;
     RECT  50.058 0.108 50.292 0.144 ;
     RECT  50.31 0.108 50.544 0.144 ;
     RECT  50.562 0.108 50.796 0.144 ;
     RECT  50.814 0.108 51.012 0.144 ;
     RECT  51.03 0.108 51.264 0.144 ;
     RECT  51.282 0.108 51.516 0.144 ;
     RECT  51.534 0.108 51.768 0.144 ;
     RECT  51.786 0.108 52.02 0.144 ;
     RECT  52.038 0.108 52.272 0.144 ;
     RECT  52.29 0.108 52.524 0.144 ;
     RECT  52.542 0.108 52.74 0.144 ;
     RECT  52.758 0.108 52.992 0.144 ;
     RECT  53.01 0.108 53.244 0.144 ;
     RECT  53.262 0.108 53.496 0.144 ;
     RECT  53.514 0.108 53.748 0.144 ;
     RECT  53.766 0.108 54 0.144 ;
     RECT  54.018 0.108 54.252 0.144 ;
     RECT  54.27 0.108 54.468 0.144 ;
     RECT  54.486 0.108 54.72 0.144 ;
     RECT  54.738 0.108 54.972 0.144 ;
     RECT  54.99 0.108 55.224 0.144 ;
     RECT  55.242 0.108 55.476 0.144 ;
     RECT  55.494 0.108 55.728 0.144 ;
     RECT  55.746 0.108 55.98 0.144 ;
     RECT  55.998 0.108 56.196 0.144 ;
     RECT  56.214 0.108 56.448 0.144 ;
     RECT  56.466 0.108 56.7 0.144 ;
     RECT  56.718 0.108 56.952 0.144 ;
     RECT  56.97 0.108 57.204 0.144 ;
     RECT  57.222 0.108 57.456 0.144 ;
     RECT  57.474 0.108 57.708 0.144 ;
     RECT  57.726 0.108 57.924 0.144 ;
     RECT  57.942 0.108 58.176 0.144 ;
     RECT  58.194 0.108 58.428 0.144 ;
     RECT  58.446 0.108 58.68 0.144 ;
     RECT  58.698 0.108 58.932 0.144 ;
     RECT  58.95 0.108 59.184 0.144 ;
     RECT  59.202 0.108 59.436 0.144 ;
     RECT  59.454 0.108 59.652 0.144 ;
     RECT  59.67 0.108 59.904 0.144 ;
     RECT  59.922 0.108 60.156 0.144 ;
     RECT  60.174 0.108 60.408 0.144 ;
     RECT  60.426 0.108 60.66 0.144 ;
     RECT  60.678 0.108 60.912 0.144 ;
     RECT  60.93 0.108 61.164 0.144 ;
     RECT  61.182 0.108 61.38 0.144 ;
     RECT  61.398 0.108 61.632 0.144 ;
     RECT  61.65 0.108 61.884 0.144 ;
     RECT  61.902 0.108 62.136 0.144 ;
     RECT  62.154 0.108 62.388 0.144 ;
     RECT  62.406 0.108 62.64 0.144 ;
     RECT  62.658 0.108 62.892 0.144 ;
     RECT  62.91 0.108 63.108 0.144 ;
     RECT  63.126 0.108 63.36 0.144 ;
     RECT  63.378 0.108 63.612 0.144 ;
     RECT  63.63 0.108 63.864 0.144 ;
     RECT  63.882 0.108 64.116 0.144 ;
     RECT  64.134 0.108 64.368 0.144 ;
     RECT  64.386 0.108 64.62 0.144 ;
     RECT  64.638 0.108 64.836 0.144 ;
     RECT  64.854 0.108 65.088 0.144 ;
     RECT  65.106 0.108 65.34 0.144 ;
     RECT  65.358 0.108 65.592 0.144 ;
     RECT  65.61 0.108 65.844 0.144 ;
     RECT  65.862 0.108 66.096 0.144 ;
     RECT  66.114 0.108 66.348 0.144 ;
     RECT  66.366 0.108 66.564 0.144 ;
     RECT  66.582 0.108 66.816 0.144 ;
     RECT  66.834 0.108 67.068 0.144 ;
     RECT  67.086 0.108 67.32 0.144 ;
     RECT  67.338 0.108 67.572 0.144 ;
     RECT  67.59 0.108 67.824 0.144 ;
     RECT  67.842 0.108 68.076 0.144 ;
     RECT  68.094 0.108 68.292 0.144 ;
     RECT  68.31 0.108 68.544 0.144 ;
     RECT  68.562 0.108 68.796 0.144 ;
     RECT  68.814 0.108 69.048 0.144 ;
     RECT  69.066 0.108 69.3 0.144 ;
     RECT  69.318 0.108 69.552 0.144 ;
     RECT  69.57 0.108 69.804 0.144 ;
     RECT  69.822 0.108 70.02 0.144 ;
     RECT  70.038 0.108 70.272 0.144 ;
     RECT  70.29 0.108 70.524 0.144 ;
     RECT  70.542 0.108 70.776 0.144 ;
     RECT  70.794 0.108 71.028 0.144 ;
     RECT  71.046 0.108 71.28 0.144 ;
     RECT  71.298 0.108 71.532 0.144 ;
     RECT  71.55 0.108 71.748 0.144 ;
     RECT  71.766 0.108 72 0.144 ;
     RECT  72.018 0.108 72.252 0.144 ;
     RECT  72.27 0.108 72.504 0.144 ;
     RECT  72.522 0.108 72.756 0.144 ;
     RECT  72.774 0.108 73.008 0.144 ;
     RECT  73.026 0.108 73.26 0.144 ;
     RECT  4.356 0.144 73.278 0.173 ;
     RECT  48.312 0.173 73.278 0.317 ;
     RECT  48.312 0.317 55.746 0.557 ;
     RECT  4.356 0.173 47.358 1.723 ;
     RECT  48.636 0.557 55.746 1.723 ;
     RECT  56.772 0.317 73.278 1.723 ;
     RECT  4.248 1.723 47.502 2.101 ;
     RECT  3.852 2.101 47.502 2.191 ;
     RECT  48.24 1.723 73.278 2.191 ;
     RECT  74.52 1.723 74.538 2.191 ;
     RECT  3.852 2.191 74.538 2.227 ;
     RECT  75.315 2.143 75.405 2.227 ;
     RECT  3.852 2.227 75.405 2.255 ;
     RECT  2.415 2.143 2.505 2.413 ;
     RECT  4.068 2.255 75.405 2.413 ;
     RECT  4.068 2.413 75.597 2.489 ;
     RECT  4.176 2.489 75.597 3.301 ;
     RECT  4.032 3.301 75.597 3.341 ;
     RECT  4.068 3.341 75.597 4.507 ;
     RECT  3.78 4.507 75.597 4.559 ;
     RECT  4.248 4.559 75.597 4.955 ;
     RECT  4.5 4.955 75.597 8.311 ;
     RECT  4.284 8.311 75.597 12.749 ;
     RECT  4.392 12.749 75.597 18.725 ;
     RECT  4.428 18.725 75.597 18.995 ;
     RECT  4.428 18.995 74.394 24.395 ;
     RECT  4.5 24.395 74.394 24.971 ;
     RECT  4.5 24.971 74.286 30.721 ;
     RECT  4.356 30.721 74.286 30.875 ;
     RECT  4.356 30.875 73.818 31.145 ;
     RECT  2.415 2.413 2.697 34.307 ;
     RECT  75.315 18.995 75.597 34.307 ;
     RECT  2.415 34.307 2.505 34.577 ;
     RECT  75.315 34.307 75.405 34.577 ;
     RECT  4.356 31.145 73.53 34.781 ;
     RECT  4.356 34.781 73.494 35.357 ;
     RECT  4.356 35.357 73.278 36.576 ;
     RECT  4.374 36.576 4.608 36.588 ;
     RECT  4.626 36.576 4.86 36.588 ;
     RECT  4.878 36.576 5.112 36.588 ;
     RECT  5.13 36.576 5.364 36.588 ;
     RECT  5.382 36.576 5.616 36.588 ;
     RECT  5.634 36.576 5.868 36.588 ;
     RECT  5.886 36.576 6.084 36.588 ;
     RECT  6.102 36.576 6.336 36.588 ;
     RECT  6.354 36.576 6.588 36.588 ;
     RECT  6.606 36.576 6.84 36.588 ;
     RECT  6.858 36.576 7.092 36.588 ;
     RECT  7.11 36.576 7.344 36.588 ;
     RECT  7.362 36.576 7.596 36.588 ;
     RECT  7.614 36.576 7.812 36.588 ;
     RECT  7.83 36.576 8.064 36.588 ;
     RECT  8.082 36.576 8.316 36.588 ;
     RECT  8.334 36.576 8.568 36.588 ;
     RECT  8.586 36.576 8.82 36.588 ;
     RECT  8.838 36.576 9.072 36.588 ;
     RECT  9.09 36.576 9.324 36.588 ;
     RECT  9.342 36.576 9.54 36.588 ;
     RECT  9.558 36.576 9.792 36.588 ;
     RECT  9.81 36.576 10.044 36.588 ;
     RECT  10.062 36.576 10.296 36.588 ;
     RECT  10.314 36.576 10.548 36.588 ;
     RECT  10.566 36.576 10.8 36.588 ;
     RECT  10.818 36.576 11.052 36.588 ;
     RECT  11.07 36.576 11.268 36.588 ;
     RECT  11.286 36.576 11.52 36.588 ;
     RECT  11.538 36.576 11.772 36.588 ;
     RECT  11.79 36.576 12.024 36.588 ;
     RECT  12.042 36.576 12.276 36.588 ;
     RECT  12.294 36.576 12.528 36.588 ;
     RECT  12.546 36.576 12.78 36.588 ;
     RECT  12.798 36.576 12.996 36.588 ;
     RECT  13.014 36.576 13.248 36.588 ;
     RECT  13.266 36.576 13.5 36.588 ;
     RECT  13.518 36.576 13.752 36.588 ;
     RECT  13.77 36.576 14.004 36.588 ;
     RECT  14.022 36.576 14.256 36.588 ;
     RECT  14.274 36.576 14.508 36.588 ;
     RECT  14.526 36.576 14.724 36.588 ;
     RECT  14.742 36.576 14.976 36.588 ;
     RECT  14.994 36.576 15.228 36.588 ;
     RECT  15.246 36.576 15.48 36.588 ;
     RECT  15.498 36.576 15.732 36.588 ;
     RECT  15.75 36.576 15.984 36.588 ;
     RECT  16.002 36.576 16.236 36.588 ;
     RECT  16.254 36.576 16.452 36.588 ;
     RECT  16.47 36.576 16.704 36.588 ;
     RECT  16.722 36.576 16.956 36.588 ;
     RECT  16.974 36.576 17.208 36.588 ;
     RECT  17.226 36.576 17.46 36.588 ;
     RECT  17.478 36.576 17.712 36.588 ;
     RECT  17.73 36.576 17.964 36.588 ;
     RECT  17.982 36.576 18.18 36.588 ;
     RECT  18.198 36.576 18.432 36.588 ;
     RECT  18.45 36.576 18.684 36.588 ;
     RECT  18.702 36.576 18.936 36.588 ;
     RECT  18.954 36.576 19.188 36.588 ;
     RECT  19.206 36.576 19.44 36.588 ;
     RECT  19.458 36.576 19.692 36.588 ;
     RECT  19.71 36.576 19.908 36.588 ;
     RECT  19.926 36.576 20.16 36.588 ;
     RECT  20.178 36.576 20.412 36.588 ;
     RECT  20.43 36.576 20.664 36.588 ;
     RECT  20.682 36.576 20.916 36.588 ;
     RECT  20.934 36.576 21.168 36.588 ;
     RECT  21.186 36.576 21.42 36.588 ;
     RECT  21.438 36.576 21.636 36.588 ;
     RECT  21.654 36.576 21.888 36.588 ;
     RECT  21.906 36.576 22.14 36.588 ;
     RECT  22.158 36.576 22.392 36.588 ;
     RECT  22.41 36.576 22.644 36.588 ;
     RECT  22.662 36.576 22.896 36.588 ;
     RECT  22.914 36.576 23.148 36.588 ;
     RECT  23.166 36.576 23.364 36.588 ;
     RECT  23.382 36.576 23.616 36.588 ;
     RECT  23.634 36.576 23.868 36.588 ;
     RECT  23.886 36.576 24.12 36.588 ;
     RECT  24.138 36.576 24.372 36.588 ;
     RECT  24.39 36.576 24.624 36.588 ;
     RECT  24.642 36.576 24.876 36.588 ;
     RECT  24.894 36.576 25.092 36.588 ;
     RECT  25.11 36.576 25.344 36.588 ;
     RECT  25.362 36.576 25.596 36.588 ;
     RECT  25.614 36.576 25.848 36.588 ;
     RECT  25.866 36.576 26.1 36.588 ;
     RECT  26.118 36.576 26.352 36.588 ;
     RECT  26.37 36.576 26.604 36.588 ;
     RECT  26.622 36.576 26.82 36.588 ;
     RECT  26.838 36.576 27.072 36.588 ;
     RECT  27.09 36.576 27.324 36.588 ;
     RECT  27.342 36.576 27.576 36.588 ;
     RECT  27.594 36.576 27.828 36.588 ;
     RECT  27.846 36.576 28.08 36.588 ;
     RECT  28.098 36.576 28.332 36.588 ;
     RECT  28.35 36.576 28.548 36.588 ;
     RECT  28.566 36.576 28.8 36.588 ;
     RECT  28.818 36.576 29.052 36.588 ;
     RECT  29.07 36.576 29.304 36.588 ;
     RECT  29.322 36.576 29.556 36.588 ;
     RECT  29.574 36.576 29.808 36.588 ;
     RECT  29.826 36.576 30.06 36.588 ;
     RECT  30.078 36.576 30.276 36.588 ;
     RECT  30.294 36.576 30.528 36.588 ;
     RECT  30.546 36.576 30.78 36.588 ;
     RECT  30.798 36.576 31.032 36.588 ;
     RECT  31.05 36.576 31.284 36.588 ;
     RECT  31.302 36.576 31.536 36.588 ;
     RECT  31.554 36.576 31.788 36.588 ;
     RECT  31.806 36.576 32.004 36.588 ;
     RECT  32.022 36.576 32.256 36.588 ;
     RECT  32.274 36.576 32.508 36.588 ;
     RECT  32.526 36.576 32.76 36.588 ;
     RECT  32.778 36.576 33.012 36.588 ;
     RECT  33.03 36.576 33.264 36.588 ;
     RECT  33.282 36.576 33.516 36.588 ;
     RECT  33.534 36.576 33.732 36.588 ;
     RECT  33.75 36.576 33.984 36.588 ;
     RECT  34.002 36.576 34.236 36.588 ;
     RECT  34.254 36.576 34.488 36.588 ;
     RECT  34.506 36.576 34.74 36.588 ;
     RECT  34.758 36.576 34.992 36.588 ;
     RECT  35.01 36.576 35.244 36.588 ;
     RECT  35.262 36.576 35.46 36.588 ;
     RECT  35.478 36.576 35.712 36.588 ;
     RECT  35.73 36.576 35.964 36.588 ;
     RECT  35.982 36.576 36.216 36.588 ;
     RECT  36.234 36.576 36.468 36.588 ;
     RECT  36.486 36.576 36.72 36.588 ;
     RECT  36.738 36.576 36.972 36.588 ;
     RECT  36.99 36.576 37.188 36.588 ;
     RECT  37.206 36.576 37.44 36.588 ;
     RECT  37.458 36.576 37.692 36.588 ;
     RECT  37.71 36.576 37.944 36.588 ;
     RECT  37.962 36.576 38.196 36.588 ;
     RECT  38.214 36.576 38.448 36.588 ;
     RECT  38.466 36.576 38.7 36.588 ;
     RECT  38.718 36.576 38.916 36.588 ;
     RECT  38.934 36.576 39.168 36.588 ;
     RECT  39.186 36.576 39.42 36.588 ;
     RECT  39.438 36.576 39.672 36.588 ;
     RECT  39.69 36.576 39.924 36.588 ;
     RECT  39.942 36.576 40.176 36.588 ;
     RECT  40.194 36.576 40.428 36.588 ;
     RECT  40.446 36.576 40.644 36.588 ;
     RECT  40.662 36.576 40.896 36.588 ;
     RECT  40.914 36.576 41.148 36.588 ;
     RECT  41.166 36.576 41.4 36.588 ;
     RECT  41.418 36.576 41.652 36.588 ;
     RECT  41.67 36.576 41.904 36.588 ;
     RECT  41.922 36.576 42.156 36.588 ;
     RECT  42.174 36.576 42.372 36.588 ;
     RECT  42.39 36.576 42.624 36.588 ;
     RECT  42.642 36.576 42.876 36.588 ;
     RECT  42.894 36.576 43.128 36.588 ;
     RECT  43.146 36.576 43.38 36.588 ;
     RECT  43.398 36.576 43.632 36.588 ;
     RECT  43.65 36.576 43.884 36.588 ;
     RECT  43.902 36.576 44.1 36.588 ;
     RECT  44.118 36.576 44.352 36.588 ;
     RECT  44.37 36.576 44.604 36.588 ;
     RECT  44.622 36.576 44.856 36.588 ;
     RECT  44.874 36.576 45.108 36.588 ;
     RECT  45.126 36.576 45.36 36.588 ;
     RECT  45.378 36.576 45.612 36.588 ;
     RECT  45.63 36.576 45.828 36.588 ;
     RECT  45.846 36.576 46.08 36.588 ;
     RECT  46.098 36.576 46.332 36.588 ;
     RECT  46.35 36.576 46.584 36.588 ;
     RECT  46.602 36.576 46.836 36.588 ;
     RECT  46.854 36.576 47.088 36.588 ;
     RECT  47.106 36.576 47.34 36.588 ;
     RECT  47.358 36.576 47.556 36.588 ;
     RECT  47.574 36.576 47.808 36.588 ;
     RECT  47.826 36.576 48.06 36.588 ;
     RECT  48.078 36.576 48.312 36.588 ;
     RECT  48.33 36.576 48.564 36.588 ;
     RECT  48.582 36.576 48.816 36.588 ;
     RECT  48.834 36.576 49.068 36.588 ;
     RECT  49.086 36.576 49.284 36.588 ;
     RECT  49.302 36.576 49.536 36.588 ;
     RECT  49.554 36.576 49.788 36.588 ;
     RECT  49.806 36.576 50.04 36.588 ;
     RECT  50.058 36.576 50.292 36.588 ;
     RECT  50.31 36.576 50.544 36.588 ;
     RECT  50.562 36.576 50.796 36.588 ;
     RECT  50.814 36.576 51.012 36.588 ;
     RECT  51.03 36.576 51.264 36.588 ;
     RECT  51.282 36.576 51.516 36.588 ;
     RECT  51.534 36.576 51.768 36.588 ;
     RECT  51.786 36.576 52.02 36.588 ;
     RECT  52.038 36.576 52.272 36.588 ;
     RECT  52.29 36.576 52.524 36.588 ;
     RECT  52.542 36.576 52.74 36.588 ;
     RECT  52.758 36.576 52.992 36.588 ;
     RECT  53.01 36.576 53.244 36.588 ;
     RECT  53.262 36.576 53.496 36.588 ;
     RECT  53.514 36.576 53.748 36.588 ;
     RECT  53.766 36.576 54 36.588 ;
     RECT  54.018 36.576 54.252 36.588 ;
     RECT  54.27 36.576 54.468 36.588 ;
     RECT  54.486 36.576 54.72 36.588 ;
     RECT  54.738 36.576 54.972 36.588 ;
     RECT  54.99 36.576 55.224 36.588 ;
     RECT  55.242 36.576 55.476 36.588 ;
     RECT  55.494 36.576 55.728 36.588 ;
     RECT  55.746 36.576 55.98 36.588 ;
     RECT  55.998 36.576 56.196 36.588 ;
     RECT  56.214 36.576 56.448 36.588 ;
     RECT  56.466 36.576 56.7 36.588 ;
     RECT  56.718 36.576 56.952 36.588 ;
     RECT  56.97 36.576 57.204 36.588 ;
     RECT  57.222 36.576 57.456 36.588 ;
     RECT  57.474 36.576 57.708 36.588 ;
     RECT  57.726 36.576 57.924 36.588 ;
     RECT  57.942 36.576 58.176 36.588 ;
     RECT  58.194 36.576 58.428 36.588 ;
     RECT  58.446 36.576 58.68 36.588 ;
     RECT  58.698 36.576 58.932 36.588 ;
     RECT  58.95 36.576 59.184 36.588 ;
     RECT  59.202 36.576 59.436 36.588 ;
     RECT  59.454 36.576 59.652 36.588 ;
     RECT  59.67 36.576 59.904 36.588 ;
     RECT  59.922 36.576 60.156 36.588 ;
     RECT  60.174 36.576 60.408 36.588 ;
     RECT  60.426 36.576 60.66 36.588 ;
     RECT  60.678 36.576 60.912 36.588 ;
     RECT  60.93 36.576 61.164 36.588 ;
     RECT  61.182 36.576 61.38 36.588 ;
     RECT  61.398 36.576 61.632 36.588 ;
     RECT  61.65 36.576 61.884 36.588 ;
     RECT  61.902 36.576 62.136 36.588 ;
     RECT  62.154 36.576 62.388 36.588 ;
     RECT  62.406 36.576 62.64 36.588 ;
     RECT  62.658 36.576 62.892 36.588 ;
     RECT  62.91 36.576 63.108 36.588 ;
     RECT  63.126 36.576 63.36 36.588 ;
     RECT  63.378 36.576 63.612 36.588 ;
     RECT  63.63 36.576 63.864 36.588 ;
     RECT  63.882 36.576 64.116 36.588 ;
     RECT  64.134 36.576 64.368 36.588 ;
     RECT  64.386 36.576 64.62 36.588 ;
     RECT  64.638 36.576 64.836 36.588 ;
     RECT  64.854 36.576 65.088 36.588 ;
     RECT  65.106 36.576 65.34 36.588 ;
     RECT  65.358 36.576 65.592 36.588 ;
     RECT  65.61 36.576 65.844 36.588 ;
     RECT  65.862 36.576 66.096 36.588 ;
     RECT  66.114 36.576 66.348 36.588 ;
     RECT  66.366 36.576 66.564 36.588 ;
     RECT  66.582 36.576 66.816 36.588 ;
     RECT  66.834 36.576 67.068 36.588 ;
     RECT  67.086 36.576 67.32 36.588 ;
     RECT  67.338 36.576 67.572 36.588 ;
     RECT  67.59 36.576 67.824 36.588 ;
     RECT  67.842 36.576 68.076 36.588 ;
     RECT  68.094 36.576 68.292 36.588 ;
     RECT  68.31 36.576 68.544 36.588 ;
     RECT  68.562 36.576 68.796 36.588 ;
     RECT  68.814 36.576 69.048 36.588 ;
     RECT  69.066 36.576 69.3 36.588 ;
     RECT  69.318 36.576 69.552 36.588 ;
     RECT  69.57 36.576 69.804 36.588 ;
     RECT  69.822 36.576 70.02 36.588 ;
     RECT  70.038 36.576 70.272 36.588 ;
     RECT  70.29 36.576 70.524 36.588 ;
     RECT  70.542 36.576 70.776 36.588 ;
     RECT  70.794 36.576 71.028 36.588 ;
     RECT  71.046 36.576 71.28 36.588 ;
     RECT  71.298 36.576 71.532 36.588 ;
     RECT  71.55 36.576 71.748 36.588 ;
     RECT  71.766 36.576 72 36.588 ;
     RECT  72.018 36.576 72.252 36.588 ;
     RECT  72.27 36.576 72.504 36.588 ;
     RECT  72.522 36.576 72.756 36.588 ;
     RECT  72.774 36.576 73.008 36.588 ;
     RECT  73.026 36.576 73.26 36.588 ;
     RECT  32.904 36.588 32.994 36.653 ;
     RECT  64.656 36.588 64.746 36.653 ;
    LAYER M4 ;
     RECT  0.229 7.392 2.408 7.416 ;
     RECT  2.408 2.148 2.512 34.572 ;
     RECT  2.512 2.418 2.704 34.302 ;
     RECT  3.98 3.312 4.021 3.336 ;
     RECT  3.769 4.512 4.021 4.536 ;
     RECT  4.021 3.312 4.067 4.584 ;
     RECT  4.237 1.728 4.741 1.752 ;
     RECT  4.741 1.152 5.108 1.752 ;
     RECT  4.067 3.696 5.108 4.584 ;
     RECT  2.704 7.392 5.108 7.416 ;
     RECT  4.981 30.672 5.108 30.696 ;
     RECT  4.481 34.752 5.108 34.776 ;
     RECT  5.108 1.152 5.221 34.776 ;
     RECT  5.221 1.152 5.404 34.872 ;
     RECT  5.404 34.656 5.461 34.872 ;
     RECT  5.461 34.656 5.603 34.968 ;
     RECT  5.404 1.152 5.669 1.752 ;
     RECT  5.669 0.576 5.753 1.752 ;
     RECT  5.404 3.696 5.884 5.448 ;
     RECT  5.884 3.696 5.933 5.016 ;
     RECT  5.753 1.152 6.275 1.752 ;
     RECT  5.603 34.656 6.469 34.776 ;
     RECT  5.404 30.72 6.709 30.744 ;
     RECT  6.275 1.728 6.761 1.752 ;
     RECT  5.933 3.696 6.949 3.864 ;
     RECT  5.933 4.944 7.009 5.016 ;
     RECT  7.009 4.944 7.333 5.16 ;
     RECT  6.949 2.88 7.429 3.864 ;
     RECT  7.333 4.944 7.429 5.592 ;
     RECT  6.709 30.72 7.429 31.32 ;
     RECT  6.469 34.224 7.669 34.776 ;
     RECT  7.477 1.104 7.715 1.128 ;
     RECT  7.429 2.88 7.808 5.592 ;
     RECT  5.404 7.392 7.808 7.416 ;
     RECT  7.429 30.672 7.808 31.32 ;
     RECT  7.669 34.224 7.808 34.824 ;
     RECT  7.808 2.148 7.957 34.824 ;
     RECT  7.957 2.148 8.104 34.872 ;
     RECT  8.104 34.752 8.165 34.872 ;
     RECT  7.957 0.288 8.197 0.312 ;
     RECT  8.197 0.192 8.243 0.312 ;
     RECT  8.104 3.024 8.243 5.592 ;
     RECT  8.104 30.672 8.273 31.32 ;
     RECT  8.243 0.192 8.339 0.216 ;
     RECT  8.677 1.776 8.881 1.8 ;
     RECT  8.165 34.752 9.157 34.776 ;
     RECT  8.273 30.72 9.173 31.32 ;
     RECT  8.243 3.408 9.397 5.592 ;
     RECT  9.173 30.72 9.397 30.744 ;
     RECT  9.397 2.88 9.493 5.592 ;
     RECT  9.493 2.88 9.601 5.688 ;
     RECT  9.157 34.224 9.685 34.776 ;
     RECT  9.397 30.48 10.165 30.744 ;
     RECT  9.685 34.224 10.357 34.824 ;
     RECT  10.309 0.192 10.451 0.216 ;
     RECT  8.881 1.728 10.508 1.8 ;
     RECT  9.601 2.88 10.508 6.312 ;
     RECT  8.104 7.392 10.508 7.416 ;
     RECT  10.165 30.48 10.508 31.128 ;
     RECT  10.357 34.224 10.508 34.92 ;
     RECT  10.508 1.728 10.691 34.92 ;
     RECT  10.691 1.728 10.804 34.776 ;
     RECT  10.804 1.728 10.865 7.512 ;
     RECT  10.804 30.48 11.045 31.128 ;
     RECT  10.804 34.752 11.405 34.776 ;
     RECT  10.865 2.88 11.981 7.512 ;
     RECT  11.045 30.48 12.125 31.08 ;
     RECT  12.125 30.576 12.853 31.08 ;
     RECT  10.865 1.728 13.057 1.752 ;
     RECT  11.981 3.408 13.093 7.512 ;
     RECT  13.057 1.728 13.208 2.04 ;
     RECT  13.093 3.072 13.208 7.512 ;
     RECT  12.853 30.576 13.208 31.224 ;
     RECT  13.129 34.704 13.208 34.728 ;
     RECT  13.208 1.728 13.213 34.728 ;
     RECT  13.213 1.728 13.504 34.68 ;
     RECT  13.504 2.784 13.565 7.416 ;
     RECT  13.381 0.288 13.619 0.312 ;
     RECT  13.565 2.88 13.619 7.416 ;
     RECT  13.504 34.224 13.619 34.68 ;
     RECT  13.619 2.976 13.673 7.416 ;
     RECT  13.504 30.816 13.709 31.224 ;
     RECT  13.504 9.072 14.249 9.096 ;
     RECT  13.504 1.728 14.581 1.752 ;
     RECT  13.709 30.816 14.581 31.032 ;
     RECT  14.581 30.72 14.861 31.032 ;
     RECT  13.673 3.84 15.349 7.416 ;
     RECT  14.581 1.728 15.401 1.8 ;
     RECT  15.349 2.88 15.445 7.416 ;
     RECT  15.577 1.152 15.733 1.176 ;
     RECT  13.619 34.224 15.749 34.248 ;
     RECT  15.749 34.224 15.788 34.632 ;
     RECT  15.733 0.192 15.875 1.176 ;
     RECT  15.445 2.88 15.908 7.608 ;
     RECT  14.861 30.816 15.908 31.032 ;
     RECT  15.788 34.224 15.908 34.728 ;
     RECT  15.875 1.104 16.115 1.176 ;
     RECT  15.908 2.148 16.204 34.728 ;
     RECT  16.204 3.408 16.373 3.864 ;
     RECT  16.204 34.224 16.597 34.728 ;
     RECT  16.204 5.04 16.625 7.416 ;
     RECT  16.597 34.224 16.924 35.352 ;
     RECT  16.585 1.728 16.949 1.8 ;
     RECT  16.924 34.752 17.057 35.352 ;
     RECT  16.949 1.728 17.077 1.752 ;
     RECT  17.036 36.48 17.123 36.504 ;
     RECT  16.204 30.96 17.129 31.32 ;
     RECT  17.077 1.152 17.219 1.752 ;
     RECT  16.373 3.84 17.413 3.864 ;
     RECT  17.413 3.84 17.557 4.008 ;
     RECT  17.557 2.88 17.737 4.008 ;
     RECT  16.625 5.136 17.737 7.416 ;
     RECT  17.219 1.728 18.037 1.752 ;
     RECT  17.057 34.752 18.46 34.824 ;
     RECT  18.46 34.752 18.469 34.872 ;
     RECT  18.037 1.728 18.569 1.8 ;
     RECT  17.737 2.88 18.608 7.416 ;
     RECT  17.593 18.768 18.608 18.792 ;
     RECT  17.557 30.816 18.608 30.888 ;
     RECT  18.469 34.224 18.608 34.872 ;
     RECT  18.469 0.192 18.611 0.216 ;
     RECT  18.608 2.016 18.904 34.872 ;
     RECT  18.904 2.016 18.965 7.416 ;
     RECT  18.904 30.48 18.965 30.888 ;
     RECT  18.904 34.224 19.043 34.872 ;
     RECT  18.965 2.88 19.325 7.416 ;
     RECT  19.043 34.224 19.361 34.776 ;
     RECT  19.325 2.88 19.865 6.408 ;
     RECT  18.904 8.88 19.901 8.904 ;
     RECT  18.904 10.8 19.937 10.824 ;
     RECT  18.965 30.48 19.973 30.504 ;
     RECT  19.865 3.84 20.045 6.408 ;
     RECT  20.045 3.84 20.051 6.312 ;
     RECT  20.041 2.256 20.053 2.28 ;
     RECT  20.185 14.832 20.297 14.856 ;
     RECT  19.325 7.392 20.401 7.416 ;
     RECT  19.361 34.224 20.533 34.248 ;
     RECT  20.053 1.728 21.005 2.28 ;
     RECT  20.051 3.84 21.005 6.12 ;
     RECT  20.533 34.224 21.109 34.776 ;
     RECT  21.005 1.728 21.157 6.12 ;
     RECT  20.401 7.392 21.157 7.992 ;
     RECT  21.157 1.728 21.308 8.184 ;
     RECT  21.121 18.816 21.308 18.84 ;
     RECT  20.293 31.296 21.308 31.32 ;
     RECT  21.109 34.224 21.308 34.92 ;
     RECT  21.308 1.728 21.539 34.92 ;
     RECT  21.539 1.728 21.604 34.824 ;
     RECT  21.604 3.216 22.067 6.264 ;
     RECT  22.067 3.84 22.313 6.264 ;
     RECT  21.604 18.672 22.673 18.696 ;
     RECT  22.741 30.768 22.813 30.792 ;
     RECT  22.313 3.84 23.497 6.12 ;
     RECT  21.604 1.728 23.645 1.8 ;
     RECT  22.849 2.832 23.749 2.856 ;
     RECT  23.497 3.84 23.749 6.312 ;
     RECT  22.813 30.672 23.749 30.888 ;
     RECT  23.281 18.768 23.821 18.792 ;
     RECT  23.821 18.72 23.929 18.792 ;
     RECT  23.645 1.776 23.965 1.8 ;
     RECT  23.749 2.832 23.965 6.312 ;
     RECT  23.965 1.776 24.008 6.312 ;
     RECT  21.604 7.392 24.008 8.184 ;
     RECT  23.929 18.72 24.008 18.84 ;
     RECT  23.929 26.784 24.008 26.808 ;
     RECT  23.749 30.48 24.008 30.888 ;
     RECT  21.604 34.224 24.008 34.824 ;
     RECT  24.008 1.776 24.229 34.824 ;
     RECT  24.229 1.776 24.304 34.872 ;
     RECT  24.304 26.784 24.401 26.904 ;
     RECT  24.304 34.224 24.419 34.872 ;
     RECT  24.304 18.48 24.437 18.744 ;
     RECT  24.401 26.784 24.437 26.808 ;
     RECT  24.419 34.224 24.515 34.248 ;
     RECT  24.304 1.776 24.709 7.416 ;
     RECT  24.709 1.728 25.309 7.416 ;
     RECT  24.437 18.72 25.337 18.744 ;
     RECT  25.333 0.144 25.427 0.168 ;
     RECT  25.309 1.728 25.597 6.312 ;
     RECT  24.304 30.72 25.733 31.32 ;
     RECT  25.717 34.752 25.957 34.776 ;
     RECT  25.957 34.704 26.197 34.776 ;
     RECT  25.733 30.72 26.437 31.272 ;
     RECT  26.437 30.672 26.581 31.272 ;
     RECT  26.197 34.224 26.581 34.776 ;
     RECT  25.597 1.728 26.708 6.264 ;
     RECT  25.309 7.392 26.708 7.416 ;
     RECT  26.581 30.624 26.708 31.272 ;
     RECT  26.581 34.224 26.708 34.824 ;
     RECT  26.708 1.728 27.004 34.824 ;
     RECT  27.004 30.48 27.137 30.696 ;
     RECT  26.581 0.192 27.155 0.216 ;
     RECT  27.004 34.224 27.155 34.824 ;
     RECT  27.155 34.224 27.317 34.344 ;
     RECT  27.137 30.48 27.965 30.552 ;
     RECT  27.317 34.224 28.393 34.248 ;
     RECT  28.393 34.224 28.693 34.776 ;
     RECT  27.004 1.728 28.897 1.752 ;
     RECT  27.004 2.88 28.897 7.416 ;
     RECT  28.897 1.728 28.979 7.416 ;
     RECT  27.965 30.528 29.173 30.552 ;
     RECT  29.221 0.288 29.249 0.312 ;
     RECT  29.173 30.528 29.269 30.696 ;
     RECT  28.979 2.148 29.408 7.416 ;
     RECT  29.269 30.528 29.408 31.224 ;
     RECT  28.693 34.224 29.408 34.824 ;
     RECT  29.249 0.288 29.653 0.552 ;
     RECT  29.408 2.148 29.653 34.824 ;
     RECT  29.653 2.148 29.704 34.872 ;
     RECT  29.704 34.752 29.843 34.872 ;
     RECT  29.653 0.192 30.089 0.552 ;
     RECT  29.704 2.148 30.233 7.416 ;
     RECT  30.233 2.148 30.409 2.328 ;
     RECT  29.704 30.672 30.413 31.224 ;
     RECT  30.409 1.728 30.556 2.328 ;
     RECT  30.233 3.84 30.737 7.416 ;
     RECT  30.556 1.728 30.805 1.752 ;
     RECT  30.413 30.672 30.809 30.792 ;
     RECT  30.769 0.144 30.853 0.168 ;
     RECT  30.805 1.152 30.953 1.752 ;
     RECT  30.737 3.84 31.381 3.864 ;
     RECT  30.809 30.672 31.381 30.744 ;
     RECT  30.953 1.728 31.667 1.752 ;
     RECT  31.381 30.48 31.861 30.744 ;
     RECT  29.843 34.752 31.909 34.776 ;
     RECT  31.909 0.288 31.949 0.312 ;
     RECT  31.949 0.288 32.033 0.552 ;
     RECT  31.381 3.312 32.108 3.864 ;
     RECT  30.737 4.944 32.108 7.416 ;
     RECT  31.861 30.48 32.108 31.224 ;
     RECT  31.909 34.656 32.108 34.968 ;
     RECT  32.033 0.288 32.195 0.312 ;
     RECT  32.108 2.016 32.404 34.968 ;
     RECT  32.404 34.224 32.435 34.968 ;
     RECT  32.404 2.016 32.465 7.992 ;
     RECT  32.435 34.224 33.077 34.776 ;
     RECT  32.404 30.72 33.149 31.224 ;
     RECT  33.077 34.704 33.437 34.776 ;
     RECT  32.465 2.688 33.445 7.992 ;
     RECT  33.445 2.208 33.491 7.992 ;
     RECT  33.149 30.816 33.589 31.224 ;
     RECT  33.692 0.144 34.019 0.168 ;
     RECT  33.491 2.208 34.357 7.416 ;
     RECT  33.437 34.752 34.357 34.776 ;
     RECT  34.357 34.752 34.597 34.824 ;
     RECT  34.357 1.728 34.661 7.416 ;
     RECT  34.661 1.824 34.808 7.416 ;
     RECT  33.589 30.816 34.808 31.32 ;
     RECT  34.597 34.224 34.808 34.824 ;
     RECT  34.808 1.824 34.883 34.824 ;
     RECT  34.883 2.148 34.912 34.824 ;
     RECT  34.912 2.418 35.077 34.824 ;
     RECT  35.077 2.418 35.104 34.872 ;
     RECT  35.104 34.752 35.219 34.872 ;
     RECT  35.077 0.192 35.66 0.216 ;
     RECT  35.66 0.144 35.797 0.216 ;
     RECT  35.219 34.752 35.838 34.824 ;
     RECT  35.838 34.752 35.921 34.776 ;
     RECT  35.797 0.144 36.227 0.552 ;
     RECT  36.085 1.728 36.229 1.752 ;
     RECT  35.104 2.832 36.229 6.36 ;
     RECT  35.104 30.72 36.325 30.744 ;
     RECT  36.227 0.528 36.497 0.552 ;
     RECT  36.325 30.72 36.565 31.32 ;
     RECT  36.229 1.728 36.817 6.36 ;
     RECT  35.104 7.392 36.817 7.416 ;
     RECT  36.565 30.672 37.045 31.32 ;
     RECT  37.045 30.624 37.333 31.32 ;
     RECT  36.085 34.224 37.381 34.248 ;
     RECT  36.817 1.728 37.508 7.416 ;
     RECT  37.333 30.576 37.508 31.32 ;
     RECT  37.381 34.224 37.508 34.824 ;
     RECT  37.508 1.728 37.804 34.824 ;
     RECT  37.804 30.576 38.045 31.224 ;
     RECT  37.804 1.728 38.081 7.416 ;
     RECT  38.081 1.728 38.117 2.904 ;
     RECT  37.804 34.224 38.189 34.824 ;
     RECT  37.804 8.544 38.195 8.568 ;
     RECT  38.101 0.528 38.225 0.552 ;
     RECT  38.045 30.816 38.369 31.224 ;
     RECT  37.804 18.768 38.513 18.792 ;
     RECT  38.189 34.752 38.774 34.824 ;
     RECT  38.876 0.144 38.963 0.168 ;
     RECT  38.533 35.904 39.017 35.928 ;
     RECT  38.117 1.728 39.229 2.76 ;
     RECT  38.774 34.752 39.229 34.776 ;
     RECT  39.061 31.296 39.781 31.32 ;
     RECT  39.661 0.288 39.973 0.312 ;
     RECT  39.229 1.728 40.013 2.856 ;
     RECT  39.781 30.672 40.021 31.32 ;
     RECT  39.229 34.224 40.069 34.776 ;
     RECT  40.013 1.728 40.208 2.904 ;
     RECT  38.081 3.984 40.208 7.416 ;
     RECT  40.021 30.144 40.208 31.32 ;
     RECT  40.069 34.224 40.208 34.824 ;
     RECT  39.973 0.288 40.307 0.36 ;
     RECT  40.208 1.728 40.501 34.824 ;
     RECT  40.501 1.728 40.504 34.872 ;
     RECT  40.504 34.752 40.643 34.872 ;
     RECT  40.504 30.144 40.673 31.128 ;
     RECT  40.504 3.84 40.745 4.008 ;
     RECT  40.504 1.728 41.033 2.28 ;
     RECT  40.673 30.72 41.069 31.128 ;
     RECT  40.745 3.84 41.489 3.96 ;
     RECT  40.307 0.288 41.507 0.312 ;
     RECT  41.069 30.72 41.537 30.84 ;
     RECT  40.504 5.136 41.857 6.312 ;
     RECT  40.504 8.016 41.929 8.04 ;
     RECT  40.643 34.752 42.229 34.776 ;
     RECT  41.033 1.728 42.275 1.752 ;
     RECT  41.489 2.832 42.361 3.96 ;
     RECT  41.857 5.136 42.361 6.408 ;
     RECT  41.929 7.968 42.389 8.04 ;
     RECT  42.332 0.144 42.419 0.168 ;
     RECT  42.229 34.752 42.517 34.824 ;
     RECT  42.361 2.832 42.668 6.408 ;
     RECT  42.389 7.44 42.668 8.04 ;
     RECT  41.537 30.72 42.757 30.744 ;
     RECT  42.668 2.832 42.908 8.04 ;
     RECT  42.757 30.672 42.908 30.744 ;
     RECT  42.517 34.224 42.908 34.824 ;
     RECT  42.908 2.016 43.204 34.824 ;
     RECT  43.204 34.224 43.331 34.824 ;
     RECT  43.204 2.016 43.373 6.888 ;
     RECT  43.204 30.672 43.373 30.744 ;
     RECT  43.373 2.016 43.469 6.648 ;
     RECT  43.469 1.728 43.481 6.648 ;
     RECT  43.373 30.672 43.697 30.696 ;
     RECT  43.717 35.904 43.913 35.928 ;
     RECT  42.997 0.288 43.955 0.312 ;
     RECT  43.481 1.728 43.957 2.904 ;
     RECT  43.481 3.888 44.341 6.648 ;
     RECT  43.957 1.728 44.387 2.28 ;
     RECT  43.331 34.224 44.417 34.776 ;
     RECT  44.341 3.888 44.437 6.888 ;
     RECT  44.413 8.544 44.497 8.568 ;
     RECT  44.437 3.888 44.524 7.368 ;
     RECT  44.524 3.888 44.684 6.888 ;
     RECT  44.725 30.816 44.965 30.84 ;
     RECT  44.417 34.704 45.205 34.776 ;
     RECT  44.684 3.312 45.313 6.888 ;
     RECT  44.387 1.728 45.397 1.8 ;
     RECT  45.313 2.784 45.397 6.888 ;
     RECT  45.205 34.704 45.425 34.824 ;
     RECT  44.965 30.72 45.445 30.84 ;
     RECT  45.397 1.728 45.608 6.888 ;
     RECT  44.737 7.968 45.608 7.992 ;
     RECT  45.445 30.672 45.608 30.84 ;
     RECT  45.425 34.704 45.608 34.728 ;
     RECT  45.349 0.528 45.641 0.552 ;
     RECT  45.608 1.728 45.904 34.728 ;
     RECT  45.904 1.728 45.965 8.04 ;
     RECT  45.904 34.224 46.001 34.728 ;
     RECT  45.965 1.728 46.109 7.992 ;
     RECT  46.109 7.968 46.153 7.992 ;
     RECT  46.109 1.728 46.613 6.84 ;
     RECT  46.613 1.728 46.757 6.648 ;
     RECT  46.757 3.168 46.829 6.648 ;
     RECT  46.829 3.216 47.653 6.648 ;
     RECT  47.653 3.216 47.797 6.888 ;
     RECT  47.516 0.144 47.989 0.168 ;
     RECT  47.989 0.144 48.131 0.552 ;
     RECT  46.757 1.728 48.133 1.752 ;
     RECT  47.797 2.88 48.133 6.888 ;
     RECT  45.904 30.672 48.133 31.32 ;
     RECT  46.001 34.224 48.133 34.248 ;
     RECT  48.133 30.624 48.181 31.32 ;
     RECT  48.133 1.728 48.308 6.888 ;
     RECT  47.545 7.968 48.308 7.992 ;
     RECT  48.181 30.144 48.308 31.32 ;
     RECT  48.133 34.224 48.308 34.728 ;
     RECT  48.131 0.528 48.341 0.552 ;
     RECT  48.308 1.728 48.604 34.728 ;
     RECT  48.604 34.56 48.755 34.728 ;
     RECT  48.604 1.728 48.899 7.464 ;
     RECT  48.899 1.728 49.097 6.648 ;
     RECT  48.604 30.144 49.313 31.08 ;
     RECT  49.097 1.728 49.393 2.904 ;
     RECT  49.141 34.752 49.669 34.776 ;
     RECT  49.097 4.032 50.101 6.648 ;
     RECT  49.393 1.728 50.149 1.752 ;
     RECT  50.149 1.68 50.249 1.752 ;
     RECT  49.313 30.816 50.389 31.08 ;
     RECT  49.393 2.784 50.497 2.904 ;
     RECT  50.497 2.148 50.597 2.904 ;
     RECT  50.101 3.936 50.597 6.648 ;
     RECT  49.669 34.752 50.629 34.824 ;
     RECT  50.597 2.148 50.857 6.648 ;
     RECT  50.857 2.148 51.008 6.888 ;
     RECT  50.533 26.784 51.008 26.808 ;
     RECT  50.389 30.48 51.008 31.08 ;
     RECT  50.629 34.224 51.008 34.824 ;
     RECT  50.821 0.288 51.203 0.312 ;
     RECT  51.008 2.148 51.304 34.824 ;
     RECT  51.304 34.752 51.833 34.824 ;
     RECT  51.361 1.728 51.865 1.752 ;
     RECT  51.304 2.736 52.085 2.856 ;
     RECT  51.865 1.152 52.163 1.752 ;
     RECT  51.304 3.936 52.547 6.648 ;
     RECT  52.357 2.88 52.597 2.904 ;
     RECT  51.304 30.48 52.625 31.032 ;
     RECT  52.597 2.88 52.693 2.952 ;
     RECT  52.547 3.936 52.693 6.6 ;
     RECT  52.693 2.88 53.084 6.6 ;
     RECT  52.357 35.904 53.237 35.928 ;
     RECT  51.833 34.8 53.365 34.824 ;
     RECT  52.163 1.728 53.593 1.752 ;
     RECT  53.221 7.584 53.665 7.608 ;
     RECT  53.593 1.728 53.708 1.848 ;
     RECT  53.084 2.832 53.708 6.6 ;
     RECT  53.665 7.584 53.708 8.328 ;
     RECT  53.593 19.296 53.708 19.32 ;
     RECT  52.625 30.48 53.708 30.84 ;
     RECT  53.365 34.224 53.708 34.824 ;
     RECT  53.708 1.728 54.004 34.824 ;
     RECT  53.557 0.528 54.029 0.552 ;
     RECT  54.004 19.104 54.101 19.32 ;
     RECT  54.004 34.224 54.101 34.824 ;
     RECT  54.004 3.936 54.131 7.368 ;
     RECT  54.101 34.224 54.172 34.248 ;
     RECT  54.131 3.936 54.173 6.6 ;
     RECT  54.004 8.448 54.317 8.472 ;
     RECT  54.004 1.728 54.605 2.904 ;
     RECT  54.101 19.104 54.605 19.128 ;
     RECT  54.605 2.256 54.785 2.904 ;
     RECT  54.785 2.832 55.093 2.904 ;
     RECT  54.173 3.936 55.093 6.312 ;
     RECT  55.093 2.832 55.217 6.312 ;
     RECT  54.004 30.48 55.361 31.32 ;
     RECT  55.361 30.48 55.433 30.84 ;
     RECT  55.217 3.936 55.537 6.312 ;
     RECT  55.333 33.648 55.573 33.672 ;
     RECT  55.537 3.936 55.681 6.84 ;
     RECT  55.573 1.728 55.82 1.752 ;
     RECT  55.217 2.832 55.82 2.952 ;
     RECT  55.573 33.648 56.053 34.248 ;
     RECT  55.969 0.144 56.185 0.168 ;
     RECT  56.185 0.144 56.195 0.216 ;
     RECT  55.82 1.728 56.293 2.952 ;
     RECT  55.681 3.936 56.293 7.464 ;
     RECT  56.053 33.648 56.369 34.824 ;
     RECT  56.369 33.648 56.387 34.728 ;
     RECT  56.293 1.728 56.408 7.464 ;
     RECT  55.433 30.48 56.408 30.6 ;
     RECT  56.387 33.648 56.408 34.68 ;
     RECT  56.195 0.192 56.437 0.216 ;
     RECT  56.408 1.728 56.704 34.68 ;
     RECT  56.437 0.192 56.819 0.312 ;
     RECT  56.704 34.224 56.819 34.68 ;
     RECT  56.819 34.224 57.388 34.296 ;
     RECT  56.704 1.728 57.521 7.512 ;
     RECT  57.164 0.144 57.923 0.168 ;
     RECT  56.704 30.192 58.025 30.84 ;
     RECT  57.521 2.256 58.117 7.512 ;
     RECT  58.117 2.256 58.549 7.896 ;
     RECT  57.388 34.224 58.988 34.248 ;
     RECT  58.549 1.728 59.108 7.896 ;
     RECT  58.021 9.12 59.108 9.144 ;
     RECT  58.561 11.952 59.108 11.976 ;
     RECT  58.025 30.192 59.108 30.792 ;
     RECT  58.988 34.224 59.108 34.728 ;
     RECT  58.933 0.192 59.269 0.216 ;
     RECT  59.108 1.728 59.269 34.728 ;
     RECT  59.269 1.728 59.404 34.824 ;
     RECT  59.269 0.192 59.555 0.312 ;
     RECT  59.555 0.192 59.651 0.216 ;
     RECT  59.404 1.728 59.861 6.936 ;
     RECT  59.861 3.888 59.897 6.936 ;
     RECT  59.897 3.936 59.904 6.84 ;
     RECT  59.861 1.728 60.221 2.904 ;
     RECT  59.404 18.816 60.329 18.84 ;
     RECT  59.404 30.72 60.473 30.84 ;
     RECT  60.473 30.72 60.725 30.744 ;
     RECT  60.221 1.728 61.301 2.28 ;
     RECT  61.301 1.776 61.517 2.28 ;
     RECT  61.517 2.016 61.525 2.28 ;
     RECT  61.525 2.016 61.613 2.952 ;
     RECT  59.904 3.936 61.613 6.6 ;
     RECT  61.613 2.016 61.621 6.6 ;
     RECT  59.404 34.224 61.621 34.824 ;
     RECT  61.621 2.016 61.808 6.84 ;
     RECT  61.621 30.576 61.808 30.696 ;
     RECT  61.621 34.224 61.808 34.92 ;
     RECT  61.669 0.192 61.811 0.216 ;
     RECT  61.808 2.016 62.051 34.92 ;
     RECT  62.051 2.016 62.104 34.824 ;
     RECT  62.104 30.576 62.381 30.84 ;
     RECT  62.104 34.224 62.705 34.824 ;
     RECT  62.104 2.016 62.965 7.176 ;
     RECT  62.965 1.728 63.281 7.176 ;
     RECT  62.705 34.704 63.281 34.824 ;
     RECT  63.281 34.752 63.461 34.824 ;
     RECT  62.381 30.816 63.493 30.84 ;
     RECT  63.493 30.72 63.733 30.84 ;
     RECT  63.733 30.672 63.973 30.84 ;
     RECT  63.493 0.528 64.019 0.552 ;
     RECT  63.281 2.256 64.421 6.168 ;
     RECT  63.461 34.752 64.453 34.776 ;
     RECT  64.421 2.016 64.508 6.168 ;
     RECT  63.281 7.152 64.508 7.176 ;
     RECT  64.105 14.832 64.508 14.856 ;
     RECT  63.973 30.576 64.508 30.84 ;
     RECT  64.453 34.752 64.508 34.824 ;
     RECT  64.508 2.016 64.693 34.824 ;
     RECT  64.693 2.016 64.804 34.92 ;
     RECT  64.804 34.224 64.979 34.92 ;
     RECT  64.804 4.128 65.189 7.176 ;
     RECT  64.979 34.224 65.405 34.776 ;
     RECT  64.804 2.88 65.621 2.952 ;
     RECT  65.621 2.88 65.837 2.904 ;
     RECT  64.981 1.728 65.941 1.752 ;
     RECT  64.804 31.296 65.941 31.32 ;
     RECT  65.941 30.48 66.161 31.32 ;
     RECT  65.941 1.728 66.373 1.8 ;
     RECT  65.189 5.184 66.373 6.888 ;
     RECT  66.373 5.184 66.661 7.464 ;
     RECT  65.189 4.176 67.021 4.2 ;
     RECT  65.405 34.224 67.093 34.248 ;
     RECT  66.709 35.328 67.093 35.352 ;
     RECT  67.093 34.224 67.133 35.352 ;
     RECT  66.373 1.728 67.208 1.848 ;
     RECT  67.021 3.408 67.208 4.2 ;
     RECT  66.661 5.184 67.208 7.656 ;
     RECT  66.161 30.48 67.208 31.224 ;
     RECT  67.133 34.224 67.208 34.824 ;
     RECT  67.208 1.728 67.504 34.824 ;
     RECT  67.429 0.192 67.619 0.216 ;
     RECT  67.504 34.704 67.619 34.824 ;
     RECT  67.504 3.36 67.811 8.04 ;
     RECT  67.669 35.904 67.889 35.928 ;
     RECT  67.504 1.728 67.997 2.232 ;
     RECT  67.504 30.72 67.997 31.224 ;
     RECT  67.619 34.704 68.213 34.776 ;
     RECT  67.811 3.936 68.357 8.04 ;
     RECT  68.213 34.752 68.357 34.776 ;
     RECT  68.357 7.968 68.537 8.04 ;
     RECT  68.357 3.936 68.867 6.84 ;
     RECT  67.997 30.816 68.917 31.224 ;
     RECT  68.917 30.816 69.157 31.32 ;
     RECT  68.867 4.512 69.349 6.84 ;
     RECT  68.537 7.968 69.349 7.992 ;
     RECT  68.677 34.8 69.389 34.824 ;
     RECT  67.997 1.728 69.781 1.848 ;
     RECT  69.389 34.752 69.781 34.824 ;
     RECT  69.781 1.728 69.908 3.336 ;
     RECT  69.349 4.512 69.908 7.992 ;
     RECT  69.157 30.72 69.908 31.32 ;
     RECT  69.781 34.368 69.908 34.824 ;
     RECT  69.908 1.728 70.204 34.824 ;
     RECT  70.204 34.752 70.355 34.824 ;
     RECT  70.204 4.512 70.589 6.84 ;
     RECT  70.589 4.512 70.661 6.12 ;
     RECT  70.204 30.48 70.769 30.792 ;
     RECT  70.645 35.904 70.885 35.928 ;
     RECT  70.204 2.88 70.949 3.432 ;
     RECT  70.949 3.408 71.101 3.432 ;
     RECT  70.204 1.728 71.201 1.848 ;
     RECT  70.355 34.752 71.365 34.776 ;
     RECT  70.661 4.512 71.597 6.024 ;
     RECT  70.885 35.904 71.633 35.976 ;
     RECT  71.365 34.224 71.893 34.776 ;
     RECT  71.201 1.728 71.965 1.752 ;
     RECT  71.953 3.312 72.133 3.336 ;
     RECT  72.133 3.024 72.341 3.336 ;
     RECT  72.421 0.288 72.469 0.312 ;
     RECT  72.341 2.88 72.493 3.336 ;
     RECT  72.493 2.88 72.608 3.432 ;
     RECT  71.597 4.56 72.608 6.024 ;
     RECT  70.769 30.48 72.608 30.504 ;
     RECT  71.893 34.224 72.608 35.352 ;
     RECT  72.469 0.192 72.659 0.312 ;
     RECT  72.659 0.192 72.899 0.216 ;
     RECT  72.608 2.148 72.904 35.352 ;
     RECT  72.904 4.512 73.037 6.024 ;
     RECT  72.904 34.752 73.505 35.352 ;
     RECT  73.505 34.752 73.541 34.776 ;
     RECT  73.037 4.512 73.859 5.736 ;
     RECT  73.859 4.512 74.081 5.16 ;
     RECT  72.904 3.312 74.149 3.384 ;
     RECT  74.081 4.512 74.149 4.68 ;
     RECT  74.149 3.312 74.153 4.68 ;
     RECT  74.153 3.312 74.261 3.864 ;
     RECT  73.093 1.728 74.549 1.752 ;
     RECT  74.261 3.84 75.308 3.864 ;
     RECT  75.308 2.148 75.412 34.572 ;
     RECT  75.412 2.418 75.604 34.302 ;
    LAYER M5 ;
     RECT  25.392 0.133 25.416 0.144 ;
     RECT  30.816 0.133 30.84 0.144 ;
     RECT  35.712 0.133 35.856 0.144 ;
     RECT  35.88 0.133 36.096 0.144 ;
     RECT  36.12 0.133 36.216 0.144 ;
     RECT  38.928 0.133 38.952 0.144 ;
     RECT  42.384 0.133 42.408 0.144 ;
     RECT  47.568 0.133 47.712 0.144 ;
     RECT  47.736 0.133 47.952 0.144 ;
     RECT  47.976 0.133 48.12 0.144 ;
     RECT  56.16 0.133 56.184 0.144 ;
     RECT  57.216 0.133 57.312 0.144 ;
     RECT  57.336 0.133 57.552 0.144 ;
     RECT  57.576 0.133 57.792 0.144 ;
     RECT  57.816 0.133 57.912 0.144 ;
     RECT  4.536 0.144 4.752 0.192 ;
     RECT  4.776 0.144 4.992 0.192 ;
     RECT  5.016 0.144 5.232 0.192 ;
     RECT  5.256 0.144 5.472 0.192 ;
     RECT  5.496 0.144 5.712 0.192 ;
     RECT  5.736 0.144 5.952 0.192 ;
     RECT  5.976 0.144 6.24 0.192 ;
     RECT  6.264 0.144 6.48 0.192 ;
     RECT  6.504 0.144 6.72 0.192 ;
     RECT  6.744 0.144 6.96 0.192 ;
     RECT  6.984 0.144 7.2 0.192 ;
     RECT  7.224 0.144 7.44 0.192 ;
     RECT  7.464 0.144 7.68 0.192 ;
     RECT  7.704 0.144 7.968 0.192 ;
     RECT  7.992 0.144 8.208 0.192 ;
     RECT  8.232 0.144 8.448 0.192 ;
     RECT  8.472 0.144 8.688 0.192 ;
     RECT  8.712 0.144 8.928 0.192 ;
     RECT  8.952 0.144 9.168 0.192 ;
     RECT  9.192 0.144 9.408 0.192 ;
     RECT  9.432 0.144 9.696 0.192 ;
     RECT  9.72 0.144 9.936 0.192 ;
     RECT  9.96 0.144 10.176 0.192 ;
     RECT  10.2 0.144 10.416 0.192 ;
     RECT  10.44 0.144 10.656 0.192 ;
     RECT  10.68 0.144 10.896 0.192 ;
     RECT  10.92 0.144 11.136 0.192 ;
     RECT  11.16 0.144 11.424 0.192 ;
     RECT  11.448 0.144 11.664 0.192 ;
     RECT  11.688 0.144 11.904 0.192 ;
     RECT  11.928 0.144 12.144 0.192 ;
     RECT  12.168 0.144 12.384 0.192 ;
     RECT  12.408 0.144 12.624 0.192 ;
     RECT  12.648 0.144 12.864 0.192 ;
     RECT  12.888 0.144 13.152 0.192 ;
     RECT  13.176 0.144 13.392 0.192 ;
     RECT  13.416 0.144 13.632 0.192 ;
     RECT  13.656 0.144 13.872 0.192 ;
     RECT  13.896 0.144 14.112 0.192 ;
     RECT  14.136 0.144 14.352 0.192 ;
     RECT  14.376 0.144 14.592 0.192 ;
     RECT  14.616 0.144 14.88 0.192 ;
     RECT  14.904 0.144 15.12 0.192 ;
     RECT  15.144 0.144 15.36 0.192 ;
     RECT  15.384 0.144 15.6 0.192 ;
     RECT  15.624 0.144 15.84 0.192 ;
     RECT  15.864 0.144 16.08 0.192 ;
     RECT  16.104 0.144 16.32 0.192 ;
     RECT  16.344 0.144 16.608 0.192 ;
     RECT  16.632 0.144 16.848 0.192 ;
     RECT  16.872 0.144 17.088 0.192 ;
     RECT  17.112 0.144 17.328 0.192 ;
     RECT  17.352 0.144 17.568 0.192 ;
     RECT  17.592 0.144 17.808 0.192 ;
     RECT  17.832 0.144 18.048 0.192 ;
     RECT  18.072 0.144 18.336 0.192 ;
     RECT  18.36 0.144 18.576 0.192 ;
     RECT  18.6 0.144 18.816 0.192 ;
     RECT  18.84 0.144 19.056 0.192 ;
     RECT  19.08 0.144 19.296 0.192 ;
     RECT  19.32 0.144 19.536 0.192 ;
     RECT  19.56 0.144 19.776 0.192 ;
     RECT  19.8 0.144 20.064 0.192 ;
     RECT  20.088 0.144 20.304 0.192 ;
     RECT  20.328 0.144 20.544 0.192 ;
     RECT  20.568 0.144 20.784 0.192 ;
     RECT  20.808 0.144 21.024 0.192 ;
     RECT  21.048 0.144 21.264 0.192 ;
     RECT  21.288 0.144 21.504 0.192 ;
     RECT  21.528 0.144 21.792 0.192 ;
     RECT  21.816 0.144 22.032 0.192 ;
     RECT  22.056 0.144 22.272 0.192 ;
     RECT  22.296 0.144 22.512 0.192 ;
     RECT  22.536 0.144 22.752 0.192 ;
     RECT  22.776 0.144 22.992 0.192 ;
     RECT  23.016 0.144 23.232 0.192 ;
     RECT  23.256 0.144 23.52 0.192 ;
     RECT  23.544 0.144 23.76 0.192 ;
     RECT  23.784 0.144 24 0.192 ;
     RECT  24.024 0.144 24.24 0.192 ;
     RECT  24.264 0.144 24.48 0.192 ;
     RECT  24.504 0.144 24.72 0.192 ;
     RECT  24.744 0.144 24.96 0.192 ;
     RECT  24.984 0.144 25.248 0.192 ;
     RECT  25.272 0.144 25.488 0.192 ;
     RECT  25.512 0.144 25.728 0.192 ;
     RECT  25.752 0.144 25.968 0.192 ;
     RECT  25.992 0.144 26.208 0.192 ;
     RECT  26.232 0.144 26.448 0.192 ;
     RECT  26.472 0.144 26.688 0.192 ;
     RECT  26.712 0.144 26.976 0.192 ;
     RECT  27 0.144 27.216 0.192 ;
     RECT  27.24 0.144 27.456 0.192 ;
     RECT  27.48 0.144 27.696 0.192 ;
     RECT  27.72 0.144 27.936 0.192 ;
     RECT  27.96 0.144 28.176 0.192 ;
     RECT  28.2 0.144 28.416 0.192 ;
     RECT  28.44 0.144 28.704 0.192 ;
     RECT  28.728 0.144 28.944 0.192 ;
     RECT  28.968 0.144 29.184 0.192 ;
     RECT  29.208 0.144 29.424 0.192 ;
     RECT  29.448 0.144 29.664 0.192 ;
     RECT  29.688 0.144 29.904 0.192 ;
     RECT  29.928 0.144 30.144 0.192 ;
     RECT  30.168 0.144 30.432 0.192 ;
     RECT  30.456 0.144 30.672 0.192 ;
     RECT  30.696 0.144 30.912 0.192 ;
     RECT  30.936 0.144 31.152 0.192 ;
     RECT  31.176 0.144 31.392 0.192 ;
     RECT  31.416 0.144 31.632 0.192 ;
     RECT  31.656 0.144 31.872 0.192 ;
     RECT  31.896 0.144 32.16 0.192 ;
     RECT  32.184 0.144 32.4 0.192 ;
     RECT  32.424 0.144 32.64 0.192 ;
     RECT  32.664 0.144 32.88 0.192 ;
     RECT  32.904 0.144 33.12 0.192 ;
     RECT  33.144 0.144 33.36 0.192 ;
     RECT  33.384 0.144 33.6 0.192 ;
     RECT  33.624 0.144 33.888 0.192 ;
     RECT  33.912 0.144 34.128 0.192 ;
     RECT  34.152 0.144 34.368 0.192 ;
     RECT  34.392 0.144 34.608 0.192 ;
     RECT  34.632 0.144 34.848 0.192 ;
     RECT  34.872 0.144 35.088 0.192 ;
     RECT  35.112 0.144 35.328 0.192 ;
     RECT  35.352 0.144 35.616 0.192 ;
     RECT  35.64 0.144 35.856 0.192 ;
     RECT  35.88 0.144 36.096 0.192 ;
     RECT  36.12 0.144 36.336 0.192 ;
     RECT  36.36 0.144 36.576 0.192 ;
     RECT  36.6 0.144 36.816 0.192 ;
     RECT  36.84 0.144 37.056 0.192 ;
     RECT  37.08 0.144 37.344 0.192 ;
     RECT  37.368 0.144 37.584 0.192 ;
     RECT  37.608 0.144 37.824 0.192 ;
     RECT  37.848 0.144 38.064 0.192 ;
     RECT  38.088 0.144 38.304 0.192 ;
     RECT  38.328 0.144 38.544 0.192 ;
     RECT  38.568 0.144 38.784 0.192 ;
     RECT  38.808 0.144 39.072 0.192 ;
     RECT  39.096 0.144 39.312 0.192 ;
     RECT  39.336 0.144 39.552 0.192 ;
     RECT  39.576 0.144 39.792 0.192 ;
     RECT  39.816 0.144 40.032 0.192 ;
     RECT  40.056 0.144 40.272 0.192 ;
     RECT  40.296 0.144 40.512 0.192 ;
     RECT  40.536 0.144 40.8 0.192 ;
     RECT  40.824 0.144 41.04 0.192 ;
     RECT  41.064 0.144 41.28 0.192 ;
     RECT  41.304 0.144 41.52 0.192 ;
     RECT  41.544 0.144 41.76 0.192 ;
     RECT  41.784 0.144 42 0.192 ;
     RECT  42.024 0.144 42.24 0.192 ;
     RECT  42.264 0.144 42.528 0.192 ;
     RECT  42.552 0.144 42.768 0.192 ;
     RECT  42.792 0.144 43.008 0.192 ;
     RECT  43.032 0.144 43.248 0.192 ;
     RECT  43.272 0.144 43.488 0.192 ;
     RECT  43.512 0.144 43.728 0.192 ;
     RECT  43.752 0.144 43.968 0.192 ;
     RECT  43.992 0.144 44.256 0.192 ;
     RECT  44.28 0.144 44.496 0.192 ;
     RECT  44.52 0.144 44.736 0.192 ;
     RECT  44.76 0.144 44.976 0.192 ;
     RECT  45 0.144 45.216 0.192 ;
     RECT  45.24 0.144 45.456 0.192 ;
     RECT  45.48 0.144 45.696 0.192 ;
     RECT  45.72 0.144 45.984 0.192 ;
     RECT  46.008 0.144 46.224 0.192 ;
     RECT  46.248 0.144 46.464 0.192 ;
     RECT  46.488 0.144 46.704 0.192 ;
     RECT  46.728 0.144 46.944 0.192 ;
     RECT  46.968 0.144 47.184 0.192 ;
     RECT  47.208 0.144 47.424 0.192 ;
     RECT  47.448 0.144 47.712 0.192 ;
     RECT  47.736 0.144 47.952 0.192 ;
     RECT  47.976 0.144 48.192 0.192 ;
     RECT  48.216 0.144 48.432 0.192 ;
     RECT  48.456 0.144 48.672 0.192 ;
     RECT  48.696 0.144 48.912 0.192 ;
     RECT  48.936 0.144 49.152 0.192 ;
     RECT  49.176 0.144 49.44 0.192 ;
     RECT  49.464 0.144 49.68 0.192 ;
     RECT  49.704 0.144 49.92 0.192 ;
     RECT  49.944 0.144 50.16 0.192 ;
     RECT  50.184 0.144 50.4 0.192 ;
     RECT  50.424 0.144 50.64 0.192 ;
     RECT  50.664 0.144 50.88 0.192 ;
     RECT  50.904 0.144 51.168 0.192 ;
     RECT  51.192 0.144 51.408 0.192 ;
     RECT  51.432 0.144 51.648 0.192 ;
     RECT  51.672 0.144 51.888 0.192 ;
     RECT  51.912 0.144 52.128 0.192 ;
     RECT  52.152 0.144 52.368 0.192 ;
     RECT  52.392 0.144 52.608 0.192 ;
     RECT  52.632 0.144 52.896 0.192 ;
     RECT  52.92 0.144 53.136 0.192 ;
     RECT  53.16 0.144 53.376 0.192 ;
     RECT  53.4 0.144 53.616 0.192 ;
     RECT  53.64 0.144 53.856 0.192 ;
     RECT  53.88 0.144 54.096 0.192 ;
     RECT  54.12 0.144 54.336 0.192 ;
     RECT  54.36 0.144 54.624 0.192 ;
     RECT  54.648 0.144 54.864 0.192 ;
     RECT  54.888 0.144 55.104 0.192 ;
     RECT  55.128 0.144 55.344 0.192 ;
     RECT  55.368 0.144 55.584 0.192 ;
     RECT  55.608 0.144 55.824 0.192 ;
     RECT  55.848 0.144 56.064 0.192 ;
     RECT  56.088 0.144 56.352 0.192 ;
     RECT  56.376 0.144 56.592 0.192 ;
     RECT  56.616 0.144 56.832 0.192 ;
     RECT  56.856 0.144 57.072 0.192 ;
     RECT  57.096 0.144 57.312 0.192 ;
     RECT  57.336 0.144 57.552 0.192 ;
     RECT  57.576 0.144 57.792 0.192 ;
     RECT  57.816 0.144 58.08 0.192 ;
     RECT  58.104 0.144 58.32 0.192 ;
     RECT  58.344 0.144 58.56 0.192 ;
     RECT  58.584 0.144 58.8 0.192 ;
     RECT  58.824 0.144 59.04 0.192 ;
     RECT  59.064 0.144 59.28 0.192 ;
     RECT  59.304 0.144 59.52 0.192 ;
     RECT  59.544 0.144 59.808 0.192 ;
     RECT  59.832 0.144 60.048 0.192 ;
     RECT  60.072 0.144 60.288 0.192 ;
     RECT  60.312 0.144 60.528 0.192 ;
     RECT  60.552 0.144 60.768 0.192 ;
     RECT  60.792 0.144 61.008 0.192 ;
     RECT  61.032 0.144 61.248 0.192 ;
     RECT  61.272 0.144 61.536 0.192 ;
     RECT  61.56 0.144 61.776 0.192 ;
     RECT  61.8 0.144 62.016 0.192 ;
     RECT  62.04 0.144 62.256 0.192 ;
     RECT  62.28 0.144 62.496 0.192 ;
     RECT  62.52 0.144 62.736 0.192 ;
     RECT  62.76 0.144 62.976 0.192 ;
     RECT  63 0.144 63.264 0.192 ;
     RECT  63.288 0.144 63.504 0.192 ;
     RECT  63.528 0.144 63.744 0.192 ;
     RECT  63.768 0.144 63.984 0.192 ;
     RECT  64.008 0.144 64.224 0.192 ;
     RECT  64.248 0.144 64.464 0.192 ;
     RECT  64.488 0.144 64.704 0.192 ;
     RECT  64.728 0.144 64.992 0.192 ;
     RECT  65.016 0.144 65.232 0.192 ;
     RECT  65.256 0.144 65.472 0.192 ;
     RECT  65.496 0.144 65.712 0.192 ;
     RECT  65.736 0.144 65.952 0.192 ;
     RECT  65.976 0.144 66.192 0.192 ;
     RECT  66.216 0.144 66.432 0.192 ;
     RECT  66.456 0.144 66.72 0.192 ;
     RECT  66.744 0.144 66.96 0.192 ;
     RECT  66.984 0.144 67.2 0.192 ;
     RECT  67.224 0.144 67.44 0.192 ;
     RECT  67.464 0.144 67.68 0.192 ;
     RECT  67.704 0.144 67.92 0.192 ;
     RECT  67.944 0.144 68.16 0.192 ;
     RECT  68.184 0.144 68.448 0.192 ;
     RECT  68.472 0.144 68.688 0.192 ;
     RECT  68.712 0.144 68.928 0.192 ;
     RECT  68.952 0.144 69.168 0.192 ;
     RECT  69.192 0.144 69.408 0.192 ;
     RECT  69.432 0.144 69.648 0.192 ;
     RECT  69.672 0.144 69.888 0.192 ;
     RECT  69.912 0.144 70.176 0.192 ;
     RECT  70.2 0.144 70.416 0.192 ;
     RECT  70.44 0.144 70.656 0.192 ;
     RECT  70.68 0.144 70.896 0.192 ;
     RECT  70.92 0.144 71.136 0.192 ;
     RECT  71.16 0.144 71.376 0.192 ;
     RECT  71.4 0.144 71.616 0.192 ;
     RECT  71.64 0.144 71.904 0.192 ;
     RECT  71.928 0.144 72.144 0.192 ;
     RECT  72.168 0.144 72.384 0.192 ;
     RECT  72.408 0.144 72.624 0.192 ;
     RECT  72.648 0.144 72.864 0.192 ;
     RECT  72.888 0.144 73.104 0.192 ;
     RECT  73.128 0.144 73.344 0.192 ;
     RECT  4.512 0.192 73.368 1.763 ;
     RECT  6.96 1.763 51.312 1.811 ;
     RECT  52.368 1.763 71.16 1.859 ;
     RECT  2.4 2.137 2.52 2.151 ;
     RECT  75.3 2.137 75.42 2.151 ;
     RECT  52.368 1.859 65.496 2.291 ;
     RECT  23.76 1.811 51.312 2.725 ;
     RECT  52.368 2.291 60.552 2.725 ;
     RECT  23.76 2.725 60.552 2.821 ;
     RECT  6.96 1.811 14.136 2.915 ;
     RECT  15.36 1.811 16.344 2.915 ;
     RECT  17.568 1.811 21.612 2.915 ;
     RECT  18.6 2.915 21.612 2.963 ;
     RECT  23.328 2.821 60.552 2.963 ;
     RECT  61.536 2.291 65.496 2.963 ;
     RECT  7.2 2.915 8.472 3.011 ;
     RECT  72.144 1.763 72.912 3.059 ;
     RECT  10.176 2.915 14.136 3.155 ;
     RECT  20.304 2.963 21.612 3.205 ;
     RECT  15.744 2.915 16.344 3.347 ;
     RECT  69.792 1.859 71.064 3.347 ;
     RECT  67.2 1.859 68.184 3.397 ;
     RECT  7.44 3.011 8.472 3.443 ;
     RECT  12.144 3.155 14.136 3.443 ;
     RECT  15.9 3.347 16.344 3.443 ;
     RECT  18.6 2.963 19.08 3.443 ;
     RECT  23.328 2.963 51.72 3.443 ;
     RECT  52.704 2.963 60.552 3.443 ;
     RECT  69.9 3.347 71.064 3.443 ;
     RECT  67.056 3.397 68.184 3.925 ;
     RECT  18.6 3.443 18.912 3.973 ;
     RECT  7.44 3.443 8.112 4.019 ;
     RECT  12.384 3.443 14.136 4.019 ;
     RECT  31.92 3.443 51.72 4.067 ;
     RECT  55.728 3.443 60.552 4.117 ;
     RECT  61.584 2.963 64.812 4.117 ;
     RECT  10.176 3.155 11.112 4.261 ;
     RECT  20.304 3.205 22.056 4.261 ;
     RECT  19.968 4.261 22.056 4.403 ;
     RECT  23.328 3.443 30.936 4.453 ;
     RECT  18.144 3.973 18.912 4.501 ;
     RECT  19.968 4.403 19.992 4.501 ;
     RECT  52.704 3.443 54.744 4.501 ;
     RECT  55.728 4.117 64.812 4.501 ;
     RECT  69.9 3.443 70.212 4.501 ;
     RECT  72.432 3.059 72.912 4.501 ;
     RECT  4.032 3.301 4.056 4.595 ;
     RECT  52.704 4.501 64.812 4.595 ;
     RECT  13.2 4.019 14.136 4.643 ;
     RECT  60.384 4.595 64.812 4.643 ;
     RECT  67.056 3.925 68.856 4.643 ;
     RECT  18.144 4.501 19.992 4.691 ;
     RECT  39.264 4.067 51.72 4.691 ;
     RECT  72.432 4.501 73.848 4.739 ;
     RECT  39.264 4.691 49.56 4.931 ;
     RECT  5.1 1.763 5.412 4.933 ;
     RECT  21.168 4.403 22.056 5.029 ;
     RECT  23.232 4.453 30.936 5.029 ;
     RECT  31.92 4.067 38.28 5.029 ;
     RECT  15.9 3.443 16.212 5.077 ;
     RECT  13.2 4.643 13.512 5.125 ;
     RECT  15.9 5.077 16.344 5.125 ;
     RECT  9.648 4.261 11.112 5.171 ;
     RECT  14.592 5.029 14.616 5.171 ;
     RECT  21.168 5.029 38.28 5.171 ;
     RECT  50.544 4.691 51.72 5.171 ;
     RECT  18.48 4.691 19.992 5.267 ;
     RECT  39.264 4.931 46.104 5.363 ;
     RECT  5.1 4.933 5.832 5.459 ;
     RECT  19.968 5.267 19.992 5.605 ;
     RECT  52.704 4.595 59.412 5.605 ;
     RECT  39.264 5.363 41.064 5.747 ;
     RECT  72.6 4.739 73.848 5.747 ;
     RECT  47.088 4.931 49.56 5.795 ;
     RECT  50.544 5.171 51.312 5.795 ;
     RECT  15.9 5.125 16.632 5.797 ;
     RECT  67.056 4.643 67.848 5.843 ;
     RECT  67.056 5.843 67.752 5.845 ;
     RECT  21.3 5.171 25.704 5.987 ;
     RECT  13.104 5.125 13.512 5.989 ;
     RECT  68.832 4.643 68.856 5.989 ;
     RECT  69.9 4.501 70.824 5.989 ;
     RECT  68.832 5.989 70.824 6.035 ;
     RECT  21.3 5.987 25.56 6.131 ;
     RECT  9.648 5.171 10.812 6.323 ;
     RECT  18.48 5.267 18.912 6.323 ;
     RECT  19.968 5.605 20.04 6.323 ;
     RECT  23.232 6.131 25.56 6.323 ;
     RECT  26.7 5.171 33.624 6.323 ;
     RECT  34.8 5.171 38.28 6.323 ;
     RECT  47.712 5.795 49.56 6.323 ;
     RECT  52.416 5.605 59.412 6.323 ;
     RECT  60.384 4.643 63.24 6.323 ;
     RECT  34.8 6.323 35.64 6.371 ;
     RECT  39.696 5.747 41.064 6.373 ;
     RECT  42.048 5.363 46.104 6.373 ;
     RECT  19.968 6.323 19.992 6.419 ;
     RECT  55.728 6.323 59.412 6.419 ;
     RECT  37.008 6.323 38.28 6.563 ;
     RECT  39.696 6.373 46.104 6.563 ;
     RECT  50.88 5.795 51.312 6.611 ;
     RECT  60.816 6.323 63.24 6.611 ;
     RECT  12.192 5.989 13.512 6.659 ;
     RECT  52.512 6.323 54.12 6.659 ;
     RECT  10.5 6.323 10.812 6.661 ;
     RECT  12.192 6.659 12.216 6.661 ;
     RECT  68.832 6.035 70.212 6.803 ;
     RECT  21.3 6.131 22.152 6.805 ;
     RECT  55.824 6.419 59.412 6.805 ;
     RECT  30.816 6.323 33.48 6.851 ;
     RECT  10.5 6.661 12.216 6.899 ;
     RECT  15.456 5.797 16.632 6.899 ;
     RECT  26.7 6.323 27.192 6.899 ;
     RECT  28.368 6.323 29.712 6.899 ;
     RECT  31.68 6.851 33.48 6.899 ;
     RECT  39.696 6.563 43.32 6.899 ;
     RECT  47.712 6.323 48.888 6.899 ;
     RECT  37.008 6.563 38.184 6.947 ;
     RECT  55.824 6.805 59.832 6.947 ;
     RECT  61.8 6.611 63.24 6.947 ;
     RECT  23.232 6.323 25.272 6.995 ;
     RECT  39.936 6.899 43.212 7.139 ;
     RECT  63.216 6.947 63.24 7.187 ;
     RECT  37.056 6.947 38.184 7.235 ;
     RECT  53.232 6.659 54.12 7.379 ;
     RECT  47.856 6.899 48.888 7.475 ;
     RECT  55.824 6.947 59.412 7.475 ;
     RECT  66.384 5.845 67.752 7.475 ;
     RECT  21.168 6.805 22.152 7.523 ;
     RECT  56.4 7.475 59.412 7.523 ;
     RECT  15.456 6.899 16.212 7.619 ;
     RECT  53.232 7.379 54.012 7.619 ;
     RECT  66.672 7.475 67.752 7.667 ;
     RECT  23.232 6.995 24.312 8.003 ;
     RECT  32.1 6.899 33.48 8.003 ;
     RECT  40.2 7.139 43.212 8.003 ;
     RECT  44.448 6.563 46.104 8.003 ;
     RECT  47.856 7.475 48.612 8.003 ;
     RECT  69.36 6.803 70.212 8.003 ;
     RECT  40.2 8.003 41.016 8.051 ;
     RECT  42.72 8.003 43.212 8.051 ;
     RECT  67.2 7.667 67.752 8.051 ;
     RECT  21.168 7.523 21.612 8.195 ;
     RECT  37.5 7.235 38.184 8.579 ;
     RECT  44.448 8.003 44.472 8.579 ;
     RECT  58.128 7.523 59.412 9.155 ;
     RECT  0.24 7.381 0.264 18.419 ;
     RECT  40.2 8.051 40.512 30.133 ;
     RECT  48.3 8.003 48.612 30.133 ;
     RECT  56.4 7.523 56.712 30.181 ;
     RECT  10.5 6.899 10.812 30.469 ;
     RECT  18.6 6.323 18.912 30.469 ;
     RECT  24 8.003 24.312 30.469 ;
     RECT  26.7 6.899 27.012 30.469 ;
     RECT  32.1 8.003 32.412 30.469 ;
     RECT  51 6.611 51.312 30.469 ;
     RECT  53.7 7.619 54.012 30.469 ;
     RECT  69.9 8.003 70.212 30.469 ;
     RECT  26.7 30.469 27.48 30.517 ;
     RECT  53.7 30.469 54.888 30.517 ;
     RECT  56.4 30.181 56.808 30.517 ;
     RECT  10.5 30.469 11.688 30.565 ;
     RECT  13.2 6.659 13.512 30.565 ;
     RECT  37.5 8.579 37.812 30.565 ;
     RECT  61.8 6.947 62.112 30.565 ;
     RECT  64.5 4.643 64.812 30.565 ;
     RECT  26.7 30.517 27.96 30.613 ;
     RECT  37.344 30.565 37.812 30.613 ;
     RECT  48.192 30.133 48.612 30.613 ;
     RECT  5.1 5.459 5.412 30.661 ;
     RECT  7.8 4.019 8.112 30.661 ;
     RECT  23.76 30.469 24.312 30.661 ;
     RECT  26.592 30.613 27.96 30.661 ;
     RECT  29.4 6.899 29.712 30.661 ;
     RECT  31.392 30.469 32.412 30.661 ;
     RECT  37.056 30.613 37.812 30.661 ;
     RECT  40.032 30.133 40.512 30.661 ;
     RECT  42.9 8.051 43.212 30.661 ;
     RECT  45.6 8.003 45.912 30.661 ;
     RECT  48.144 30.613 48.612 30.661 ;
     RECT  58.08 30.181 58.104 30.661 ;
     RECT  59.1 9.155 59.412 30.661 ;
     RECT  63.984 30.565 64.812 30.661 ;
     RECT  4.992 30.661 5.412 30.709 ;
     RECT  7.44 30.661 8.112 30.709 ;
     RECT  9.408 30.469 9.432 30.709 ;
     RECT  22.848 30.661 24.312 30.709 ;
     RECT  29.184 30.661 32.412 30.709 ;
     RECT  34.8 6.371 35.112 30.709 ;
     RECT  39.792 30.661 40.512 30.709 ;
     RECT  42.768 30.661 43.212 30.709 ;
     RECT  45.456 30.661 48.612 30.709 ;
     RECT  53.7 30.517 56.808 30.709 ;
     RECT  58.08 30.661 59.412 30.709 ;
     RECT  63.744 30.661 64.812 30.709 ;
     RECT  65.952 30.469 65.976 30.709 ;
     RECT  67.2 8.051 67.512 30.709 ;
     RECT  69.9 30.469 71.16 30.709 ;
     RECT  22.848 30.709 25.272 30.757 ;
     RECT  22.752 30.757 25.272 30.803 ;
     RECT  10.5 30.565 13.512 30.805 ;
     RECT  14.592 30.709 14.616 30.805 ;
     RECT  36.576 30.661 37.812 30.805 ;
     RECT  44.976 30.709 48.612 30.805 ;
     RECT  50.4 30.469 52.152 30.805 ;
     RECT  53.7 30.709 56.856 30.805 ;
     RECT  58.08 30.709 60.312 30.805 ;
     RECT  61.632 30.565 62.112 30.805 ;
     RECT  63.504 30.709 64.812 30.805 ;
     RECT  65.952 30.709 67.608 30.805 ;
     RECT  69.168 30.709 71.16 30.805 ;
     RECT  7.44 30.709 9.432 30.853 ;
     RECT  10.5 30.805 14.904 30.853 ;
     RECT  17.568 30.805 17.592 30.853 ;
     RECT  18.6 30.469 19.56 30.853 ;
     RECT  7.44 30.853 14.904 30.949 ;
     RECT  15.9 7.619 16.212 30.949 ;
     RECT  44.736 30.805 48.744 30.997 ;
     RECT  44.736 30.997 48.936 31.045 ;
     RECT  49.92 30.805 60.312 31.045 ;
     RECT  23.76 30.803 25.272 31.237 ;
     RECT  26.448 30.661 27.96 31.237 ;
     RECT  4.992 30.709 5.976 31.285 ;
     RECT  7.44 30.949 16.212 31.285 ;
     RECT  17.568 30.853 19.56 31.285 ;
     RECT  29.184 30.709 32.904 31.285 ;
     RECT  36.576 30.805 38.088 31.285 ;
     RECT  39.792 30.709 43.32 31.285 ;
     RECT  61.632 30.805 64.812 31.285 ;
     RECT  65.952 30.805 71.16 31.285 ;
     RECT  4.992 31.285 16.344 34.213 ;
     RECT  17.568 31.285 20.328 34.213 ;
     RECT  21.3 8.195 21.612 34.213 ;
     RECT  22.752 30.803 22.776 34.213 ;
     RECT  23.76 31.237 27.96 34.213 ;
     RECT  34.8 30.709 35.352 34.213 ;
     RECT  36.336 31.285 38.088 34.213 ;
     RECT  39.072 31.285 43.32 34.213 ;
     RECT  44.736 31.045 60.312 34.213 ;
     RECT  61.632 31.285 71.16 34.213 ;
     RECT  4.992 34.213 20.328 34.357 ;
     RECT  21.3 34.213 28.2 34.357 ;
     RECT  72.6 5.747 72.912 34.453 ;
     RECT  2.4 2.151 2.712 34.569 ;
     RECT  75.3 2.151 75.612 34.569 ;
     RECT  2.4 34.569 2.52 34.583 ;
     RECT  75.3 34.569 75.42 34.583 ;
     RECT  72.48 34.453 72.912 34.645 ;
     RECT  4.992 34.357 28.2 34.741 ;
     RECT  29.184 31.285 33.624 34.741 ;
     RECT  34.608 34.213 38.088 34.741 ;
     RECT  39.072 34.213 71.4 34.741 ;
     RECT  72.432 34.645 72.912 34.741 ;
     RECT  4.512 34.741 73.368 36.528 ;
     RECT  4.536 36.528 4.752 36.56 ;
     RECT  4.776 36.528 4.992 36.56 ;
     RECT  5.016 36.528 5.232 36.56 ;
     RECT  5.256 36.528 5.472 36.56 ;
     RECT  5.496 36.528 5.712 36.56 ;
     RECT  5.736 36.528 5.952 36.56 ;
     RECT  5.976 36.528 6.24 36.56 ;
     RECT  6.264 36.528 6.48 36.56 ;
     RECT  6.504 36.528 6.72 36.56 ;
     RECT  6.744 36.528 6.96 36.56 ;
     RECT  6.984 36.528 7.2 36.56 ;
     RECT  7.224 36.528 7.44 36.56 ;
     RECT  7.464 36.528 7.68 36.56 ;
     RECT  7.704 36.528 7.968 36.56 ;
     RECT  7.992 36.528 8.208 36.56 ;
     RECT  8.232 36.528 8.448 36.56 ;
     RECT  8.472 36.528 8.688 36.56 ;
     RECT  8.712 36.528 8.928 36.56 ;
     RECT  8.952 36.528 9.168 36.56 ;
     RECT  9.192 36.528 9.408 36.56 ;
     RECT  9.432 36.528 9.696 36.56 ;
     RECT  9.72 36.528 9.936 36.56 ;
     RECT  9.96 36.528 10.176 36.56 ;
     RECT  10.2 36.528 10.416 36.56 ;
     RECT  10.44 36.528 10.656 36.56 ;
     RECT  10.68 36.528 10.896 36.56 ;
     RECT  10.92 36.528 11.136 36.56 ;
     RECT  11.16 36.528 11.424 36.56 ;
     RECT  11.448 36.528 11.664 36.56 ;
     RECT  11.688 36.528 11.904 36.56 ;
     RECT  11.928 36.528 12.144 36.56 ;
     RECT  12.168 36.528 12.384 36.56 ;
     RECT  12.408 36.528 12.624 36.56 ;
     RECT  12.648 36.528 12.864 36.56 ;
     RECT  12.888 36.528 13.152 36.56 ;
     RECT  13.176 36.528 13.392 36.56 ;
     RECT  13.416 36.528 13.632 36.56 ;
     RECT  13.656 36.528 13.872 36.56 ;
     RECT  13.896 36.528 14.112 36.56 ;
     RECT  14.136 36.528 14.352 36.56 ;
     RECT  14.376 36.528 14.592 36.56 ;
     RECT  14.616 36.528 14.88 36.56 ;
     RECT  14.904 36.528 15.12 36.56 ;
     RECT  15.144 36.528 15.36 36.56 ;
     RECT  15.384 36.528 15.6 36.56 ;
     RECT  15.624 36.528 15.84 36.56 ;
     RECT  15.864 36.528 16.08 36.56 ;
     RECT  16.104 36.528 16.32 36.56 ;
     RECT  16.344 36.528 16.608 36.56 ;
     RECT  16.632 36.528 16.848 36.56 ;
     RECT  16.872 36.528 17.088 36.56 ;
     RECT  17.112 36.528 17.328 36.56 ;
     RECT  17.352 36.528 17.568 36.56 ;
     RECT  17.592 36.528 17.808 36.56 ;
     RECT  17.832 36.528 18.048 36.56 ;
     RECT  18.072 36.528 18.336 36.56 ;
     RECT  18.36 36.528 18.576 36.56 ;
     RECT  18.6 36.528 18.816 36.56 ;
     RECT  18.84 36.528 19.056 36.56 ;
     RECT  19.08 36.528 19.296 36.56 ;
     RECT  19.32 36.528 19.536 36.56 ;
     RECT  19.56 36.528 19.776 36.56 ;
     RECT  19.8 36.528 20.064 36.56 ;
     RECT  20.088 36.528 20.304 36.56 ;
     RECT  20.328 36.528 20.544 36.56 ;
     RECT  20.568 36.528 20.784 36.56 ;
     RECT  20.808 36.528 21.024 36.56 ;
     RECT  21.048 36.528 21.264 36.56 ;
     RECT  21.288 36.528 21.504 36.56 ;
     RECT  21.528 36.528 21.792 36.56 ;
     RECT  21.816 36.528 22.032 36.56 ;
     RECT  22.056 36.528 22.272 36.56 ;
     RECT  22.296 36.528 22.512 36.56 ;
     RECT  22.536 36.528 22.752 36.56 ;
     RECT  22.776 36.528 22.992 36.56 ;
     RECT  23.016 36.528 23.232 36.56 ;
     RECT  23.256 36.528 23.52 36.56 ;
     RECT  23.544 36.528 23.76 36.56 ;
     RECT  23.784 36.528 24 36.56 ;
     RECT  24.024 36.528 24.24 36.56 ;
     RECT  24.264 36.528 24.48 36.56 ;
     RECT  24.504 36.528 24.72 36.56 ;
     RECT  24.744 36.528 24.96 36.56 ;
     RECT  24.984 36.528 25.248 36.56 ;
     RECT  25.272 36.528 25.488 36.56 ;
     RECT  25.512 36.528 25.728 36.56 ;
     RECT  25.752 36.528 25.968 36.56 ;
     RECT  25.992 36.528 26.208 36.56 ;
     RECT  26.232 36.528 26.448 36.56 ;
     RECT  26.472 36.528 26.688 36.56 ;
     RECT  26.712 36.528 26.976 36.56 ;
     RECT  27 36.528 27.216 36.56 ;
     RECT  27.24 36.528 27.456 36.56 ;
     RECT  27.48 36.528 27.696 36.56 ;
     RECT  27.72 36.528 27.936 36.56 ;
     RECT  27.96 36.528 28.176 36.56 ;
     RECT  28.2 36.528 28.416 36.56 ;
     RECT  28.44 36.528 28.704 36.56 ;
     RECT  28.728 36.528 28.944 36.56 ;
     RECT  28.968 36.528 29.184 36.56 ;
     RECT  29.208 36.528 29.424 36.56 ;
     RECT  29.448 36.528 29.664 36.56 ;
     RECT  29.688 36.528 29.904 36.56 ;
     RECT  29.928 36.528 30.144 36.56 ;
     RECT  30.168 36.528 30.432 36.56 ;
     RECT  30.456 36.528 30.672 36.56 ;
     RECT  30.696 36.528 30.912 36.56 ;
     RECT  30.936 36.528 31.152 36.56 ;
     RECT  31.176 36.528 31.392 36.56 ;
     RECT  31.416 36.528 31.632 36.56 ;
     RECT  31.656 36.528 31.872 36.56 ;
     RECT  31.896 36.528 32.16 36.56 ;
     RECT  32.184 36.528 32.4 36.56 ;
     RECT  32.424 36.528 32.64 36.56 ;
     RECT  32.664 36.528 32.88 36.56 ;
     RECT  32.904 36.528 33.12 36.56 ;
     RECT  33.144 36.528 33.36 36.56 ;
     RECT  33.384 36.528 33.6 36.56 ;
     RECT  33.624 36.528 33.888 36.56 ;
     RECT  33.912 36.528 34.128 36.56 ;
     RECT  34.152 36.528 34.368 36.56 ;
     RECT  34.392 36.528 34.608 36.56 ;
     RECT  34.632 36.528 34.848 36.56 ;
     RECT  34.872 36.528 35.088 36.56 ;
     RECT  35.112 36.528 35.328 36.56 ;
     RECT  35.352 36.528 35.616 36.56 ;
     RECT  35.64 36.528 35.856 36.56 ;
     RECT  35.88 36.528 36.096 36.56 ;
     RECT  36.12 36.528 36.336 36.56 ;
     RECT  36.36 36.528 36.576 36.56 ;
     RECT  36.6 36.528 36.816 36.56 ;
     RECT  36.84 36.528 37.056 36.56 ;
     RECT  37.08 36.528 37.344 36.56 ;
     RECT  37.368 36.528 37.584 36.56 ;
     RECT  37.608 36.528 37.824 36.56 ;
     RECT  37.848 36.528 38.064 36.56 ;
     RECT  38.088 36.528 38.304 36.56 ;
     RECT  38.328 36.528 38.544 36.56 ;
     RECT  38.568 36.528 38.784 36.56 ;
     RECT  38.808 36.528 39.072 36.56 ;
     RECT  39.096 36.528 39.312 36.56 ;
     RECT  39.336 36.528 39.552 36.56 ;
     RECT  39.576 36.528 39.792 36.56 ;
     RECT  39.816 36.528 40.032 36.56 ;
     RECT  40.056 36.528 40.272 36.56 ;
     RECT  40.296 36.528 40.512 36.56 ;
     RECT  40.536 36.528 40.8 36.56 ;
     RECT  40.824 36.528 41.04 36.56 ;
     RECT  41.064 36.528 41.28 36.56 ;
     RECT  41.304 36.528 41.52 36.56 ;
     RECT  41.544 36.528 41.76 36.56 ;
     RECT  41.784 36.528 42 36.56 ;
     RECT  42.024 36.528 42.24 36.56 ;
     RECT  42.264 36.528 42.528 36.56 ;
     RECT  42.552 36.528 42.768 36.56 ;
     RECT  42.792 36.528 43.008 36.56 ;
     RECT  43.032 36.528 43.248 36.56 ;
     RECT  43.272 36.528 43.488 36.56 ;
     RECT  43.512 36.528 43.728 36.56 ;
     RECT  43.752 36.528 43.968 36.56 ;
     RECT  43.992 36.528 44.256 36.56 ;
     RECT  44.28 36.528 44.496 36.56 ;
     RECT  44.52 36.528 44.736 36.56 ;
     RECT  44.76 36.528 44.976 36.56 ;
     RECT  45 36.528 45.216 36.56 ;
     RECT  45.24 36.528 45.456 36.56 ;
     RECT  45.48 36.528 45.696 36.56 ;
     RECT  45.72 36.528 45.984 36.56 ;
     RECT  46.008 36.528 46.224 36.56 ;
     RECT  46.248 36.528 46.464 36.56 ;
     RECT  46.488 36.528 46.704 36.56 ;
     RECT  46.728 36.528 46.944 36.56 ;
     RECT  46.968 36.528 47.184 36.56 ;
     RECT  47.208 36.528 47.424 36.56 ;
     RECT  47.448 36.528 47.712 36.56 ;
     RECT  47.736 36.528 47.952 36.56 ;
     RECT  47.976 36.528 48.192 36.56 ;
     RECT  48.216 36.528 48.432 36.56 ;
     RECT  48.456 36.528 48.672 36.56 ;
     RECT  48.696 36.528 48.912 36.56 ;
     RECT  48.936 36.528 49.152 36.56 ;
     RECT  49.176 36.528 49.44 36.56 ;
     RECT  49.464 36.528 49.68 36.56 ;
     RECT  49.704 36.528 49.92 36.56 ;
     RECT  49.944 36.528 50.16 36.56 ;
     RECT  50.184 36.528 50.4 36.56 ;
     RECT  50.424 36.528 50.64 36.56 ;
     RECT  50.664 36.528 50.88 36.56 ;
     RECT  50.904 36.528 51.168 36.56 ;
     RECT  51.192 36.528 51.408 36.56 ;
     RECT  51.432 36.528 51.648 36.56 ;
     RECT  51.672 36.528 51.888 36.56 ;
     RECT  51.912 36.528 52.128 36.56 ;
     RECT  52.152 36.528 52.368 36.56 ;
     RECT  52.392 36.528 52.608 36.56 ;
     RECT  52.632 36.528 52.896 36.56 ;
     RECT  52.92 36.528 53.136 36.56 ;
     RECT  53.16 36.528 53.376 36.56 ;
     RECT  53.4 36.528 53.616 36.56 ;
     RECT  53.64 36.528 53.856 36.56 ;
     RECT  53.88 36.528 54.096 36.56 ;
     RECT  54.12 36.528 54.336 36.56 ;
     RECT  54.36 36.528 54.624 36.56 ;
     RECT  54.648 36.528 54.864 36.56 ;
     RECT  54.888 36.528 55.104 36.56 ;
     RECT  55.128 36.528 55.344 36.56 ;
     RECT  55.368 36.528 55.584 36.56 ;
     RECT  55.608 36.528 55.824 36.56 ;
     RECT  55.848 36.528 56.064 36.56 ;
     RECT  56.088 36.528 56.352 36.56 ;
     RECT  56.376 36.528 56.592 36.56 ;
     RECT  56.616 36.528 56.832 36.56 ;
     RECT  56.856 36.528 57.072 36.56 ;
     RECT  57.096 36.528 57.312 36.56 ;
     RECT  57.336 36.528 57.552 36.56 ;
     RECT  57.576 36.528 57.792 36.56 ;
     RECT  57.816 36.528 58.08 36.56 ;
     RECT  58.104 36.528 58.32 36.56 ;
     RECT  58.344 36.528 58.56 36.56 ;
     RECT  58.584 36.528 58.8 36.56 ;
     RECT  58.824 36.528 59.04 36.56 ;
     RECT  59.064 36.528 59.28 36.56 ;
     RECT  59.304 36.528 59.52 36.56 ;
     RECT  59.544 36.528 59.808 36.56 ;
     RECT  59.832 36.528 60.048 36.56 ;
     RECT  60.072 36.528 60.288 36.56 ;
     RECT  60.312 36.528 60.528 36.56 ;
     RECT  60.552 36.528 60.768 36.56 ;
     RECT  60.792 36.528 61.008 36.56 ;
     RECT  61.032 36.528 61.248 36.56 ;
     RECT  61.272 36.528 61.536 36.56 ;
     RECT  61.56 36.528 61.776 36.56 ;
     RECT  61.8 36.528 62.016 36.56 ;
     RECT  62.04 36.528 62.256 36.56 ;
     RECT  62.28 36.528 62.496 36.56 ;
     RECT  62.52 36.528 62.736 36.56 ;
     RECT  62.76 36.528 62.976 36.56 ;
     RECT  63 36.528 63.264 36.56 ;
     RECT  63.288 36.528 63.504 36.56 ;
     RECT  63.528 36.528 63.744 36.56 ;
     RECT  63.768 36.528 63.984 36.56 ;
     RECT  64.008 36.528 64.224 36.56 ;
     RECT  64.248 36.528 64.464 36.56 ;
     RECT  64.488 36.528 64.704 36.56 ;
     RECT  64.728 36.528 64.992 36.56 ;
     RECT  65.016 36.528 65.232 36.56 ;
     RECT  65.256 36.528 65.472 36.56 ;
     RECT  65.496 36.528 65.712 36.56 ;
     RECT  65.736 36.528 65.952 36.56 ;
     RECT  65.976 36.528 66.192 36.56 ;
     RECT  66.216 36.528 66.432 36.56 ;
     RECT  66.456 36.528 66.72 36.56 ;
     RECT  66.744 36.528 66.96 36.56 ;
     RECT  66.984 36.528 67.2 36.56 ;
     RECT  67.224 36.528 67.44 36.56 ;
     RECT  67.464 36.528 67.68 36.56 ;
     RECT  67.704 36.528 67.92 36.56 ;
     RECT  67.944 36.528 68.16 36.56 ;
     RECT  68.184 36.528 68.448 36.56 ;
     RECT  68.472 36.528 68.688 36.56 ;
     RECT  68.712 36.528 68.928 36.56 ;
     RECT  68.952 36.528 69.168 36.56 ;
     RECT  69.192 36.528 69.408 36.56 ;
     RECT  69.432 36.528 69.648 36.56 ;
     RECT  69.672 36.528 69.888 36.56 ;
     RECT  69.912 36.528 70.176 36.56 ;
     RECT  70.2 36.528 70.416 36.56 ;
     RECT  70.44 36.528 70.656 36.56 ;
     RECT  70.68 36.528 70.896 36.56 ;
     RECT  70.92 36.528 71.136 36.56 ;
     RECT  71.16 36.528 71.376 36.56 ;
     RECT  71.4 36.528 71.616 36.56 ;
     RECT  71.64 36.528 71.904 36.56 ;
     RECT  71.928 36.528 72.144 36.56 ;
     RECT  72.168 36.528 72.384 36.56 ;
     RECT  72.408 36.528 72.624 36.56 ;
     RECT  72.648 36.528 72.864 36.56 ;
     RECT  72.888 36.528 73.104 36.56 ;
     RECT  73.128 36.528 73.344 36.56 ;
     RECT  56.184 0.133 56.304 0.144 ;
     RECT  56.424 0.133 56.544 0.144 ;
     RECT  56.664 0.133 56.784 0.144 ;
     RECT  56.904 0.133 57.024 0.144 ;
     RECT  57.144 0.133 57.216 0.144 ;
     RECT  51.312 1.763 52.368 2.725 ;
     RECT  71.16 1.763 72.144 1.859 ;
     RECT  14.136 1.811 15.36 2.915 ;
     RECT  16.344 1.811 17.568 2.915 ;
     RECT  21.612 1.811 23.76 2.821 ;
     RECT  71.064 1.859 72.144 3.059 ;
     RECT  60.552 2.291 61.536 2.963 ;
     RECT  21.612 2.821 23.328 3.205 ;
     RECT  8.472 2.915 10.176 3.443 ;
     RECT  18.144 2.915 18.6 3.973 ;
     RECT  19.08 2.963 20.304 3.443 ;
     RECT  51.72 2.963 52.704 5.171 ;
     RECT  60.552 2.963 61.584 4.117 ;
     RECT  71.064 3.059 72.432 3.443 ;
     RECT  11.112 3.155 12.144 3.443 ;
     RECT  22.056 3.205 23.328 4.453 ;
     RECT  2.712 3.301 4.032 4.595 ;
     RECT  4.056 3.301 5.1 4.595 ;
     RECT  69.792 3.347 69.9 3.925 ;
     RECT  9.648 3.443 10.176 4.261 ;
     RECT  11.112 3.443 12.384 4.019 ;
     RECT  18.912 3.443 20.304 4.261 ;
     RECT  30.936 3.443 31.92 5.029 ;
     RECT  54.744 3.443 55.728 4.501 ;
     RECT  70.212 3.443 70.824 4.501 ;
     RECT  68.856 3.925 69.9 5.989 ;
     RECT  13.104 4.019 13.2 5.125 ;
     RECT  38.28 4.067 39.264 5.747 ;
     RECT  18.912 4.261 19.968 4.501 ;
     RECT  19.992 4.403 21.168 5.171 ;
     RECT  22.056 4.453 23.232 5.029 ;
     RECT  73.848 4.501 75.3 5.747 ;
     RECT  59.412 4.595 60.384 6.323 ;
     RECT  13.512 4.643 14.136 5.029 ;
     RECT  63.24 4.643 64.5 7.187 ;
     RECT  67.848 4.643 68.832 5.843 ;
     RECT  49.56 4.691 50.544 5.795 ;
     RECT  46.104 4.931 47.088 5.795 ;
     RECT  13.512 5.029 14.592 5.171 ;
     RECT  14.616 5.029 15.9 5.171 ;
     RECT  10.812 5.171 11.112 5.989 ;
     RECT  15.456 5.171 15.9 5.797 ;
     RECT  19.992 5.171 21.3 5.605 ;
     RECT  25.704 5.171 26.7 5.987 ;
     RECT  33.624 5.171 34.8 6.323 ;
     RECT  51.312 5.171 52.704 5.605 ;
     RECT  18.912 5.267 19.968 6.419 ;
     RECT  41.064 5.363 42.048 6.373 ;
     RECT  20.04 5.605 21.3 6.323 ;
     RECT  51.312 5.605 52.416 6.323 ;
     RECT  38.28 5.747 39.696 6.563 ;
     RECT  49.56 5.795 50.88 6.323 ;
     RECT  67.752 5.843 68.832 6.803 ;
     RECT  25.56 5.987 26.7 6.323 ;
     RECT  10.812 5.989 12.192 6.661 ;
     RECT  22.152 6.131 23.232 7.523 ;
     RECT  19.992 6.323 21.3 6.419 ;
     RECT  25.272 6.323 26.7 6.995 ;
     RECT  27.192 6.323 28.368 6.899 ;
     RECT  29.712 6.323 30.816 6.851 ;
     RECT  33.48 6.323 34.8 8.003 ;
     RECT  35.64 6.323 37.008 6.371 ;
     RECT  51.312 6.323 52.512 6.659 ;
     RECT  59.412 6.323 60.816 6.611 ;
     RECT  21.168 6.419 21.3 6.805 ;
     RECT  38.184 6.563 39.696 6.899 ;
     RECT  43.32 6.563 44.448 6.899 ;
     RECT  59.412 6.611 59.832 6.805 ;
     RECT  12.216 6.659 13.2 6.899 ;
     RECT  43.212 6.899 44.448 8.579 ;
     RECT  62.112 6.947 63.216 7.187 ;
     RECT  56.712 7.523 58.128 9.155 ;
     RECT  44.472 8.003 45.6 8.579 ;
     RECT  56.808 30.181 58.08 30.709 ;
     RECT  58.104 30.181 59.1 30.661 ;
     RECT  8.112 30.469 9.408 30.709 ;
     RECT  9.432 30.469 10.5 30.853 ;
     RECT  11.688 30.469 13.2 30.565 ;
     RECT  54.888 30.469 56.4 30.517 ;
     RECT  64.812 30.469 65.952 31.285 ;
     RECT  65.976 30.469 67.2 30.709 ;
     RECT  71.16 30.469 72.6 34.213 ;
     RECT  27.96 30.517 29.4 30.661 ;
     RECT  21.612 30.661 22.848 30.757 ;
     RECT  27.96 30.661 29.184 34.213 ;
     RECT  35.112 30.661 36.576 30.709 ;
     RECT  5.976 30.709 7.44 31.285 ;
     RECT  13.512 30.709 14.592 30.805 ;
     RECT  14.616 30.709 15.9 30.805 ;
     RECT  25.272 30.709 26.448 31.237 ;
     RECT  35.352 30.709 36.576 31.285 ;
     RECT  56.856 30.709 58.08 30.805 ;
     RECT  60.312 30.709 61.632 34.213 ;
     RECT  62.112 30.709 63.504 30.805 ;
     RECT  21.612 30.757 22.752 34.213 ;
     RECT  22.776 30.803 23.76 34.213 ;
     RECT  14.904 30.805 15.9 30.949 ;
     RECT  16.212 30.805 17.568 31.285 ;
     RECT  17.592 30.805 18.6 30.853 ;
     RECT  43.32 30.805 44.736 34.213 ;
     RECT  48.744 30.805 49.92 30.997 ;
     RECT  48.936 30.997 49.92 31.045 ;
     RECT  16.344 31.285 17.568 34.213 ;
     RECT  20.328 31.285 21.3 34.357 ;
     RECT  33.624 31.285 34.8 34.213 ;
     RECT  35.352 31.285 36.336 34.213 ;
     RECT  38.088 31.285 39.072 34.741 ;
     RECT  28.2 34.213 29.184 34.741 ;
     RECT  33.624 34.213 34.608 34.741 ;
     RECT  71.4 34.213 72.6 34.453 ;
     RECT  71.4 34.453 72.48 34.645 ;
     RECT  71.4 34.645 72.432 34.741 ;
  END
END dsfd_hstnv_560
END LIBRARY
